VERSION 5.8 ;
BUSBITCHARS "[]" ;
DIVIDERCHAR "/" ;
UNITS
    DATABASE MICRONS 1000 ;
END UNITS

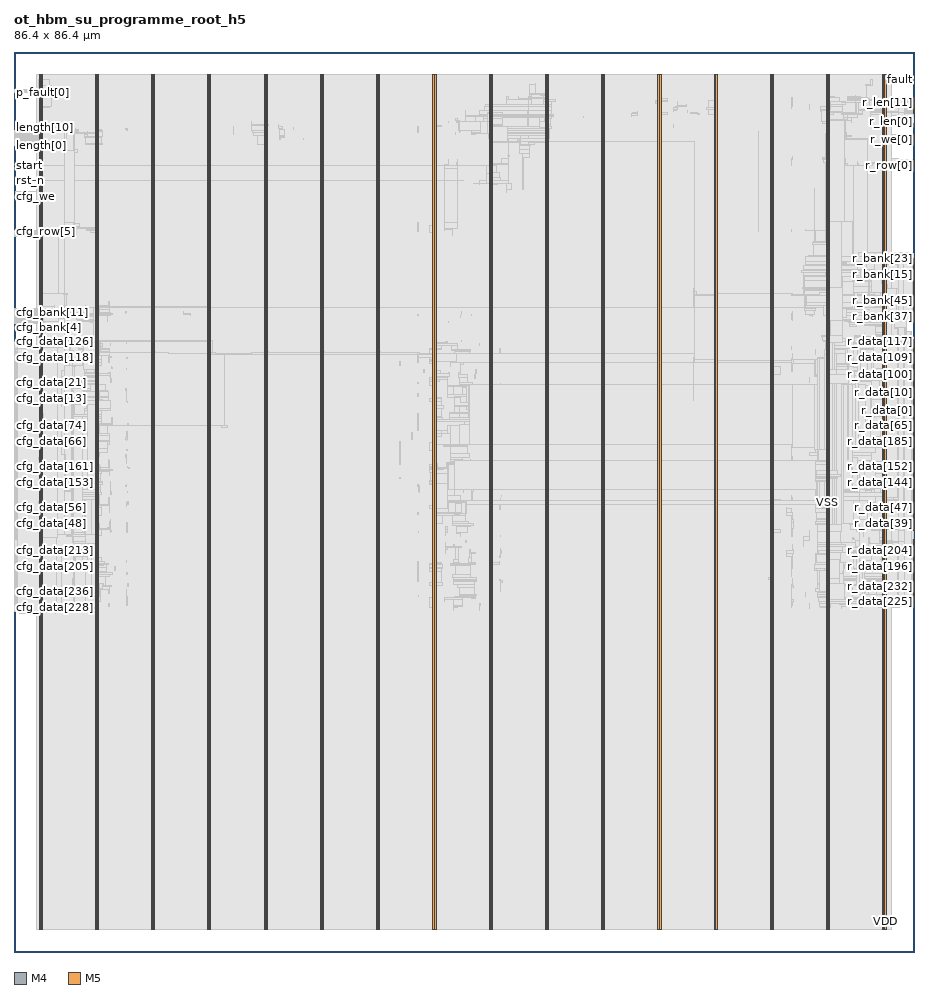
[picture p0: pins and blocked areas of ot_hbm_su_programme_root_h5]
MACRO ot_hbm_su_programme_root_h5
  FOREIGN ot_hbm_su_programme_root_h5 0 0 ;
  CLASS BLOCK ;
  SIZE 86.4 BY 86.4 ;
  PIN cfg_bank[0]
    DIRECTION INPUT ;
    USE SIGNAL ;
    PORT
      LAYER M4 ;
        RECT  0 60.336 0.084 60.36 ;
    END
  END cfg_bank[0]
  PIN cfg_bank[10]
    DIRECTION INPUT ;
    USE SIGNAL ;
    PORT
      LAYER M4 ;
        RECT  0 61.296 0.084 61.32 ;
    END
  END cfg_bank[10]
  PIN cfg_bank[11]
    DIRECTION INPUT ;
    USE SIGNAL ;
    PORT
      LAYER M4 ;
        RECT  0 61.392 0.084 61.416 ;
    END
  END cfg_bank[11]
  PIN cfg_bank[12]
    DIRECTION INPUT ;
    USE SIGNAL ;
    PORT
      LAYER M4 ;
        RECT  0 61.488 0.084 61.512 ;
    END
  END cfg_bank[12]
  PIN cfg_bank[13]
    DIRECTION INPUT ;
    USE SIGNAL ;
    PORT
      LAYER M4 ;
        RECT  0 61.584 0.084 61.608 ;
    END
  END cfg_bank[13]
  PIN cfg_bank[14]
    DIRECTION INPUT ;
    USE SIGNAL ;
    PORT
      LAYER M4 ;
        RECT  0 61.68 0.084 61.704 ;
    END
  END cfg_bank[14]
  PIN cfg_bank[15]
    DIRECTION INPUT ;
    USE SIGNAL ;
    PORT
      LAYER M4 ;
        RECT  0 61.776 0.084 61.8 ;
    END
  END cfg_bank[15]
  PIN cfg_bank[1]
    DIRECTION INPUT ;
    USE SIGNAL ;
    PORT
      LAYER M4 ;
        RECT  0 60.432 0.084 60.456 ;
    END
  END cfg_bank[1]
  PIN cfg_bank[2]
    DIRECTION INPUT ;
    USE SIGNAL ;
    PORT
      LAYER M4 ;
        RECT  0 60.528 0.084 60.552 ;
    END
  END cfg_bank[2]
  PIN cfg_bank[3]
    DIRECTION INPUT ;
    USE SIGNAL ;
    PORT
      LAYER M4 ;
        RECT  0 60.624 0.084 60.648 ;
    END
  END cfg_bank[3]
  PIN cfg_bank[4]
    DIRECTION INPUT ;
    USE SIGNAL ;
    PORT
      LAYER M4 ;
        RECT  0 60.72 0.084 60.744 ;
    END
  END cfg_bank[4]
  PIN cfg_bank[5]
    DIRECTION INPUT ;
    USE SIGNAL ;
    PORT
      LAYER M4 ;
        RECT  0 60.816 0.084 60.84 ;
    END
  END cfg_bank[5]
  PIN cfg_bank[6]
    DIRECTION INPUT ;
    USE SIGNAL ;
    PORT
      LAYER M4 ;
        RECT  0 60.912 0.084 60.936 ;
    END
  END cfg_bank[6]
  PIN cfg_bank[7]
    DIRECTION INPUT ;
    USE SIGNAL ;
    PORT
      LAYER M4 ;
        RECT  0 61.008 0.084 61.032 ;
    END
  END cfg_bank[7]
  PIN cfg_bank[8]
    DIRECTION INPUT ;
    USE SIGNAL ;
    PORT
      LAYER M4 ;
        RECT  0 61.104 0.084 61.128 ;
    END
  END cfg_bank[8]
  PIN cfg_bank[9]
    DIRECTION INPUT ;
    USE SIGNAL ;
    PORT
      LAYER M4 ;
        RECT  0 61.2 0.084 61.224 ;
    END
  END cfg_bank[9]
  PIN cfg_data[0]
    DIRECTION INPUT ;
    USE SIGNAL ;
    PORT
      LAYER M4 ;
        RECT  0 51.888 0.084 51.912 ;
    END
  END cfg_data[0]
  PIN cfg_data[100]
    DIRECTION INPUT ;
    USE SIGNAL ;
    PORT
      LAYER M4 ;
        RECT  0 55.344 0.084 55.368 ;
    END
  END cfg_data[100]
  PIN cfg_data[101]
    DIRECTION INPUT ;
    USE SIGNAL ;
    PORT
      LAYER M4 ;
        RECT  0 55.44 0.084 55.464 ;
    END
  END cfg_data[101]
  PIN cfg_data[102]
    DIRECTION INPUT ;
    USE SIGNAL ;
    PORT
      LAYER M4 ;
        RECT  0 55.536 0.084 55.56 ;
    END
  END cfg_data[102]
  PIN cfg_data[103]
    DIRECTION INPUT ;
    USE SIGNAL ;
    PORT
      LAYER M4 ;
        RECT  0 55.632 0.084 55.656 ;
    END
  END cfg_data[103]
  PIN cfg_data[104]
    DIRECTION INPUT ;
    USE SIGNAL ;
    PORT
      LAYER M4 ;
        RECT  0 55.728 0.084 55.752 ;
    END
  END cfg_data[104]
  PIN cfg_data[105]
    DIRECTION INPUT ;
    USE SIGNAL ;
    PORT
      LAYER M4 ;
        RECT  0 55.824 0.084 55.848 ;
    END
  END cfg_data[105]
  PIN cfg_data[106]
    DIRECTION INPUT ;
    USE SIGNAL ;
    PORT
      LAYER M4 ;
        RECT  0 55.92 0.084 55.944 ;
    END
  END cfg_data[106]
  PIN cfg_data[107]
    DIRECTION INPUT ;
    USE SIGNAL ;
    PORT
      LAYER M4 ;
        RECT  0 56.016 0.084 56.04 ;
    END
  END cfg_data[107]
  PIN cfg_data[108]
    DIRECTION INPUT ;
    USE SIGNAL ;
    PORT
      LAYER M4 ;
        RECT  0 56.112 0.084 56.136 ;
    END
  END cfg_data[108]
  PIN cfg_data[109]
    DIRECTION INPUT ;
    USE SIGNAL ;
    PORT
      LAYER M4 ;
        RECT  0 56.208 0.084 56.232 ;
    END
  END cfg_data[109]
  PIN cfg_data[10]
    DIRECTION INPUT ;
    USE SIGNAL ;
    PORT
      LAYER M4 ;
        RECT  0 52.848 0.084 52.872 ;
    END
  END cfg_data[10]
  PIN cfg_data[110]
    DIRECTION INPUT ;
    USE SIGNAL ;
    PORT
      LAYER M4 ;
        RECT  0 56.304 0.084 56.328 ;
    END
  END cfg_data[110]
  PIN cfg_data[111]
    DIRECTION INPUT ;
    USE SIGNAL ;
    PORT
      LAYER M4 ;
        RECT  0 56.4 0.084 56.424 ;
    END
  END cfg_data[111]
  PIN cfg_data[112]
    DIRECTION INPUT ;
    USE SIGNAL ;
    PORT
      LAYER M4 ;
        RECT  0 56.496 0.084 56.52 ;
    END
  END cfg_data[112]
  PIN cfg_data[113]
    DIRECTION INPUT ;
    USE SIGNAL ;
    PORT
      LAYER M4 ;
        RECT  0 56.592 0.084 56.616 ;
    END
  END cfg_data[113]
  PIN cfg_data[114]
    DIRECTION INPUT ;
    USE SIGNAL ;
    PORT
      LAYER M4 ;
        RECT  0 56.688 0.084 56.712 ;
    END
  END cfg_data[114]
  PIN cfg_data[115]
    DIRECTION INPUT ;
    USE SIGNAL ;
    PORT
      LAYER M4 ;
        RECT  0 56.784 0.084 56.808 ;
    END
  END cfg_data[115]
  PIN cfg_data[116]
    DIRECTION INPUT ;
    USE SIGNAL ;
    PORT
      LAYER M4 ;
        RECT  0 56.88 0.084 56.904 ;
    END
  END cfg_data[116]
  PIN cfg_data[117]
    DIRECTION INPUT ;
    USE SIGNAL ;
    PORT
      LAYER M4 ;
        RECT  0 56.976 0.084 57 ;
    END
  END cfg_data[117]
  PIN cfg_data[118]
    DIRECTION INPUT ;
    USE SIGNAL ;
    PORT
      LAYER M4 ;
        RECT  0 57.072 0.084 57.096 ;
    END
  END cfg_data[118]
  PIN cfg_data[119]
    DIRECTION INPUT ;
    USE SIGNAL ;
    PORT
      LAYER M4 ;
        RECT  0 57.168 0.084 57.192 ;
    END
  END cfg_data[119]
  PIN cfg_data[11]
    DIRECTION INPUT ;
    USE SIGNAL ;
    PORT
      LAYER M4 ;
        RECT  0 52.944 0.084 52.968 ;
    END
  END cfg_data[11]
  PIN cfg_data[120]
    DIRECTION INPUT ;
    USE SIGNAL ;
    PORT
      LAYER M4 ;
        RECT  0 57.264 0.084 57.288 ;
    END
  END cfg_data[120]
  PIN cfg_data[121]
    DIRECTION INPUT ;
    USE SIGNAL ;
    PORT
      LAYER M4 ;
        RECT  0 57.36 0.084 57.384 ;
    END
  END cfg_data[121]
  PIN cfg_data[122]
    DIRECTION INPUT ;
    USE SIGNAL ;
    PORT
      LAYER M4 ;
        RECT  0 57.456 0.084 57.48 ;
    END
  END cfg_data[122]
  PIN cfg_data[123]
    DIRECTION INPUT ;
    USE SIGNAL ;
    PORT
      LAYER M4 ;
        RECT  0 57.552 0.084 57.576 ;
    END
  END cfg_data[123]
  PIN cfg_data[124]
    DIRECTION INPUT ;
    USE SIGNAL ;
    PORT
      LAYER M4 ;
        RECT  0 57.648 0.084 57.672 ;
    END
  END cfg_data[124]
  PIN cfg_data[125]
    DIRECTION INPUT ;
    USE SIGNAL ;
    PORT
      LAYER M4 ;
        RECT  0 57.744 0.084 57.768 ;
    END
  END cfg_data[125]
  PIN cfg_data[126]
    DIRECTION INPUT ;
    USE SIGNAL ;
    PORT
      LAYER M4 ;
        RECT  0 57.84 0.084 57.864 ;
    END
  END cfg_data[126]
  PIN cfg_data[127]
    DIRECTION INPUT ;
    USE SIGNAL ;
    PORT
      LAYER M4 ;
        RECT  0 57.936 0.084 57.96 ;
    END
  END cfg_data[127]
  PIN cfg_data[128]
    DIRECTION INPUT ;
    USE SIGNAL ;
    PORT
      LAYER M4 ;
        RECT  0 42.672 0.084 42.696 ;
    END
  END cfg_data[128]
  PIN cfg_data[129]
    DIRECTION INPUT ;
    USE SIGNAL ;
    PORT
      LAYER M4 ;
        RECT  0 42.768 0.084 42.792 ;
    END
  END cfg_data[129]
  PIN cfg_data[12]
    DIRECTION INPUT ;
    USE SIGNAL ;
    PORT
      LAYER M4 ;
        RECT  0 53.04 0.084 53.064 ;
    END
  END cfg_data[12]
  PIN cfg_data[130]
    DIRECTION INPUT ;
    USE SIGNAL ;
    PORT
      LAYER M4 ;
        RECT  0 42.864 0.084 42.888 ;
    END
  END cfg_data[130]
  PIN cfg_data[131]
    DIRECTION INPUT ;
    USE SIGNAL ;
    PORT
      LAYER M4 ;
        RECT  0 42.96 0.084 42.984 ;
    END
  END cfg_data[131]
  PIN cfg_data[132]
    DIRECTION INPUT ;
    USE SIGNAL ;
    PORT
      LAYER M4 ;
        RECT  0 43.056 0.084 43.08 ;
    END
  END cfg_data[132]
  PIN cfg_data[133]
    DIRECTION INPUT ;
    USE SIGNAL ;
    PORT
      LAYER M4 ;
        RECT  0 43.152 0.084 43.176 ;
    END
  END cfg_data[133]
  PIN cfg_data[134]
    DIRECTION INPUT ;
    USE SIGNAL ;
    PORT
      LAYER M4 ;
        RECT  0 43.248 0.084 43.272 ;
    END
  END cfg_data[134]
  PIN cfg_data[135]
    DIRECTION INPUT ;
    USE SIGNAL ;
    PORT
      LAYER M4 ;
        RECT  0 43.344 0.084 43.368 ;
    END
  END cfg_data[135]
  PIN cfg_data[136]
    DIRECTION INPUT ;
    USE SIGNAL ;
    PORT
      LAYER M4 ;
        RECT  0 43.44 0.084 43.464 ;
    END
  END cfg_data[136]
  PIN cfg_data[137]
    DIRECTION INPUT ;
    USE SIGNAL ;
    PORT
      LAYER M4 ;
        RECT  0 43.536 0.084 43.56 ;
    END
  END cfg_data[137]
  PIN cfg_data[138]
    DIRECTION INPUT ;
    USE SIGNAL ;
    PORT
      LAYER M4 ;
        RECT  0 43.632 0.084 43.656 ;
    END
  END cfg_data[138]
  PIN cfg_data[139]
    DIRECTION INPUT ;
    USE SIGNAL ;
    PORT
      LAYER M4 ;
        RECT  0 43.728 0.084 43.752 ;
    END
  END cfg_data[139]
  PIN cfg_data[13]
    DIRECTION INPUT ;
    USE SIGNAL ;
    PORT
      LAYER M4 ;
        RECT  0 53.136 0.084 53.16 ;
    END
  END cfg_data[13]
  PIN cfg_data[140]
    DIRECTION INPUT ;
    USE SIGNAL ;
    PORT
      LAYER M4 ;
        RECT  0 43.824 0.084 43.848 ;
    END
  END cfg_data[140]
  PIN cfg_data[141]
    DIRECTION INPUT ;
    USE SIGNAL ;
    PORT
      LAYER M4 ;
        RECT  0 43.92 0.084 43.944 ;
    END
  END cfg_data[141]
  PIN cfg_data[142]
    DIRECTION INPUT ;
    USE SIGNAL ;
    PORT
      LAYER M4 ;
        RECT  0 44.016 0.084 44.04 ;
    END
  END cfg_data[142]
  PIN cfg_data[143]
    DIRECTION INPUT ;
    USE SIGNAL ;
    PORT
      LAYER M4 ;
        RECT  0 44.112 0.084 44.136 ;
    END
  END cfg_data[143]
  PIN cfg_data[144]
    DIRECTION INPUT ;
    USE SIGNAL ;
    PORT
      LAYER M4 ;
        RECT  0 44.208 0.084 44.232 ;
    END
  END cfg_data[144]
  PIN cfg_data[145]
    DIRECTION INPUT ;
    USE SIGNAL ;
    PORT
      LAYER M4 ;
        RECT  0 44.304 0.084 44.328 ;
    END
  END cfg_data[145]
  PIN cfg_data[146]
    DIRECTION INPUT ;
    USE SIGNAL ;
    PORT
      LAYER M4 ;
        RECT  0 44.4 0.084 44.424 ;
    END
  END cfg_data[146]
  PIN cfg_data[147]
    DIRECTION INPUT ;
    USE SIGNAL ;
    PORT
      LAYER M4 ;
        RECT  0 44.496 0.084 44.52 ;
    END
  END cfg_data[147]
  PIN cfg_data[148]
    DIRECTION INPUT ;
    USE SIGNAL ;
    PORT
      LAYER M4 ;
        RECT  0 44.592 0.084 44.616 ;
    END
  END cfg_data[148]
  PIN cfg_data[149]
    DIRECTION INPUT ;
    USE SIGNAL ;
    PORT
      LAYER M4 ;
        RECT  0 44.688 0.084 44.712 ;
    END
  END cfg_data[149]
  PIN cfg_data[14]
    DIRECTION INPUT ;
    USE SIGNAL ;
    PORT
      LAYER M4 ;
        RECT  0 53.232 0.084 53.256 ;
    END
  END cfg_data[14]
  PIN cfg_data[150]
    DIRECTION INPUT ;
    USE SIGNAL ;
    PORT
      LAYER M4 ;
        RECT  0 44.784 0.084 44.808 ;
    END
  END cfg_data[150]
  PIN cfg_data[151]
    DIRECTION INPUT ;
    USE SIGNAL ;
    PORT
      LAYER M4 ;
        RECT  0 44.88 0.084 44.904 ;
    END
  END cfg_data[151]
  PIN cfg_data[152]
    DIRECTION INPUT ;
    USE SIGNAL ;
    PORT
      LAYER M4 ;
        RECT  0 44.976 0.084 45 ;
    END
  END cfg_data[152]
  PIN cfg_data[153]
    DIRECTION INPUT ;
    USE SIGNAL ;
    PORT
      LAYER M4 ;
        RECT  0 45.072 0.084 45.096 ;
    END
  END cfg_data[153]
  PIN cfg_data[154]
    DIRECTION INPUT ;
    USE SIGNAL ;
    PORT
      LAYER M4 ;
        RECT  0 45.168 0.084 45.192 ;
    END
  END cfg_data[154]
  PIN cfg_data[155]
    DIRECTION INPUT ;
    USE SIGNAL ;
    PORT
      LAYER M4 ;
        RECT  0 45.264 0.084 45.288 ;
    END
  END cfg_data[155]
  PIN cfg_data[156]
    DIRECTION INPUT ;
    USE SIGNAL ;
    PORT
      LAYER M4 ;
        RECT  0 45.36 0.084 45.384 ;
    END
  END cfg_data[156]
  PIN cfg_data[157]
    DIRECTION INPUT ;
    USE SIGNAL ;
    PORT
      LAYER M4 ;
        RECT  0 45.456 0.084 45.48 ;
    END
  END cfg_data[157]
  PIN cfg_data[158]
    DIRECTION INPUT ;
    USE SIGNAL ;
    PORT
      LAYER M4 ;
        RECT  0 45.552 0.084 45.576 ;
    END
  END cfg_data[158]
  PIN cfg_data[159]
    DIRECTION INPUT ;
    USE SIGNAL ;
    PORT
      LAYER M4 ;
        RECT  0 45.648 0.084 45.672 ;
    END
  END cfg_data[159]
  PIN cfg_data[15]
    DIRECTION INPUT ;
    USE SIGNAL ;
    PORT
      LAYER M4 ;
        RECT  0 53.328 0.084 53.352 ;
    END
  END cfg_data[15]
  PIN cfg_data[160]
    DIRECTION INPUT ;
    USE SIGNAL ;
    PORT
      LAYER M4 ;
        RECT  0 45.744 0.084 45.768 ;
    END
  END cfg_data[160]
  PIN cfg_data[161]
    DIRECTION INPUT ;
    USE SIGNAL ;
    PORT
      LAYER M4 ;
        RECT  0 45.84 0.084 45.864 ;
    END
  END cfg_data[161]
  PIN cfg_data[162]
    DIRECTION INPUT ;
    USE SIGNAL ;
    PORT
      LAYER M4 ;
        RECT  0 45.936 0.084 45.96 ;
    END
  END cfg_data[162]
  PIN cfg_data[163]
    DIRECTION INPUT ;
    USE SIGNAL ;
    PORT
      LAYER M4 ;
        RECT  0 46.032 0.084 46.056 ;
    END
  END cfg_data[163]
  PIN cfg_data[164]
    DIRECTION INPUT ;
    USE SIGNAL ;
    PORT
      LAYER M4 ;
        RECT  0 46.128 0.084 46.152 ;
    END
  END cfg_data[164]
  PIN cfg_data[165]
    DIRECTION INPUT ;
    USE SIGNAL ;
    PORT
      LAYER M4 ;
        RECT  0 46.224 0.084 46.248 ;
    END
  END cfg_data[165]
  PIN cfg_data[166]
    DIRECTION INPUT ;
    USE SIGNAL ;
    PORT
      LAYER M4 ;
        RECT  0 46.32 0.084 46.344 ;
    END
  END cfg_data[166]
  PIN cfg_data[167]
    DIRECTION INPUT ;
    USE SIGNAL ;
    PORT
      LAYER M4 ;
        RECT  0 46.416 0.084 46.44 ;
    END
  END cfg_data[167]
  PIN cfg_data[168]
    DIRECTION INPUT ;
    USE SIGNAL ;
    PORT
      LAYER M4 ;
        RECT  0 46.512 0.084 46.536 ;
    END
  END cfg_data[168]
  PIN cfg_data[169]
    DIRECTION INPUT ;
    USE SIGNAL ;
    PORT
      LAYER M4 ;
        RECT  0 46.608 0.084 46.632 ;
    END
  END cfg_data[169]
  PIN cfg_data[16]
    DIRECTION INPUT ;
    USE SIGNAL ;
    PORT
      LAYER M4 ;
        RECT  0 53.424 0.084 53.448 ;
    END
  END cfg_data[16]
  PIN cfg_data[170]
    DIRECTION INPUT ;
    USE SIGNAL ;
    PORT
      LAYER M4 ;
        RECT  0 46.704 0.084 46.728 ;
    END
  END cfg_data[170]
  PIN cfg_data[171]
    DIRECTION INPUT ;
    USE SIGNAL ;
    PORT
      LAYER M4 ;
        RECT  0 46.8 0.084 46.824 ;
    END
  END cfg_data[171]
  PIN cfg_data[172]
    DIRECTION INPUT ;
    USE SIGNAL ;
    PORT
      LAYER M4 ;
        RECT  0 46.896 0.084 46.92 ;
    END
  END cfg_data[172]
  PIN cfg_data[173]
    DIRECTION INPUT ;
    USE SIGNAL ;
    PORT
      LAYER M4 ;
        RECT  0 46.992 0.084 47.016 ;
    END
  END cfg_data[173]
  PIN cfg_data[174]
    DIRECTION INPUT ;
    USE SIGNAL ;
    PORT
      LAYER M4 ;
        RECT  0 47.088 0.084 47.112 ;
    END
  END cfg_data[174]
  PIN cfg_data[175]
    DIRECTION INPUT ;
    USE SIGNAL ;
    PORT
      LAYER M4 ;
        RECT  0 47.184 0.084 47.208 ;
    END
  END cfg_data[175]
  PIN cfg_data[176]
    DIRECTION INPUT ;
    USE SIGNAL ;
    PORT
      LAYER M4 ;
        RECT  0 47.28 0.084 47.304 ;
    END
  END cfg_data[176]
  PIN cfg_data[177]
    DIRECTION INPUT ;
    USE SIGNAL ;
    PORT
      LAYER M4 ;
        RECT  0 47.376 0.084 47.4 ;
    END
  END cfg_data[177]
  PIN cfg_data[178]
    DIRECTION INPUT ;
    USE SIGNAL ;
    PORT
      LAYER M4 ;
        RECT  0 47.472 0.084 47.496 ;
    END
  END cfg_data[178]
  PIN cfg_data[179]
    DIRECTION INPUT ;
    USE SIGNAL ;
    PORT
      LAYER M4 ;
        RECT  0 47.568 0.084 47.592 ;
    END
  END cfg_data[179]
  PIN cfg_data[17]
    DIRECTION INPUT ;
    USE SIGNAL ;
    PORT
      LAYER M4 ;
        RECT  0 53.52 0.084 53.544 ;
    END
  END cfg_data[17]
  PIN cfg_data[180]
    DIRECTION INPUT ;
    USE SIGNAL ;
    PORT
      LAYER M4 ;
        RECT  0 47.664 0.084 47.688 ;
    END
  END cfg_data[180]
  PIN cfg_data[181]
    DIRECTION INPUT ;
    USE SIGNAL ;
    PORT
      LAYER M4 ;
        RECT  0 47.76 0.084 47.784 ;
    END
  END cfg_data[181]
  PIN cfg_data[182]
    DIRECTION INPUT ;
    USE SIGNAL ;
    PORT
      LAYER M4 ;
        RECT  0 47.856 0.084 47.88 ;
    END
  END cfg_data[182]
  PIN cfg_data[183]
    DIRECTION INPUT ;
    USE SIGNAL ;
    PORT
      LAYER M4 ;
        RECT  0 47.952 0.084 47.976 ;
    END
  END cfg_data[183]
  PIN cfg_data[184]
    DIRECTION INPUT ;
    USE SIGNAL ;
    PORT
      LAYER M4 ;
        RECT  0 48.048 0.084 48.072 ;
    END
  END cfg_data[184]
  PIN cfg_data[185]
    DIRECTION INPUT ;
    USE SIGNAL ;
    PORT
      LAYER M4 ;
        RECT  0 48.144 0.084 48.168 ;
    END
  END cfg_data[185]
  PIN cfg_data[186]
    DIRECTION INPUT ;
    USE SIGNAL ;
    PORT
      LAYER M4 ;
        RECT  0 48.24 0.084 48.264 ;
    END
  END cfg_data[186]
  PIN cfg_data[187]
    DIRECTION INPUT ;
    USE SIGNAL ;
    PORT
      LAYER M4 ;
        RECT  0 48.336 0.084 48.36 ;
    END
  END cfg_data[187]
  PIN cfg_data[188]
    DIRECTION INPUT ;
    USE SIGNAL ;
    PORT
      LAYER M4 ;
        RECT  0 48.432 0.084 48.456 ;
    END
  END cfg_data[188]
  PIN cfg_data[189]
    DIRECTION INPUT ;
    USE SIGNAL ;
    PORT
      LAYER M4 ;
        RECT  0 48.528 0.084 48.552 ;
    END
  END cfg_data[189]
  PIN cfg_data[18]
    DIRECTION INPUT ;
    USE SIGNAL ;
    PORT
      LAYER M4 ;
        RECT  0 53.616 0.084 53.64 ;
    END
  END cfg_data[18]
  PIN cfg_data[190]
    DIRECTION INPUT ;
    USE SIGNAL ;
    PORT
      LAYER M4 ;
        RECT  0 48.624 0.084 48.648 ;
    END
  END cfg_data[190]
  PIN cfg_data[191]
    DIRECTION INPUT ;
    USE SIGNAL ;
    PORT
      LAYER M4 ;
        RECT  0 48.72 0.084 48.744 ;
    END
  END cfg_data[191]
  PIN cfg_data[192]
    DIRECTION INPUT ;
    USE SIGNAL ;
    PORT
      LAYER M4 ;
        RECT  0 35.76 0.084 35.784 ;
    END
  END cfg_data[192]
  PIN cfg_data[193]
    DIRECTION INPUT ;
    USE SIGNAL ;
    PORT
      LAYER M4 ;
        RECT  0 35.856 0.084 35.88 ;
    END
  END cfg_data[193]
  PIN cfg_data[194]
    DIRECTION INPUT ;
    USE SIGNAL ;
    PORT
      LAYER M4 ;
        RECT  0 35.952 0.084 35.976 ;
    END
  END cfg_data[194]
  PIN cfg_data[195]
    DIRECTION INPUT ;
    USE SIGNAL ;
    PORT
      LAYER M4 ;
        RECT  0 36.048 0.084 36.072 ;
    END
  END cfg_data[195]
  PIN cfg_data[196]
    DIRECTION INPUT ;
    USE SIGNAL ;
    PORT
      LAYER M4 ;
        RECT  0 36.144 0.084 36.168 ;
    END
  END cfg_data[196]
  PIN cfg_data[197]
    DIRECTION INPUT ;
    USE SIGNAL ;
    PORT
      LAYER M4 ;
        RECT  0 36.24 0.084 36.264 ;
    END
  END cfg_data[197]
  PIN cfg_data[198]
    DIRECTION INPUT ;
    USE SIGNAL ;
    PORT
      LAYER M4 ;
        RECT  0 36.336 0.084 36.36 ;
    END
  END cfg_data[198]
  PIN cfg_data[199]
    DIRECTION INPUT ;
    USE SIGNAL ;
    PORT
      LAYER M4 ;
        RECT  0 36.432 0.084 36.456 ;
    END
  END cfg_data[199]
  PIN cfg_data[19]
    DIRECTION INPUT ;
    USE SIGNAL ;
    PORT
      LAYER M4 ;
        RECT  0 53.712 0.084 53.736 ;
    END
  END cfg_data[19]
  PIN cfg_data[1]
    DIRECTION INPUT ;
    USE SIGNAL ;
    PORT
      LAYER M4 ;
        RECT  0 51.984 0.084 52.008 ;
    END
  END cfg_data[1]
  PIN cfg_data[200]
    DIRECTION INPUT ;
    USE SIGNAL ;
    PORT
      LAYER M4 ;
        RECT  0 36.528 0.084 36.552 ;
    END
  END cfg_data[200]
  PIN cfg_data[201]
    DIRECTION INPUT ;
    USE SIGNAL ;
    PORT
      LAYER M4 ;
        RECT  0 36.624 0.084 36.648 ;
    END
  END cfg_data[201]
  PIN cfg_data[202]
    DIRECTION INPUT ;
    USE SIGNAL ;
    PORT
      LAYER M4 ;
        RECT  0 36.72 0.084 36.744 ;
    END
  END cfg_data[202]
  PIN cfg_data[203]
    DIRECTION INPUT ;
    USE SIGNAL ;
    PORT
      LAYER M4 ;
        RECT  0 36.816 0.084 36.84 ;
    END
  END cfg_data[203]
  PIN cfg_data[204]
    DIRECTION INPUT ;
    USE SIGNAL ;
    PORT
      LAYER M4 ;
        RECT  0 36.912 0.084 36.936 ;
    END
  END cfg_data[204]
  PIN cfg_data[205]
    DIRECTION INPUT ;
    USE SIGNAL ;
    PORT
      LAYER M4 ;
        RECT  0 37.008 0.084 37.032 ;
    END
  END cfg_data[205]
  PIN cfg_data[206]
    DIRECTION INPUT ;
    USE SIGNAL ;
    PORT
      LAYER M4 ;
        RECT  0 37.104 0.084 37.128 ;
    END
  END cfg_data[206]
  PIN cfg_data[207]
    DIRECTION INPUT ;
    USE SIGNAL ;
    PORT
      LAYER M4 ;
        RECT  0 37.2 0.084 37.224 ;
    END
  END cfg_data[207]
  PIN cfg_data[208]
    DIRECTION INPUT ;
    USE SIGNAL ;
    PORT
      LAYER M4 ;
        RECT  0 37.296 0.084 37.32 ;
    END
  END cfg_data[208]
  PIN cfg_data[209]
    DIRECTION INPUT ;
    USE SIGNAL ;
    PORT
      LAYER M4 ;
        RECT  0 37.392 0.084 37.416 ;
    END
  END cfg_data[209]
  PIN cfg_data[20]
    DIRECTION INPUT ;
    USE SIGNAL ;
    PORT
      LAYER M4 ;
        RECT  0 53.808 0.084 53.832 ;
    END
  END cfg_data[20]
  PIN cfg_data[210]
    DIRECTION INPUT ;
    USE SIGNAL ;
    PORT
      LAYER M4 ;
        RECT  0 37.488 0.084 37.512 ;
    END
  END cfg_data[210]
  PIN cfg_data[211]
    DIRECTION INPUT ;
    USE SIGNAL ;
    PORT
      LAYER M4 ;
        RECT  0 37.584 0.084 37.608 ;
    END
  END cfg_data[211]
  PIN cfg_data[212]
    DIRECTION INPUT ;
    USE SIGNAL ;
    PORT
      LAYER M4 ;
        RECT  0 37.68 0.084 37.704 ;
    END
  END cfg_data[212]
  PIN cfg_data[213]
    DIRECTION INPUT ;
    USE SIGNAL ;
    PORT
      LAYER M4 ;
        RECT  0 37.776 0.084 37.8 ;
    END
  END cfg_data[213]
  PIN cfg_data[214]
    DIRECTION INPUT ;
    USE SIGNAL ;
    PORT
      LAYER M4 ;
        RECT  0 37.872 0.084 37.896 ;
    END
  END cfg_data[214]
  PIN cfg_data[215]
    DIRECTION INPUT ;
    USE SIGNAL ;
    PORT
      LAYER M4 ;
        RECT  0 37.968 0.084 37.992 ;
    END
  END cfg_data[215]
  PIN cfg_data[216]
    DIRECTION INPUT ;
    USE SIGNAL ;
    PORT
      LAYER M4 ;
        RECT  0 38.064 0.084 38.088 ;
    END
  END cfg_data[216]
  PIN cfg_data[217]
    DIRECTION INPUT ;
    USE SIGNAL ;
    PORT
      LAYER M4 ;
        RECT  0 38.16 0.084 38.184 ;
    END
  END cfg_data[217]
  PIN cfg_data[218]
    DIRECTION INPUT ;
    USE SIGNAL ;
    PORT
      LAYER M4 ;
        RECT  0 38.256 0.084 38.28 ;
    END
  END cfg_data[218]
  PIN cfg_data[219]
    DIRECTION INPUT ;
    USE SIGNAL ;
    PORT
      LAYER M4 ;
        RECT  0 38.352 0.084 38.376 ;
    END
  END cfg_data[219]
  PIN cfg_data[21]
    DIRECTION INPUT ;
    USE SIGNAL ;
    PORT
      LAYER M4 ;
        RECT  0 53.904 0.084 53.928 ;
    END
  END cfg_data[21]
  PIN cfg_data[220]
    DIRECTION INPUT ;
    USE SIGNAL ;
    PORT
      LAYER M4 ;
        RECT  0 38.448 0.084 38.472 ;
    END
  END cfg_data[220]
  PIN cfg_data[221]
    DIRECTION INPUT ;
    USE SIGNAL ;
    PORT
      LAYER M4 ;
        RECT  0 38.544 0.084 38.568 ;
    END
  END cfg_data[221]
  PIN cfg_data[222]
    DIRECTION INPUT ;
    USE SIGNAL ;
    PORT
      LAYER M4 ;
        RECT  0 38.64 0.084 38.664 ;
    END
  END cfg_data[222]
  PIN cfg_data[223]
    DIRECTION INPUT ;
    USE SIGNAL ;
    PORT
      LAYER M4 ;
        RECT  0 38.736 0.084 38.76 ;
    END
  END cfg_data[223]
  PIN cfg_data[224]
    DIRECTION INPUT ;
    USE SIGNAL ;
    PORT
      LAYER M4 ;
        RECT  0 32.688 0.084 32.712 ;
    END
  END cfg_data[224]
  PIN cfg_data[225]
    DIRECTION INPUT ;
    USE SIGNAL ;
    PORT
      LAYER M4 ;
        RECT  0 32.784 0.084 32.808 ;
    END
  END cfg_data[225]
  PIN cfg_data[226]
    DIRECTION INPUT ;
    USE SIGNAL ;
    PORT
      LAYER M4 ;
        RECT  0 32.88 0.084 32.904 ;
    END
  END cfg_data[226]
  PIN cfg_data[227]
    DIRECTION INPUT ;
    USE SIGNAL ;
    PORT
      LAYER M4 ;
        RECT  0 32.976 0.084 33 ;
    END
  END cfg_data[227]
  PIN cfg_data[228]
    DIRECTION INPUT ;
    USE SIGNAL ;
    PORT
      LAYER M4 ;
        RECT  0 33.072 0.084 33.096 ;
    END
  END cfg_data[228]
  PIN cfg_data[229]
    DIRECTION INPUT ;
    USE SIGNAL ;
    PORT
      LAYER M4 ;
        RECT  0 33.168 0.084 33.192 ;
    END
  END cfg_data[229]
  PIN cfg_data[22]
    DIRECTION INPUT ;
    USE SIGNAL ;
    PORT
      LAYER M4 ;
        RECT  0 54 0.084 54.024 ;
    END
  END cfg_data[22]
  PIN cfg_data[230]
    DIRECTION INPUT ;
    USE SIGNAL ;
    PORT
      LAYER M4 ;
        RECT  0 33.264 0.084 33.288 ;
    END
  END cfg_data[230]
  PIN cfg_data[231]
    DIRECTION INPUT ;
    USE SIGNAL ;
    PORT
      LAYER M4 ;
        RECT  0 33.36 0.084 33.384 ;
    END
  END cfg_data[231]
  PIN cfg_data[232]
    DIRECTION INPUT ;
    USE SIGNAL ;
    PORT
      LAYER M4 ;
        RECT  0 33.456 0.084 33.48 ;
    END
  END cfg_data[232]
  PIN cfg_data[233]
    DIRECTION INPUT ;
    USE SIGNAL ;
    PORT
      LAYER M4 ;
        RECT  0 33.552 0.084 33.576 ;
    END
  END cfg_data[233]
  PIN cfg_data[234]
    DIRECTION INPUT ;
    USE SIGNAL ;
    PORT
      LAYER M4 ;
        RECT  0 33.648 0.084 33.672 ;
    END
  END cfg_data[234]
  PIN cfg_data[235]
    DIRECTION INPUT ;
    USE SIGNAL ;
    PORT
      LAYER M4 ;
        RECT  0 33.744 0.084 33.768 ;
    END
  END cfg_data[235]
  PIN cfg_data[236]
    DIRECTION INPUT ;
    USE SIGNAL ;
    PORT
      LAYER M4 ;
        RECT  0 33.84 0.084 33.864 ;
    END
  END cfg_data[236]
  PIN cfg_data[237]
    DIRECTION INPUT ;
    USE SIGNAL ;
    PORT
      LAYER M4 ;
        RECT  0 33.936 0.084 33.96 ;
    END
  END cfg_data[237]
  PIN cfg_data[238]
    DIRECTION INPUT ;
    USE SIGNAL ;
    PORT
      LAYER M4 ;
        RECT  0 34.032 0.084 34.056 ;
    END
  END cfg_data[238]
  PIN cfg_data[239]
    DIRECTION INPUT ;
    USE SIGNAL ;
    PORT
      LAYER M4 ;
        RECT  0 34.128 0.084 34.152 ;
    END
  END cfg_data[239]
  PIN cfg_data[23]
    DIRECTION INPUT ;
    USE SIGNAL ;
    PORT
      LAYER M4 ;
        RECT  0 54.096 0.084 54.12 ;
    END
  END cfg_data[23]
  PIN cfg_data[240]
    DIRECTION INPUT ;
    USE SIGNAL ;
    PORT
      LAYER M4 ;
        RECT  0 34.224 0.084 34.248 ;
    END
  END cfg_data[240]
  PIN cfg_data[241]
    DIRECTION INPUT ;
    USE SIGNAL ;
    PORT
      LAYER M4 ;
        RECT  0 34.32 0.084 34.344 ;
    END
  END cfg_data[241]
  PIN cfg_data[242]
    DIRECTION INPUT ;
    USE SIGNAL ;
    PORT
      LAYER M4 ;
        RECT  0 34.416 0.084 34.44 ;
    END
  END cfg_data[242]
  PIN cfg_data[243]
    DIRECTION INPUT ;
    USE SIGNAL ;
    PORT
      LAYER M4 ;
        RECT  0 34.512 0.084 34.536 ;
    END
  END cfg_data[243]
  PIN cfg_data[244]
    DIRECTION INPUT ;
    USE SIGNAL ;
    PORT
      LAYER M4 ;
        RECT  0 34.608 0.084 34.632 ;
    END
  END cfg_data[244]
  PIN cfg_data[245]
    DIRECTION INPUT ;
    USE SIGNAL ;
    PORT
      LAYER M4 ;
        RECT  0 34.704 0.084 34.728 ;
    END
  END cfg_data[245]
  PIN cfg_data[246]
    DIRECTION INPUT ;
    USE SIGNAL ;
    PORT
      LAYER M4 ;
        RECT  0 34.8 0.084 34.824 ;
    END
  END cfg_data[246]
  PIN cfg_data[247]
    DIRECTION INPUT ;
    USE SIGNAL ;
    PORT
      LAYER M4 ;
        RECT  0 34.896 0.084 34.92 ;
    END
  END cfg_data[247]
  PIN cfg_data[248]
    DIRECTION INPUT ;
    USE SIGNAL ;
    PORT
      LAYER M4 ;
        RECT  0 34.992 0.084 35.016 ;
    END
  END cfg_data[248]
  PIN cfg_data[249]
    DIRECTION INPUT ;
    USE SIGNAL ;
    PORT
      LAYER M4 ;
        RECT  0 35.088 0.084 35.112 ;
    END
  END cfg_data[249]
  PIN cfg_data[24]
    DIRECTION INPUT ;
    USE SIGNAL ;
    PORT
      LAYER M4 ;
        RECT  0 54.192 0.084 54.216 ;
    END
  END cfg_data[24]
  PIN cfg_data[250]
    DIRECTION INPUT ;
    USE SIGNAL ;
    PORT
      LAYER M4 ;
        RECT  0 35.184 0.084 35.208 ;
    END
  END cfg_data[250]
  PIN cfg_data[251]
    DIRECTION INPUT ;
    USE SIGNAL ;
    PORT
      LAYER M4 ;
        RECT  0 35.28 0.084 35.304 ;
    END
  END cfg_data[251]
  PIN cfg_data[252]
    DIRECTION INPUT ;
    USE SIGNAL ;
    PORT
      LAYER M4 ;
        RECT  0 35.376 0.084 35.4 ;
    END
  END cfg_data[252]
  PIN cfg_data[253]
    DIRECTION INPUT ;
    USE SIGNAL ;
    PORT
      LAYER M4 ;
        RECT  0 35.472 0.084 35.496 ;
    END
  END cfg_data[253]
  PIN cfg_data[254]
    DIRECTION INPUT ;
    USE SIGNAL ;
    PORT
      LAYER M4 ;
        RECT  0 35.568 0.084 35.592 ;
    END
  END cfg_data[254]
  PIN cfg_data[255]
    DIRECTION INPUT ;
    USE SIGNAL ;
    PORT
      LAYER M4 ;
        RECT  0 35.664 0.084 35.688 ;
    END
  END cfg_data[255]
  PIN cfg_data[25]
    DIRECTION INPUT ;
    USE SIGNAL ;
    PORT
      LAYER M4 ;
        RECT  0 54.288 0.084 54.312 ;
    END
  END cfg_data[25]
  PIN cfg_data[26]
    DIRECTION INPUT ;
    USE SIGNAL ;
    PORT
      LAYER M4 ;
        RECT  0 54.384 0.084 54.408 ;
    END
  END cfg_data[26]
  PIN cfg_data[27]
    DIRECTION INPUT ;
    USE SIGNAL ;
    PORT
      LAYER M4 ;
        RECT  0 54.48 0.084 54.504 ;
    END
  END cfg_data[27]
  PIN cfg_data[28]
    DIRECTION INPUT ;
    USE SIGNAL ;
    PORT
      LAYER M4 ;
        RECT  0 54.576 0.084 54.6 ;
    END
  END cfg_data[28]
  PIN cfg_data[29]
    DIRECTION INPUT ;
    USE SIGNAL ;
    PORT
      LAYER M4 ;
        RECT  0 54.672 0.084 54.696 ;
    END
  END cfg_data[29]
  PIN cfg_data[2]
    DIRECTION INPUT ;
    USE SIGNAL ;
    PORT
      LAYER M4 ;
        RECT  0 52.08 0.084 52.104 ;
    END
  END cfg_data[2]
  PIN cfg_data[30]
    DIRECTION INPUT ;
    USE SIGNAL ;
    PORT
      LAYER M4 ;
        RECT  0 54.768 0.084 54.792 ;
    END
  END cfg_data[30]
  PIN cfg_data[31]
    DIRECTION INPUT ;
    USE SIGNAL ;
    PORT
      LAYER M4 ;
        RECT  0 54.864 0.084 54.888 ;
    END
  END cfg_data[31]
  PIN cfg_data[32]
    DIRECTION INPUT ;
    USE SIGNAL ;
    PORT
      LAYER M4 ;
        RECT  0 39.6 0.084 39.624 ;
    END
  END cfg_data[32]
  PIN cfg_data[33]
    DIRECTION INPUT ;
    USE SIGNAL ;
    PORT
      LAYER M4 ;
        RECT  0 39.696 0.084 39.72 ;
    END
  END cfg_data[33]
  PIN cfg_data[34]
    DIRECTION INPUT ;
    USE SIGNAL ;
    PORT
      LAYER M4 ;
        RECT  0 39.792 0.084 39.816 ;
    END
  END cfg_data[34]
  PIN cfg_data[35]
    DIRECTION INPUT ;
    USE SIGNAL ;
    PORT
      LAYER M4 ;
        RECT  0 39.888 0.084 39.912 ;
    END
  END cfg_data[35]
  PIN cfg_data[36]
    DIRECTION INPUT ;
    USE SIGNAL ;
    PORT
      LAYER M4 ;
        RECT  0 39.984 0.084 40.008 ;
    END
  END cfg_data[36]
  PIN cfg_data[37]
    DIRECTION INPUT ;
    USE SIGNAL ;
    PORT
      LAYER M4 ;
        RECT  0 40.08 0.084 40.104 ;
    END
  END cfg_data[37]
  PIN cfg_data[38]
    DIRECTION INPUT ;
    USE SIGNAL ;
    PORT
      LAYER M4 ;
        RECT  0 40.176 0.084 40.2 ;
    END
  END cfg_data[38]
  PIN cfg_data[39]
    DIRECTION INPUT ;
    USE SIGNAL ;
    PORT
      LAYER M4 ;
        RECT  0 40.272 0.084 40.296 ;
    END
  END cfg_data[39]
  PIN cfg_data[3]
    DIRECTION INPUT ;
    USE SIGNAL ;
    PORT
      LAYER M4 ;
        RECT  0 52.176 0.084 52.2 ;
    END
  END cfg_data[3]
  PIN cfg_data[40]
    DIRECTION INPUT ;
    USE SIGNAL ;
    PORT
      LAYER M4 ;
        RECT  0 40.368 0.084 40.392 ;
    END
  END cfg_data[40]
  PIN cfg_data[41]
    DIRECTION INPUT ;
    USE SIGNAL ;
    PORT
      LAYER M4 ;
        RECT  0 40.464 0.084 40.488 ;
    END
  END cfg_data[41]
  PIN cfg_data[42]
    DIRECTION INPUT ;
    USE SIGNAL ;
    PORT
      LAYER M4 ;
        RECT  0 40.56 0.084 40.584 ;
    END
  END cfg_data[42]
  PIN cfg_data[43]
    DIRECTION INPUT ;
    USE SIGNAL ;
    PORT
      LAYER M4 ;
        RECT  0 40.656 0.084 40.68 ;
    END
  END cfg_data[43]
  PIN cfg_data[44]
    DIRECTION INPUT ;
    USE SIGNAL ;
    PORT
      LAYER M4 ;
        RECT  0 40.752 0.084 40.776 ;
    END
  END cfg_data[44]
  PIN cfg_data[45]
    DIRECTION INPUT ;
    USE SIGNAL ;
    PORT
      LAYER M4 ;
        RECT  0 40.848 0.084 40.872 ;
    END
  END cfg_data[45]
  PIN cfg_data[46]
    DIRECTION INPUT ;
    USE SIGNAL ;
    PORT
      LAYER M4 ;
        RECT  0 40.944 0.084 40.968 ;
    END
  END cfg_data[46]
  PIN cfg_data[47]
    DIRECTION INPUT ;
    USE SIGNAL ;
    PORT
      LAYER M4 ;
        RECT  0 41.04 0.084 41.064 ;
    END
  END cfg_data[47]
  PIN cfg_data[48]
    DIRECTION INPUT ;
    USE SIGNAL ;
    PORT
      LAYER M4 ;
        RECT  0 41.136 0.084 41.16 ;
    END
  END cfg_data[48]
  PIN cfg_data[49]
    DIRECTION INPUT ;
    USE SIGNAL ;
    PORT
      LAYER M4 ;
        RECT  0 41.232 0.084 41.256 ;
    END
  END cfg_data[49]
  PIN cfg_data[4]
    DIRECTION INPUT ;
    USE SIGNAL ;
    PORT
      LAYER M4 ;
        RECT  0 52.272 0.084 52.296 ;
    END
  END cfg_data[4]
  PIN cfg_data[50]
    DIRECTION INPUT ;
    USE SIGNAL ;
    PORT
      LAYER M4 ;
        RECT  0 41.328 0.084 41.352 ;
    END
  END cfg_data[50]
  PIN cfg_data[51]
    DIRECTION INPUT ;
    USE SIGNAL ;
    PORT
      LAYER M4 ;
        RECT  0 41.424 0.084 41.448 ;
    END
  END cfg_data[51]
  PIN cfg_data[52]
    DIRECTION INPUT ;
    USE SIGNAL ;
    PORT
      LAYER M4 ;
        RECT  0 41.52 0.084 41.544 ;
    END
  END cfg_data[52]
  PIN cfg_data[53]
    DIRECTION INPUT ;
    USE SIGNAL ;
    PORT
      LAYER M4 ;
        RECT  0 41.616 0.084 41.64 ;
    END
  END cfg_data[53]
  PIN cfg_data[54]
    DIRECTION INPUT ;
    USE SIGNAL ;
    PORT
      LAYER M4 ;
        RECT  0 41.712 0.084 41.736 ;
    END
  END cfg_data[54]
  PIN cfg_data[55]
    DIRECTION INPUT ;
    USE SIGNAL ;
    PORT
      LAYER M4 ;
        RECT  0 41.808 0.084 41.832 ;
    END
  END cfg_data[55]
  PIN cfg_data[56]
    DIRECTION INPUT ;
    USE SIGNAL ;
    PORT
      LAYER M4 ;
        RECT  0 41.904 0.084 41.928 ;
    END
  END cfg_data[56]
  PIN cfg_data[57]
    DIRECTION INPUT ;
    USE SIGNAL ;
    PORT
      LAYER M4 ;
        RECT  0 42 0.084 42.024 ;
    END
  END cfg_data[57]
  PIN cfg_data[58]
    DIRECTION INPUT ;
    USE SIGNAL ;
    PORT
      LAYER M4 ;
        RECT  0 42.096 0.084 42.12 ;
    END
  END cfg_data[58]
  PIN cfg_data[59]
    DIRECTION INPUT ;
    USE SIGNAL ;
    PORT
      LAYER M4 ;
        RECT  0 42.192 0.084 42.216 ;
    END
  END cfg_data[59]
  PIN cfg_data[5]
    DIRECTION INPUT ;
    USE SIGNAL ;
    PORT
      LAYER M4 ;
        RECT  0 52.368 0.084 52.392 ;
    END
  END cfg_data[5]
  PIN cfg_data[60]
    DIRECTION INPUT ;
    USE SIGNAL ;
    PORT
      LAYER M4 ;
        RECT  0 42.288 0.084 42.312 ;
    END
  END cfg_data[60]
  PIN cfg_data[61]
    DIRECTION INPUT ;
    USE SIGNAL ;
    PORT
      LAYER M4 ;
        RECT  0 42.384 0.084 42.408 ;
    END
  END cfg_data[61]
  PIN cfg_data[62]
    DIRECTION INPUT ;
    USE SIGNAL ;
    PORT
      LAYER M4 ;
        RECT  0 42.48 0.084 42.504 ;
    END
  END cfg_data[62]
  PIN cfg_data[63]
    DIRECTION INPUT ;
    USE SIGNAL ;
    PORT
      LAYER M4 ;
        RECT  0 42.576 0.084 42.6 ;
    END
  END cfg_data[63]
  PIN cfg_data[64]
    DIRECTION INPUT ;
    USE SIGNAL ;
    PORT
      LAYER M4 ;
        RECT  0 48.816 0.084 48.84 ;
    END
  END cfg_data[64]
  PIN cfg_data[65]
    DIRECTION INPUT ;
    USE SIGNAL ;
    PORT
      LAYER M4 ;
        RECT  0 48.912 0.084 48.936 ;
    END
  END cfg_data[65]
  PIN cfg_data[66]
    DIRECTION INPUT ;
    USE SIGNAL ;
    PORT
      LAYER M4 ;
        RECT  0 49.008 0.084 49.032 ;
    END
  END cfg_data[66]
  PIN cfg_data[67]
    DIRECTION INPUT ;
    USE SIGNAL ;
    PORT
      LAYER M4 ;
        RECT  0 49.104 0.084 49.128 ;
    END
  END cfg_data[67]
  PIN cfg_data[68]
    DIRECTION INPUT ;
    USE SIGNAL ;
    PORT
      LAYER M4 ;
        RECT  0 49.2 0.084 49.224 ;
    END
  END cfg_data[68]
  PIN cfg_data[69]
    DIRECTION INPUT ;
    USE SIGNAL ;
    PORT
      LAYER M4 ;
        RECT  0 49.296 0.084 49.32 ;
    END
  END cfg_data[69]
  PIN cfg_data[6]
    DIRECTION INPUT ;
    USE SIGNAL ;
    PORT
      LAYER M4 ;
        RECT  0 52.464 0.084 52.488 ;
    END
  END cfg_data[6]
  PIN cfg_data[70]
    DIRECTION INPUT ;
    USE SIGNAL ;
    PORT
      LAYER M4 ;
        RECT  0 49.392 0.084 49.416 ;
    END
  END cfg_data[70]
  PIN cfg_data[71]
    DIRECTION INPUT ;
    USE SIGNAL ;
    PORT
      LAYER M4 ;
        RECT  0 49.488 0.084 49.512 ;
    END
  END cfg_data[71]
  PIN cfg_data[72]
    DIRECTION INPUT ;
    USE SIGNAL ;
    PORT
      LAYER M4 ;
        RECT  0 49.584 0.084 49.608 ;
    END
  END cfg_data[72]
  PIN cfg_data[73]
    DIRECTION INPUT ;
    USE SIGNAL ;
    PORT
      LAYER M4 ;
        RECT  0 49.68 0.084 49.704 ;
    END
  END cfg_data[73]
  PIN cfg_data[74]
    DIRECTION INPUT ;
    USE SIGNAL ;
    PORT
      LAYER M4 ;
        RECT  0 49.776 0.084 49.8 ;
    END
  END cfg_data[74]
  PIN cfg_data[75]
    DIRECTION INPUT ;
    USE SIGNAL ;
    PORT
      LAYER M4 ;
        RECT  0 49.872 0.084 49.896 ;
    END
  END cfg_data[75]
  PIN cfg_data[76]
    DIRECTION INPUT ;
    USE SIGNAL ;
    PORT
      LAYER M4 ;
        RECT  0 49.968 0.084 49.992 ;
    END
  END cfg_data[76]
  PIN cfg_data[77]
    DIRECTION INPUT ;
    USE SIGNAL ;
    PORT
      LAYER M4 ;
        RECT  0 50.064 0.084 50.088 ;
    END
  END cfg_data[77]
  PIN cfg_data[78]
    DIRECTION INPUT ;
    USE SIGNAL ;
    PORT
      LAYER M4 ;
        RECT  0 50.16 0.084 50.184 ;
    END
  END cfg_data[78]
  PIN cfg_data[79]
    DIRECTION INPUT ;
    USE SIGNAL ;
    PORT
      LAYER M4 ;
        RECT  0 50.256 0.084 50.28 ;
    END
  END cfg_data[79]
  PIN cfg_data[7]
    DIRECTION INPUT ;
    USE SIGNAL ;
    PORT
      LAYER M4 ;
        RECT  0 52.56 0.084 52.584 ;
    END
  END cfg_data[7]
  PIN cfg_data[80]
    DIRECTION INPUT ;
    USE SIGNAL ;
    PORT
      LAYER M4 ;
        RECT  0 50.352 0.084 50.376 ;
    END
  END cfg_data[80]
  PIN cfg_data[81]
    DIRECTION INPUT ;
    USE SIGNAL ;
    PORT
      LAYER M4 ;
        RECT  0 50.448 0.084 50.472 ;
    END
  END cfg_data[81]
  PIN cfg_data[82]
    DIRECTION INPUT ;
    USE SIGNAL ;
    PORT
      LAYER M4 ;
        RECT  0 50.544 0.084 50.568 ;
    END
  END cfg_data[82]
  PIN cfg_data[83]
    DIRECTION INPUT ;
    USE SIGNAL ;
    PORT
      LAYER M4 ;
        RECT  0 50.64 0.084 50.664 ;
    END
  END cfg_data[83]
  PIN cfg_data[84]
    DIRECTION INPUT ;
    USE SIGNAL ;
    PORT
      LAYER M4 ;
        RECT  0 50.736 0.084 50.76 ;
    END
  END cfg_data[84]
  PIN cfg_data[85]
    DIRECTION INPUT ;
    USE SIGNAL ;
    PORT
      LAYER M4 ;
        RECT  0 50.832 0.084 50.856 ;
    END
  END cfg_data[85]
  PIN cfg_data[86]
    DIRECTION INPUT ;
    USE SIGNAL ;
    PORT
      LAYER M4 ;
        RECT  0 50.928 0.084 50.952 ;
    END
  END cfg_data[86]
  PIN cfg_data[87]
    DIRECTION INPUT ;
    USE SIGNAL ;
    PORT
      LAYER M4 ;
        RECT  0 51.024 0.084 51.048 ;
    END
  END cfg_data[87]
  PIN cfg_data[88]
    DIRECTION INPUT ;
    USE SIGNAL ;
    PORT
      LAYER M4 ;
        RECT  0 51.12 0.084 51.144 ;
    END
  END cfg_data[88]
  PIN cfg_data[89]
    DIRECTION INPUT ;
    USE SIGNAL ;
    PORT
      LAYER M4 ;
        RECT  0 51.216 0.084 51.24 ;
    END
  END cfg_data[89]
  PIN cfg_data[8]
    DIRECTION INPUT ;
    USE SIGNAL ;
    PORT
      LAYER M4 ;
        RECT  0 52.656 0.084 52.68 ;
    END
  END cfg_data[8]
  PIN cfg_data[90]
    DIRECTION INPUT ;
    USE SIGNAL ;
    PORT
      LAYER M4 ;
        RECT  0 51.312 0.084 51.336 ;
    END
  END cfg_data[90]
  PIN cfg_data[91]
    DIRECTION INPUT ;
    USE SIGNAL ;
    PORT
      LAYER M4 ;
        RECT  0 51.408 0.084 51.432 ;
    END
  END cfg_data[91]
  PIN cfg_data[92]
    DIRECTION INPUT ;
    USE SIGNAL ;
    PORT
      LAYER M4 ;
        RECT  0 51.504 0.084 51.528 ;
    END
  END cfg_data[92]
  PIN cfg_data[93]
    DIRECTION INPUT ;
    USE SIGNAL ;
    PORT
      LAYER M4 ;
        RECT  0 51.6 0.084 51.624 ;
    END
  END cfg_data[93]
  PIN cfg_data[94]
    DIRECTION INPUT ;
    USE SIGNAL ;
    PORT
      LAYER M4 ;
        RECT  0 51.696 0.084 51.72 ;
    END
  END cfg_data[94]
  PIN cfg_data[95]
    DIRECTION INPUT ;
    USE SIGNAL ;
    PORT
      LAYER M4 ;
        RECT  0 51.792 0.084 51.816 ;
    END
  END cfg_data[95]
  PIN cfg_data[96]
    DIRECTION INPUT ;
    USE SIGNAL ;
    PORT
      LAYER M4 ;
        RECT  0 54.96 0.084 54.984 ;
    END
  END cfg_data[96]
  PIN cfg_data[97]
    DIRECTION INPUT ;
    USE SIGNAL ;
    PORT
      LAYER M4 ;
        RECT  0 55.056 0.084 55.08 ;
    END
  END cfg_data[97]
  PIN cfg_data[98]
    DIRECTION INPUT ;
    USE SIGNAL ;
    PORT
      LAYER M4 ;
        RECT  0 55.152 0.084 55.176 ;
    END
  END cfg_data[98]
  PIN cfg_data[99]
    DIRECTION INPUT ;
    USE SIGNAL ;
    PORT
      LAYER M4 ;
        RECT  0 55.248 0.084 55.272 ;
    END
  END cfg_data[99]
  PIN cfg_data[9]
    DIRECTION INPUT ;
    USE SIGNAL ;
    PORT
      LAYER M4 ;
        RECT  0 52.752 0.084 52.776 ;
    END
  END cfg_data[9]
  PIN cfg_row[0]
    DIRECTION INPUT ;
    USE SIGNAL ;
    PORT
      LAYER M4 ;
        RECT  0 68.688 0.084 68.712 ;
    END
  END cfg_row[0]
  PIN cfg_row[1]
    DIRECTION INPUT ;
    USE SIGNAL ;
    PORT
      LAYER M4 ;
        RECT  0 68.784 0.084 68.808 ;
    END
  END cfg_row[1]
  PIN cfg_row[2]
    DIRECTION INPUT ;
    USE SIGNAL ;
    PORT
      LAYER M4 ;
        RECT  0 68.88 0.084 68.904 ;
    END
  END cfg_row[2]
  PIN cfg_row[3]
    DIRECTION INPUT ;
    USE SIGNAL ;
    PORT
      LAYER M4 ;
        RECT  0 68.976 0.084 69 ;
    END
  END cfg_row[3]
  PIN cfg_row[4]
    DIRECTION INPUT ;
    USE SIGNAL ;
    PORT
      LAYER M4 ;
        RECT  0 69.072 0.084 69.096 ;
    END
  END cfg_row[4]
  PIN cfg_row[5]
    DIRECTION INPUT ;
    USE SIGNAL ;
    PORT
      LAYER M4 ;
        RECT  0 69.168 0.084 69.192 ;
    END
  END cfg_row[5]
  PIN cfg_row[6]
    DIRECTION INPUT ;
    USE SIGNAL ;
    PORT
      LAYER M4 ;
        RECT  0 69.264 0.084 69.288 ;
    END
  END cfg_row[6]
  PIN cfg_we
    DIRECTION INPUT ;
    USE SIGNAL ;
    PORT
      LAYER M4 ;
        RECT  0 72.528 0.084 72.552 ;
    END
    PORT
      LAYER M4 ;
        RECT  0.06 72.528 0.137 72.552 ;
    END
  END cfg_we
  PIN clk
    DIRECTION INPUT ;
    USE SIGNAL ;
    PORT
      LAYER M4 ;
        RECT  0 58.512 0.084 58.536 ;
    END
  END clk
  PIN fault
    DIRECTION OUTPUT ;
    USE SIGNAL ;
    PORT
      LAYER M4 ;
        RECT  86.316 83.76 86.4 83.784 ;
    END
    PORT
      LAYER M4 ;
        RECT  84.877 83.76 86.364 83.784 ;
    END
  END fault
  PIN length[0]
    DIRECTION INPUT ;
    USE SIGNAL ;
    PORT
      LAYER M4 ;
        RECT  0 77.424 0.084 77.448 ;
    END
  END length[0]
  PIN length[10]
    DIRECTION INPUT ;
    USE SIGNAL ;
    PORT
      LAYER M4 ;
        RECT  0 78.384 0.084 78.408 ;
    END
  END length[10]
  PIN length[11]
    DIRECTION INPUT ;
    USE SIGNAL ;
    PORT
      LAYER M4 ;
        RECT  0 78.48 0.084 78.504 ;
    END
  END length[11]
  PIN length[12]
    DIRECTION INPUT ;
    USE SIGNAL ;
    PORT
      LAYER M4 ;
        RECT  0 78.576 0.084 78.6 ;
    END
  END length[12]
  PIN length[13]
    DIRECTION INPUT ;
    USE SIGNAL ;
    PORT
      LAYER M4 ;
        RECT  0 78.672 0.084 78.696 ;
    END
  END length[13]
  PIN length[14]
    DIRECTION INPUT ;
    USE SIGNAL ;
    PORT
      LAYER M4 ;
        RECT  0 78.768 0.084 78.792 ;
    END
  END length[14]
  PIN length[15]
    DIRECTION INPUT ;
    USE SIGNAL ;
    PORT
      LAYER M4 ;
        RECT  0 78.864 0.084 78.888 ;
    END
  END length[15]
  PIN length[1]
    DIRECTION INPUT ;
    USE SIGNAL ;
    PORT
      LAYER M4 ;
        RECT  0 77.52 0.084 77.544 ;
    END
  END length[1]
  PIN length[2]
    DIRECTION INPUT ;
    USE SIGNAL ;
    PORT
      LAYER M4 ;
        RECT  0 77.616 0.084 77.64 ;
    END
  END length[2]
  PIN length[3]
    DIRECTION INPUT ;
    USE SIGNAL ;
    PORT
      LAYER M4 ;
        RECT  0 77.712 0.084 77.736 ;
    END
  END length[3]
  PIN length[4]
    DIRECTION INPUT ;
    USE SIGNAL ;
    PORT
      LAYER M4 ;
        RECT  0 77.808 0.084 77.832 ;
    END
  END length[4]
  PIN length[5]
    DIRECTION INPUT ;
    USE SIGNAL ;
    PORT
      LAYER M4 ;
        RECT  0 77.904 0.084 77.928 ;
    END
  END length[5]
  PIN length[6]
    DIRECTION INPUT ;
    USE SIGNAL ;
    PORT
      LAYER M4 ;
        RECT  0 78 0.084 78.024 ;
    END
  END length[6]
  PIN length[7]
    DIRECTION INPUT ;
    USE SIGNAL ;
    PORT
      LAYER M4 ;
        RECT  0 78.096 0.084 78.12 ;
    END
  END length[7]
  PIN length[8]
    DIRECTION INPUT ;
    USE SIGNAL ;
    PORT
      LAYER M4 ;
        RECT  0 78.192 0.084 78.216 ;
    END
  END length[8]
  PIN length[9]
    DIRECTION INPUT ;
    USE SIGNAL ;
    PORT
      LAYER M4 ;
        RECT  0 78.288 0.084 78.312 ;
    END
  END length[9]
  PIN p_fault[0]
    DIRECTION INPUT ;
    USE SIGNAL ;
    PORT
      LAYER M4 ;
        RECT  0 82.512 0.084 82.536 ;
    END
  END p_fault[0]
  PIN p_fault[1]
    DIRECTION INPUT ;
    USE SIGNAL ;
    PORT
      LAYER M4 ;
        RECT  0 82.608 0.084 82.632 ;
    END
  END p_fault[1]
  PIN p_fault[2]
    DIRECTION INPUT ;
    USE SIGNAL ;
    PORT
      LAYER M4 ;
        RECT  0 82.704 0.084 82.728 ;
    END
  END p_fault[2]
  PIN p_fault[3]
    DIRECTION INPUT ;
    USE SIGNAL ;
    PORT
      LAYER M4 ;
        RECT  0 82.8 0.084 82.824 ;
    END
  END p_fault[3]
  PIN r_bank[0]
    DIRECTION OUTPUT ;
    USE SIGNAL ;
    PORT
      LAYER M4 ;
        RECT  86.316 63.6 86.4 63.624 ;
    END
  END r_bank[0]
  PIN r_bank[10]
    DIRECTION OUTPUT ;
    USE SIGNAL ;
    PORT
      LAYER M4 ;
        RECT  86.316 64.56 86.4 64.584 ;
    END
  END r_bank[10]
  PIN r_bank[11]
    DIRECTION OUTPUT ;
    USE SIGNAL ;
    PORT
      LAYER M4 ;
        RECT  86.316 64.656 86.4 64.68 ;
    END
  END r_bank[11]
  PIN r_bank[12]
    DIRECTION OUTPUT ;
    USE SIGNAL ;
    PORT
      LAYER M4 ;
        RECT  86.316 64.752 86.4 64.776 ;
    END
  END r_bank[12]
  PIN r_bank[13]
    DIRECTION OUTPUT ;
    USE SIGNAL ;
    PORT
      LAYER M4 ;
        RECT  86.316 64.848 86.4 64.872 ;
    END
  END r_bank[13]
  PIN r_bank[14]
    DIRECTION OUTPUT ;
    USE SIGNAL ;
    PORT
      LAYER M4 ;
        RECT  86.316 64.944 86.4 64.968 ;
    END
  END r_bank[14]
  PIN r_bank[15]
    DIRECTION OUTPUT ;
    USE SIGNAL ;
    PORT
      LAYER M4 ;
        RECT  86.316 65.04 86.4 65.064 ;
    END
  END r_bank[15]
  PIN r_bank[16]
    DIRECTION OUTPUT ;
    USE SIGNAL ;
    PORT
      LAYER M4 ;
        RECT  86.316 65.136 86.4 65.16 ;
    END
  END r_bank[16]
  PIN r_bank[17]
    DIRECTION OUTPUT ;
    USE SIGNAL ;
    PORT
      LAYER M4 ;
        RECT  86.316 65.232 86.4 65.256 ;
    END
  END r_bank[17]
  PIN r_bank[18]
    DIRECTION OUTPUT ;
    USE SIGNAL ;
    PORT
      LAYER M4 ;
        RECT  86.316 65.328 86.4 65.352 ;
    END
  END r_bank[18]
  PIN r_bank[19]
    DIRECTION OUTPUT ;
    USE SIGNAL ;
    PORT
      LAYER M4 ;
        RECT  86.316 65.424 86.4 65.448 ;
    END
  END r_bank[19]
  PIN r_bank[1]
    DIRECTION OUTPUT ;
    USE SIGNAL ;
    PORT
      LAYER M4 ;
        RECT  86.316 63.696 86.4 63.72 ;
    END
  END r_bank[1]
  PIN r_bank[20]
    DIRECTION OUTPUT ;
    USE SIGNAL ;
    PORT
      LAYER M4 ;
        RECT  86.316 65.52 86.4 65.544 ;
    END
  END r_bank[20]
  PIN r_bank[21]
    DIRECTION OUTPUT ;
    USE SIGNAL ;
    PORT
      LAYER M4 ;
        RECT  86.316 65.616 86.4 65.64 ;
    END
  END r_bank[21]
  PIN r_bank[22]
    DIRECTION OUTPUT ;
    USE SIGNAL ;
    PORT
      LAYER M4 ;
        RECT  86.316 65.712 86.4 65.736 ;
    END
  END r_bank[22]
  PIN r_bank[23]
    DIRECTION OUTPUT ;
    USE SIGNAL ;
    PORT
      LAYER M4 ;
        RECT  86.316 65.808 86.4 65.832 ;
    END
  END r_bank[23]
  PIN r_bank[24]
    DIRECTION OUTPUT ;
    USE SIGNAL ;
    PORT
      LAYER M4 ;
        RECT  86.316 65.904 86.4 65.928 ;
    END
  END r_bank[24]
  PIN r_bank[25]
    DIRECTION OUTPUT ;
    USE SIGNAL ;
    PORT
      LAYER M4 ;
        RECT  86.316 66 86.4 66.024 ;
    END
  END r_bank[25]
  PIN r_bank[26]
    DIRECTION OUTPUT ;
    USE SIGNAL ;
    PORT
      LAYER M4 ;
        RECT  86.316 66.096 86.4 66.12 ;
    END
  END r_bank[26]
  PIN r_bank[27]
    DIRECTION OUTPUT ;
    USE SIGNAL ;
    PORT
      LAYER M4 ;
        RECT  86.316 66.192 86.4 66.216 ;
    END
  END r_bank[27]
  PIN r_bank[28]
    DIRECTION OUTPUT ;
    USE SIGNAL ;
    PORT
      LAYER M4 ;
        RECT  86.316 66.288 86.4 66.312 ;
    END
  END r_bank[28]
  PIN r_bank[29]
    DIRECTION OUTPUT ;
    USE SIGNAL ;
    PORT
      LAYER M4 ;
        RECT  86.316 66.384 86.4 66.408 ;
    END
  END r_bank[29]
  PIN r_bank[2]
    DIRECTION OUTPUT ;
    USE SIGNAL ;
    PORT
      LAYER M4 ;
        RECT  86.316 63.792 86.4 63.816 ;
    END
  END r_bank[2]
  PIN r_bank[30]
    DIRECTION OUTPUT ;
    USE SIGNAL ;
    PORT
      LAYER M4 ;
        RECT  86.316 66.48 86.4 66.504 ;
    END
  END r_bank[30]
  PIN r_bank[31]
    DIRECTION OUTPUT ;
    USE SIGNAL ;
    PORT
      LAYER M4 ;
        RECT  86.316 66.576 86.4 66.6 ;
    END
  END r_bank[31]
  PIN r_bank[32]
    DIRECTION OUTPUT ;
    USE SIGNAL ;
    PORT
      LAYER M4 ;
        RECT  86.316 60.528 86.4 60.552 ;
    END
  END r_bank[32]
  PIN r_bank[33]
    DIRECTION OUTPUT ;
    USE SIGNAL ;
    PORT
      LAYER M4 ;
        RECT  86.316 60.624 86.4 60.648 ;
    END
  END r_bank[33]
  PIN r_bank[34]
    DIRECTION OUTPUT ;
    USE SIGNAL ;
    PORT
      LAYER M4 ;
        RECT  86.316 60.72 86.4 60.744 ;
    END
  END r_bank[34]
  PIN r_bank[35]
    DIRECTION OUTPUT ;
    USE SIGNAL ;
    PORT
      LAYER M4 ;
        RECT  86.316 60.816 86.4 60.84 ;
    END
  END r_bank[35]
  PIN r_bank[36]
    DIRECTION OUTPUT ;
    USE SIGNAL ;
    PORT
      LAYER M4 ;
        RECT  86.316 60.912 86.4 60.936 ;
    END
  END r_bank[36]
  PIN r_bank[37]
    DIRECTION OUTPUT ;
    USE SIGNAL ;
    PORT
      LAYER M4 ;
        RECT  86.316 61.008 86.4 61.032 ;
    END
  END r_bank[37]
  PIN r_bank[38]
    DIRECTION OUTPUT ;
    USE SIGNAL ;
    PORT
      LAYER M4 ;
        RECT  86.316 61.104 86.4 61.128 ;
    END
  END r_bank[38]
  PIN r_bank[39]
    DIRECTION OUTPUT ;
    USE SIGNAL ;
    PORT
      LAYER M4 ;
        RECT  86.316 61.2 86.4 61.224 ;
    END
  END r_bank[39]
  PIN r_bank[3]
    DIRECTION OUTPUT ;
    USE SIGNAL ;
    PORT
      LAYER M4 ;
        RECT  86.316 63.888 86.4 63.912 ;
    END
  END r_bank[3]
  PIN r_bank[40]
    DIRECTION OUTPUT ;
    USE SIGNAL ;
    PORT
      LAYER M4 ;
        RECT  86.316 61.296 86.4 61.32 ;
    END
  END r_bank[40]
  PIN r_bank[41]
    DIRECTION OUTPUT ;
    USE SIGNAL ;
    PORT
      LAYER M4 ;
        RECT  86.316 61.392 86.4 61.416 ;
    END
  END r_bank[41]
  PIN r_bank[42]
    DIRECTION OUTPUT ;
    USE SIGNAL ;
    PORT
      LAYER M4 ;
        RECT  86.316 61.488 86.4 61.512 ;
    END
  END r_bank[42]
  PIN r_bank[43]
    DIRECTION OUTPUT ;
    USE SIGNAL ;
    PORT
      LAYER M4 ;
        RECT  86.316 61.584 86.4 61.608 ;
    END
  END r_bank[43]
  PIN r_bank[44]
    DIRECTION OUTPUT ;
    USE SIGNAL ;
    PORT
      LAYER M4 ;
        RECT  86.316 61.68 86.4 61.704 ;
    END
  END r_bank[44]
  PIN r_bank[45]
    DIRECTION OUTPUT ;
    USE SIGNAL ;
    PORT
      LAYER M4 ;
        RECT  86.316 61.776 86.4 61.8 ;
    END
  END r_bank[45]
  PIN r_bank[46]
    DIRECTION OUTPUT ;
    USE SIGNAL ;
    PORT
      LAYER M4 ;
        RECT  86.316 61.872 86.4 61.896 ;
    END
  END r_bank[46]
  PIN r_bank[47]
    DIRECTION OUTPUT ;
    USE SIGNAL ;
    PORT
      LAYER M4 ;
        RECT  86.316 61.968 86.4 61.992 ;
    END
  END r_bank[47]
  PIN r_bank[48]
    DIRECTION OUTPUT ;
    USE SIGNAL ;
    PORT
      LAYER M4 ;
        RECT  86.316 62.064 86.4 62.088 ;
    END
  END r_bank[48]
  PIN r_bank[49]
    DIRECTION OUTPUT ;
    USE SIGNAL ;
    PORT
      LAYER M4 ;
        RECT  86.316 62.16 86.4 62.184 ;
    END
  END r_bank[49]
  PIN r_bank[4]
    DIRECTION OUTPUT ;
    USE SIGNAL ;
    PORT
      LAYER M4 ;
        RECT  86.316 63.984 86.4 64.008 ;
    END
  END r_bank[4]
  PIN r_bank[50]
    DIRECTION OUTPUT ;
    USE SIGNAL ;
    PORT
      LAYER M4 ;
        RECT  86.316 62.256 86.4 62.28 ;
    END
  END r_bank[50]
  PIN r_bank[51]
    DIRECTION OUTPUT ;
    USE SIGNAL ;
    PORT
      LAYER M4 ;
        RECT  86.316 62.352 86.4 62.376 ;
    END
  END r_bank[51]
  PIN r_bank[52]
    DIRECTION OUTPUT ;
    USE SIGNAL ;
    PORT
      LAYER M4 ;
        RECT  86.316 62.448 86.4 62.472 ;
    END
  END r_bank[52]
  PIN r_bank[53]
    DIRECTION OUTPUT ;
    USE SIGNAL ;
    PORT
      LAYER M4 ;
        RECT  86.316 62.544 86.4 62.568 ;
    END
  END r_bank[53]
  PIN r_bank[54]
    DIRECTION OUTPUT ;
    USE SIGNAL ;
    PORT
      LAYER M4 ;
        RECT  86.316 62.64 86.4 62.664 ;
    END
  END r_bank[54]
  PIN r_bank[55]
    DIRECTION OUTPUT ;
    USE SIGNAL ;
    PORT
      LAYER M4 ;
        RECT  86.316 62.736 86.4 62.76 ;
    END
  END r_bank[55]
  PIN r_bank[56]
    DIRECTION OUTPUT ;
    USE SIGNAL ;
    PORT
      LAYER M4 ;
        RECT  86.316 62.832 86.4 62.856 ;
    END
  END r_bank[56]
  PIN r_bank[57]
    DIRECTION OUTPUT ;
    USE SIGNAL ;
    PORT
      LAYER M4 ;
        RECT  86.316 62.928 86.4 62.952 ;
    END
  END r_bank[57]
  PIN r_bank[58]
    DIRECTION OUTPUT ;
    USE SIGNAL ;
    PORT
      LAYER M4 ;
        RECT  86.316 63.024 86.4 63.048 ;
    END
  END r_bank[58]
  PIN r_bank[59]
    DIRECTION OUTPUT ;
    USE SIGNAL ;
    PORT
      LAYER M4 ;
        RECT  86.316 63.12 86.4 63.144 ;
    END
  END r_bank[59]
  PIN r_bank[5]
    DIRECTION OUTPUT ;
    USE SIGNAL ;
    PORT
      LAYER M4 ;
        RECT  86.316 64.08 86.4 64.104 ;
    END
  END r_bank[5]
  PIN r_bank[60]
    DIRECTION OUTPUT ;
    USE SIGNAL ;
    PORT
      LAYER M4 ;
        RECT  86.316 63.216 86.4 63.24 ;
    END
  END r_bank[60]
  PIN r_bank[61]
    DIRECTION OUTPUT ;
    USE SIGNAL ;
    PORT
      LAYER M4 ;
        RECT  86.316 63.312 86.4 63.336 ;
    END
  END r_bank[61]
  PIN r_bank[62]
    DIRECTION OUTPUT ;
    USE SIGNAL ;
    PORT
      LAYER M4 ;
        RECT  86.316 63.408 86.4 63.432 ;
    END
  END r_bank[62]
  PIN r_bank[63]
    DIRECTION OUTPUT ;
    USE SIGNAL ;
    PORT
      LAYER M4 ;
        RECT  86.316 63.504 86.4 63.528 ;
    END
  END r_bank[63]
  PIN r_bank[6]
    DIRECTION OUTPUT ;
    USE SIGNAL ;
    PORT
      LAYER M4 ;
        RECT  86.316 64.176 86.4 64.2 ;
    END
  END r_bank[6]
  PIN r_bank[7]
    DIRECTION OUTPUT ;
    USE SIGNAL ;
    PORT
      LAYER M4 ;
        RECT  86.316 64.272 86.4 64.296 ;
    END
  END r_bank[7]
  PIN r_bank[8]
    DIRECTION OUTPUT ;
    USE SIGNAL ;
    PORT
      LAYER M4 ;
        RECT  86.316 64.368 86.4 64.392 ;
    END
  END r_bank[8]
  PIN r_bank[9]
    DIRECTION OUTPUT ;
    USE SIGNAL ;
    PORT
      LAYER M4 ;
        RECT  86.316 64.464 86.4 64.488 ;
    END
  END r_bank[9]
  PIN r_data[0]
    DIRECTION OUTPUT ;
    USE SIGNAL ;
    PORT
      LAYER M4 ;
        RECT  86.316 52.752 86.4 52.776 ;
    END
  END r_data[0]
  PIN r_data[100]
    DIRECTION OUTPUT ;
    USE SIGNAL ;
    PORT
      LAYER M4 ;
        RECT  86.316 56.208 86.4 56.232 ;
    END
  END r_data[100]
  PIN r_data[101]
    DIRECTION OUTPUT ;
    USE SIGNAL ;
    PORT
      LAYER M4 ;
        RECT  86.316 56.304 86.4 56.328 ;
    END
  END r_data[101]
  PIN r_data[102]
    DIRECTION OUTPUT ;
    USE SIGNAL ;
    PORT
      LAYER M4 ;
        RECT  86.316 56.4 86.4 56.424 ;
    END
  END r_data[102]
  PIN r_data[103]
    DIRECTION OUTPUT ;
    USE SIGNAL ;
    PORT
      LAYER M4 ;
        RECT  86.316 56.496 86.4 56.52 ;
    END
  END r_data[103]
  PIN r_data[104]
    DIRECTION OUTPUT ;
    USE SIGNAL ;
    PORT
      LAYER M4 ;
        RECT  86.316 56.592 86.4 56.616 ;
    END
  END r_data[104]
  PIN r_data[105]
    DIRECTION OUTPUT ;
    USE SIGNAL ;
    PORT
      LAYER M4 ;
        RECT  86.316 56.688 86.4 56.712 ;
    END
  END r_data[105]
  PIN r_data[106]
    DIRECTION OUTPUT ;
    USE SIGNAL ;
    PORT
      LAYER M4 ;
        RECT  86.316 56.784 86.4 56.808 ;
    END
  END r_data[106]
  PIN r_data[107]
    DIRECTION OUTPUT ;
    USE SIGNAL ;
    PORT
      LAYER M4 ;
        RECT  86.316 56.88 86.4 56.904 ;
    END
  END r_data[107]
  PIN r_data[108]
    DIRECTION OUTPUT ;
    USE SIGNAL ;
    PORT
      LAYER M4 ;
        RECT  86.316 56.976 86.4 57 ;
    END
  END r_data[108]
  PIN r_data[109]
    DIRECTION OUTPUT ;
    USE SIGNAL ;
    PORT
      LAYER M4 ;
        RECT  86.316 57.072 86.4 57.096 ;
    END
  END r_data[109]
  PIN r_data[10]
    DIRECTION OUTPUT ;
    USE SIGNAL ;
    PORT
      LAYER M4 ;
        RECT  86.316 53.712 86.4 53.736 ;
    END
  END r_data[10]
  PIN r_data[110]
    DIRECTION OUTPUT ;
    USE SIGNAL ;
    PORT
      LAYER M4 ;
        RECT  86.316 57.168 86.4 57.192 ;
    END
  END r_data[110]
  PIN r_data[111]
    DIRECTION OUTPUT ;
    USE SIGNAL ;
    PORT
      LAYER M4 ;
        RECT  86.316 57.264 86.4 57.288 ;
    END
  END r_data[111]
  PIN r_data[112]
    DIRECTION OUTPUT ;
    USE SIGNAL ;
    PORT
      LAYER M4 ;
        RECT  86.316 57.36 86.4 57.384 ;
    END
  END r_data[112]
  PIN r_data[113]
    DIRECTION OUTPUT ;
    USE SIGNAL ;
    PORT
      LAYER M4 ;
        RECT  86.316 57.456 86.4 57.48 ;
    END
  END r_data[113]
  PIN r_data[114]
    DIRECTION OUTPUT ;
    USE SIGNAL ;
    PORT
      LAYER M4 ;
        RECT  86.316 57.552 86.4 57.576 ;
    END
  END r_data[114]
  PIN r_data[115]
    DIRECTION OUTPUT ;
    USE SIGNAL ;
    PORT
      LAYER M4 ;
        RECT  86.316 57.648 86.4 57.672 ;
    END
  END r_data[115]
  PIN r_data[116]
    DIRECTION OUTPUT ;
    USE SIGNAL ;
    PORT
      LAYER M4 ;
        RECT  86.316 57.744 86.4 57.768 ;
    END
  END r_data[116]
  PIN r_data[117]
    DIRECTION OUTPUT ;
    USE SIGNAL ;
    PORT
      LAYER M4 ;
        RECT  86.316 57.84 86.4 57.864 ;
    END
  END r_data[117]
  PIN r_data[118]
    DIRECTION OUTPUT ;
    USE SIGNAL ;
    PORT
      LAYER M4 ;
        RECT  86.316 57.936 86.4 57.96 ;
    END
  END r_data[118]
  PIN r_data[119]
    DIRECTION OUTPUT ;
    USE SIGNAL ;
    PORT
      LAYER M4 ;
        RECT  86.316 58.032 86.4 58.056 ;
    END
  END r_data[119]
  PIN r_data[11]
    DIRECTION OUTPUT ;
    USE SIGNAL ;
    PORT
      LAYER M4 ;
        RECT  86.316 53.808 86.4 53.832 ;
    END
  END r_data[11]
  PIN r_data[120]
    DIRECTION OUTPUT ;
    USE SIGNAL ;
    PORT
      LAYER M4 ;
        RECT  86.316 58.128 86.4 58.152 ;
    END
  END r_data[120]
  PIN r_data[121]
    DIRECTION OUTPUT ;
    USE SIGNAL ;
    PORT
      LAYER M4 ;
        RECT  86.316 58.224 86.4 58.248 ;
    END
  END r_data[121]
  PIN r_data[122]
    DIRECTION OUTPUT ;
    USE SIGNAL ;
    PORT
      LAYER M4 ;
        RECT  86.316 58.32 86.4 58.344 ;
    END
  END r_data[122]
  PIN r_data[123]
    DIRECTION OUTPUT ;
    USE SIGNAL ;
    PORT
      LAYER M4 ;
        RECT  86.316 58.416 86.4 58.44 ;
    END
  END r_data[123]
  PIN r_data[124]
    DIRECTION OUTPUT ;
    USE SIGNAL ;
    PORT
      LAYER M4 ;
        RECT  86.316 58.512 86.4 58.536 ;
    END
  END r_data[124]
  PIN r_data[125]
    DIRECTION OUTPUT ;
    USE SIGNAL ;
    PORT
      LAYER M4 ;
        RECT  86.316 58.608 86.4 58.632 ;
    END
  END r_data[125]
  PIN r_data[126]
    DIRECTION OUTPUT ;
    USE SIGNAL ;
    PORT
      LAYER M4 ;
        RECT  86.316 58.704 86.4 58.728 ;
    END
  END r_data[126]
  PIN r_data[127]
    DIRECTION OUTPUT ;
    USE SIGNAL ;
    PORT
      LAYER M4 ;
        RECT  86.316 58.8 86.4 58.824 ;
    END
  END r_data[127]
  PIN r_data[128]
    DIRECTION OUTPUT ;
    USE SIGNAL ;
    PORT
      LAYER M4 ;
        RECT  86.316 43.536 86.4 43.56 ;
    END
  END r_data[128]
  PIN r_data[129]
    DIRECTION OUTPUT ;
    USE SIGNAL ;
    PORT
      LAYER M4 ;
        RECT  86.316 43.632 86.4 43.656 ;
    END
  END r_data[129]
  PIN r_data[12]
    DIRECTION OUTPUT ;
    USE SIGNAL ;
    PORT
      LAYER M4 ;
        RECT  86.316 53.904 86.4 53.928 ;
    END
  END r_data[12]
  PIN r_data[130]
    DIRECTION OUTPUT ;
    USE SIGNAL ;
    PORT
      LAYER M4 ;
        RECT  86.316 43.728 86.4 43.752 ;
    END
  END r_data[130]
  PIN r_data[131]
    DIRECTION OUTPUT ;
    USE SIGNAL ;
    PORT
      LAYER M4 ;
        RECT  86.316 43.824 86.4 43.848 ;
    END
  END r_data[131]
  PIN r_data[132]
    DIRECTION OUTPUT ;
    USE SIGNAL ;
    PORT
      LAYER M4 ;
        RECT  86.316 43.92 86.4 43.944 ;
    END
  END r_data[132]
  PIN r_data[133]
    DIRECTION OUTPUT ;
    USE SIGNAL ;
    PORT
      LAYER M4 ;
        RECT  86.316 44.016 86.4 44.04 ;
    END
  END r_data[133]
  PIN r_data[134]
    DIRECTION OUTPUT ;
    USE SIGNAL ;
    PORT
      LAYER M4 ;
        RECT  86.316 44.112 86.4 44.136 ;
    END
  END r_data[134]
  PIN r_data[135]
    DIRECTION OUTPUT ;
    USE SIGNAL ;
    PORT
      LAYER M4 ;
        RECT  86.316 44.208 86.4 44.232 ;
    END
  END r_data[135]
  PIN r_data[136]
    DIRECTION OUTPUT ;
    USE SIGNAL ;
    PORT
      LAYER M4 ;
        RECT  86.316 44.304 86.4 44.328 ;
    END
  END r_data[136]
  PIN r_data[137]
    DIRECTION OUTPUT ;
    USE SIGNAL ;
    PORT
      LAYER M4 ;
        RECT  86.316 44.4 86.4 44.424 ;
    END
  END r_data[137]
  PIN r_data[138]
    DIRECTION OUTPUT ;
    USE SIGNAL ;
    PORT
      LAYER M4 ;
        RECT  86.316 44.496 86.4 44.52 ;
    END
  END r_data[138]
  PIN r_data[139]
    DIRECTION OUTPUT ;
    USE SIGNAL ;
    PORT
      LAYER M4 ;
        RECT  86.316 44.592 86.4 44.616 ;
    END
  END r_data[139]
  PIN r_data[13]
    DIRECTION OUTPUT ;
    USE SIGNAL ;
    PORT
      LAYER M4 ;
        RECT  86.316 54 86.4 54.024 ;
    END
  END r_data[13]
  PIN r_data[140]
    DIRECTION OUTPUT ;
    USE SIGNAL ;
    PORT
      LAYER M4 ;
        RECT  86.316 44.688 86.4 44.712 ;
    END
  END r_data[140]
  PIN r_data[141]
    DIRECTION OUTPUT ;
    USE SIGNAL ;
    PORT
      LAYER M4 ;
        RECT  86.316 44.784 86.4 44.808 ;
    END
  END r_data[141]
  PIN r_data[142]
    DIRECTION OUTPUT ;
    USE SIGNAL ;
    PORT
      LAYER M4 ;
        RECT  86.316 44.88 86.4 44.904 ;
    END
  END r_data[142]
  PIN r_data[143]
    DIRECTION OUTPUT ;
    USE SIGNAL ;
    PORT
      LAYER M4 ;
        RECT  86.316 44.976 86.4 45 ;
    END
  END r_data[143]
  PIN r_data[144]
    DIRECTION OUTPUT ;
    USE SIGNAL ;
    PORT
      LAYER M4 ;
        RECT  86.316 45.072 86.4 45.096 ;
    END
  END r_data[144]
  PIN r_data[145]
    DIRECTION OUTPUT ;
    USE SIGNAL ;
    PORT
      LAYER M4 ;
        RECT  86.316 45.168 86.4 45.192 ;
    END
  END r_data[145]
  PIN r_data[146]
    DIRECTION OUTPUT ;
    USE SIGNAL ;
    PORT
      LAYER M4 ;
        RECT  86.316 45.264 86.4 45.288 ;
    END
  END r_data[146]
  PIN r_data[147]
    DIRECTION OUTPUT ;
    USE SIGNAL ;
    PORT
      LAYER M4 ;
        RECT  86.316 45.36 86.4 45.384 ;
    END
  END r_data[147]
  PIN r_data[148]
    DIRECTION OUTPUT ;
    USE SIGNAL ;
    PORT
      LAYER M4 ;
        RECT  86.316 45.456 86.4 45.48 ;
    END
  END r_data[148]
  PIN r_data[149]
    DIRECTION OUTPUT ;
    USE SIGNAL ;
    PORT
      LAYER M4 ;
        RECT  86.316 45.552 86.4 45.576 ;
    END
  END r_data[149]
  PIN r_data[14]
    DIRECTION OUTPUT ;
    USE SIGNAL ;
    PORT
      LAYER M4 ;
        RECT  86.316 54.096 86.4 54.12 ;
    END
  END r_data[14]
  PIN r_data[150]
    DIRECTION OUTPUT ;
    USE SIGNAL ;
    PORT
      LAYER M4 ;
        RECT  86.316 45.648 86.4 45.672 ;
    END
  END r_data[150]
  PIN r_data[151]
    DIRECTION OUTPUT ;
    USE SIGNAL ;
    PORT
      LAYER M4 ;
        RECT  86.316 45.744 86.4 45.768 ;
    END
  END r_data[151]
  PIN r_data[152]
    DIRECTION OUTPUT ;
    USE SIGNAL ;
    PORT
      LAYER M4 ;
        RECT  86.316 45.84 86.4 45.864 ;
    END
  END r_data[152]
  PIN r_data[153]
    DIRECTION OUTPUT ;
    USE SIGNAL ;
    PORT
      LAYER M4 ;
        RECT  86.316 45.936 86.4 45.96 ;
    END
  END r_data[153]
  PIN r_data[154]
    DIRECTION OUTPUT ;
    USE SIGNAL ;
    PORT
      LAYER M4 ;
        RECT  86.316 46.032 86.4 46.056 ;
    END
  END r_data[154]
  PIN r_data[155]
    DIRECTION OUTPUT ;
    USE SIGNAL ;
    PORT
      LAYER M4 ;
        RECT  86.316 46.128 86.4 46.152 ;
    END
  END r_data[155]
  PIN r_data[156]
    DIRECTION OUTPUT ;
    USE SIGNAL ;
    PORT
      LAYER M4 ;
        RECT  86.316 46.224 86.4 46.248 ;
    END
  END r_data[156]
  PIN r_data[157]
    DIRECTION OUTPUT ;
    USE SIGNAL ;
    PORT
      LAYER M4 ;
        RECT  86.316 46.32 86.4 46.344 ;
    END
  END r_data[157]
  PIN r_data[158]
    DIRECTION OUTPUT ;
    USE SIGNAL ;
    PORT
      LAYER M4 ;
        RECT  86.316 46.416 86.4 46.44 ;
    END
  END r_data[158]
  PIN r_data[159]
    DIRECTION OUTPUT ;
    USE SIGNAL ;
    PORT
      LAYER M4 ;
        RECT  86.316 46.512 86.4 46.536 ;
    END
  END r_data[159]
  PIN r_data[15]
    DIRECTION OUTPUT ;
    USE SIGNAL ;
    PORT
      LAYER M4 ;
        RECT  86.316 54.192 86.4 54.216 ;
    END
  END r_data[15]
  PIN r_data[160]
    DIRECTION OUTPUT ;
    USE SIGNAL ;
    PORT
      LAYER M4 ;
        RECT  86.316 46.608 86.4 46.632 ;
    END
  END r_data[160]
  PIN r_data[161]
    DIRECTION OUTPUT ;
    USE SIGNAL ;
    PORT
      LAYER M4 ;
        RECT  86.316 46.704 86.4 46.728 ;
    END
  END r_data[161]
  PIN r_data[162]
    DIRECTION OUTPUT ;
    USE SIGNAL ;
    PORT
      LAYER M4 ;
        RECT  86.316 46.8 86.4 46.824 ;
    END
  END r_data[162]
  PIN r_data[163]
    DIRECTION OUTPUT ;
    USE SIGNAL ;
    PORT
      LAYER M4 ;
        RECT  86.316 46.896 86.4 46.92 ;
    END
  END r_data[163]
  PIN r_data[164]
    DIRECTION OUTPUT ;
    USE SIGNAL ;
    PORT
      LAYER M4 ;
        RECT  86.316 46.992 86.4 47.016 ;
    END
  END r_data[164]
  PIN r_data[165]
    DIRECTION OUTPUT ;
    USE SIGNAL ;
    PORT
      LAYER M4 ;
        RECT  86.316 47.088 86.4 47.112 ;
    END
  END r_data[165]
  PIN r_data[166]
    DIRECTION OUTPUT ;
    USE SIGNAL ;
    PORT
      LAYER M4 ;
        RECT  86.316 47.184 86.4 47.208 ;
    END
  END r_data[166]
  PIN r_data[167]
    DIRECTION OUTPUT ;
    USE SIGNAL ;
    PORT
      LAYER M4 ;
        RECT  86.316 47.28 86.4 47.304 ;
    END
  END r_data[167]
  PIN r_data[168]
    DIRECTION OUTPUT ;
    USE SIGNAL ;
    PORT
      LAYER M4 ;
        RECT  86.316 47.376 86.4 47.4 ;
    END
  END r_data[168]
  PIN r_data[169]
    DIRECTION OUTPUT ;
    USE SIGNAL ;
    PORT
      LAYER M4 ;
        RECT  86.316 47.472 86.4 47.496 ;
    END
  END r_data[169]
  PIN r_data[16]
    DIRECTION OUTPUT ;
    USE SIGNAL ;
    PORT
      LAYER M4 ;
        RECT  86.316 54.288 86.4 54.312 ;
    END
  END r_data[16]
  PIN r_data[170]
    DIRECTION OUTPUT ;
    USE SIGNAL ;
    PORT
      LAYER M4 ;
        RECT  86.316 47.568 86.4 47.592 ;
    END
  END r_data[170]
  PIN r_data[171]
    DIRECTION OUTPUT ;
    USE SIGNAL ;
    PORT
      LAYER M4 ;
        RECT  86.316 47.664 86.4 47.688 ;
    END
  END r_data[171]
  PIN r_data[172]
    DIRECTION OUTPUT ;
    USE SIGNAL ;
    PORT
      LAYER M4 ;
        RECT  86.316 47.76 86.4 47.784 ;
    END
  END r_data[172]
  PIN r_data[173]
    DIRECTION OUTPUT ;
    USE SIGNAL ;
    PORT
      LAYER M4 ;
        RECT  86.316 47.856 86.4 47.88 ;
    END
  END r_data[173]
  PIN r_data[174]
    DIRECTION OUTPUT ;
    USE SIGNAL ;
    PORT
      LAYER M4 ;
        RECT  86.316 47.952 86.4 47.976 ;
    END
  END r_data[174]
  PIN r_data[175]
    DIRECTION OUTPUT ;
    USE SIGNAL ;
    PORT
      LAYER M4 ;
        RECT  86.316 48.048 86.4 48.072 ;
    END
  END r_data[175]
  PIN r_data[176]
    DIRECTION OUTPUT ;
    USE SIGNAL ;
    PORT
      LAYER M4 ;
        RECT  86.316 48.144 86.4 48.168 ;
    END
  END r_data[176]
  PIN r_data[177]
    DIRECTION OUTPUT ;
    USE SIGNAL ;
    PORT
      LAYER M4 ;
        RECT  86.316 48.24 86.4 48.264 ;
    END
  END r_data[177]
  PIN r_data[178]
    DIRECTION OUTPUT ;
    USE SIGNAL ;
    PORT
      LAYER M4 ;
        RECT  86.316 48.336 86.4 48.36 ;
    END
  END r_data[178]
  PIN r_data[179]
    DIRECTION OUTPUT ;
    USE SIGNAL ;
    PORT
      LAYER M4 ;
        RECT  86.316 48.432 86.4 48.456 ;
    END
  END r_data[179]
  PIN r_data[17]
    DIRECTION OUTPUT ;
    USE SIGNAL ;
    PORT
      LAYER M4 ;
        RECT  86.316 54.384 86.4 54.408 ;
    END
  END r_data[17]
  PIN r_data[180]
    DIRECTION OUTPUT ;
    USE SIGNAL ;
    PORT
      LAYER M4 ;
        RECT  86.316 48.528 86.4 48.552 ;
    END
  END r_data[180]
  PIN r_data[181]
    DIRECTION OUTPUT ;
    USE SIGNAL ;
    PORT
      LAYER M4 ;
        RECT  86.316 48.624 86.4 48.648 ;
    END
  END r_data[181]
  PIN r_data[182]
    DIRECTION OUTPUT ;
    USE SIGNAL ;
    PORT
      LAYER M4 ;
        RECT  86.316 48.72 86.4 48.744 ;
    END
  END r_data[182]
  PIN r_data[183]
    DIRECTION OUTPUT ;
    USE SIGNAL ;
    PORT
      LAYER M4 ;
        RECT  86.316 48.816 86.4 48.84 ;
    END
  END r_data[183]
  PIN r_data[184]
    DIRECTION OUTPUT ;
    USE SIGNAL ;
    PORT
      LAYER M4 ;
        RECT  86.316 48.912 86.4 48.936 ;
    END
  END r_data[184]
  PIN r_data[185]
    DIRECTION OUTPUT ;
    USE SIGNAL ;
    PORT
      LAYER M4 ;
        RECT  86.316 49.008 86.4 49.032 ;
    END
  END r_data[185]
  PIN r_data[186]
    DIRECTION OUTPUT ;
    USE SIGNAL ;
    PORT
      LAYER M4 ;
        RECT  86.316 49.104 86.4 49.128 ;
    END
  END r_data[186]
  PIN r_data[187]
    DIRECTION OUTPUT ;
    USE SIGNAL ;
    PORT
      LAYER M4 ;
        RECT  86.316 49.2 86.4 49.224 ;
    END
  END r_data[187]
  PIN r_data[188]
    DIRECTION OUTPUT ;
    USE SIGNAL ;
    PORT
      LAYER M4 ;
        RECT  86.316 49.296 86.4 49.32 ;
    END
  END r_data[188]
  PIN r_data[189]
    DIRECTION OUTPUT ;
    USE SIGNAL ;
    PORT
      LAYER M4 ;
        RECT  86.316 49.392 86.4 49.416 ;
    END
  END r_data[189]
  PIN r_data[18]
    DIRECTION OUTPUT ;
    USE SIGNAL ;
    PORT
      LAYER M4 ;
        RECT  86.316 54.48 86.4 54.504 ;
    END
  END r_data[18]
  PIN r_data[190]
    DIRECTION OUTPUT ;
    USE SIGNAL ;
    PORT
      LAYER M4 ;
        RECT  86.316 49.488 86.4 49.512 ;
    END
  END r_data[190]
  PIN r_data[191]
    DIRECTION OUTPUT ;
    USE SIGNAL ;
    PORT
      LAYER M4 ;
        RECT  86.316 49.584 86.4 49.608 ;
    END
  END r_data[191]
  PIN r_data[192]
    DIRECTION OUTPUT ;
    USE SIGNAL ;
    PORT
      LAYER M4 ;
        RECT  86.316 36.624 86.4 36.648 ;
    END
  END r_data[192]
  PIN r_data[193]
    DIRECTION OUTPUT ;
    USE SIGNAL ;
    PORT
      LAYER M4 ;
        RECT  86.316 36.72 86.4 36.744 ;
    END
  END r_data[193]
  PIN r_data[194]
    DIRECTION OUTPUT ;
    USE SIGNAL ;
    PORT
      LAYER M4 ;
        RECT  86.316 36.816 86.4 36.84 ;
    END
  END r_data[194]
  PIN r_data[195]
    DIRECTION OUTPUT ;
    USE SIGNAL ;
    PORT
      LAYER M4 ;
        RECT  86.316 36.912 86.4 36.936 ;
    END
  END r_data[195]
  PIN r_data[196]
    DIRECTION OUTPUT ;
    USE SIGNAL ;
    PORT
      LAYER M4 ;
        RECT  86.316 37.008 86.4 37.032 ;
    END
  END r_data[196]
  PIN r_data[197]
    DIRECTION OUTPUT ;
    USE SIGNAL ;
    PORT
      LAYER M4 ;
        RECT  86.316 37.104 86.4 37.128 ;
    END
  END r_data[197]
  PIN r_data[198]
    DIRECTION OUTPUT ;
    USE SIGNAL ;
    PORT
      LAYER M4 ;
        RECT  86.316 37.2 86.4 37.224 ;
    END
  END r_data[198]
  PIN r_data[199]
    DIRECTION OUTPUT ;
    USE SIGNAL ;
    PORT
      LAYER M4 ;
        RECT  86.316 37.296 86.4 37.32 ;
    END
  END r_data[199]
  PIN r_data[19]
    DIRECTION OUTPUT ;
    USE SIGNAL ;
    PORT
      LAYER M4 ;
        RECT  86.316 54.576 86.4 54.6 ;
    END
  END r_data[19]
  PIN r_data[1]
    DIRECTION OUTPUT ;
    USE SIGNAL ;
    PORT
      LAYER M4 ;
        RECT  86.316 52.848 86.4 52.872 ;
    END
  END r_data[1]
  PIN r_data[200]
    DIRECTION OUTPUT ;
    USE SIGNAL ;
    PORT
      LAYER M4 ;
        RECT  86.316 37.392 86.4 37.416 ;
    END
  END r_data[200]
  PIN r_data[201]
    DIRECTION OUTPUT ;
    USE SIGNAL ;
    PORT
      LAYER M4 ;
        RECT  86.316 37.488 86.4 37.512 ;
    END
  END r_data[201]
  PIN r_data[202]
    DIRECTION OUTPUT ;
    USE SIGNAL ;
    PORT
      LAYER M4 ;
        RECT  86.316 37.584 86.4 37.608 ;
    END
  END r_data[202]
  PIN r_data[203]
    DIRECTION OUTPUT ;
    USE SIGNAL ;
    PORT
      LAYER M4 ;
        RECT  86.316 37.68 86.4 37.704 ;
    END
  END r_data[203]
  PIN r_data[204]
    DIRECTION OUTPUT ;
    USE SIGNAL ;
    PORT
      LAYER M4 ;
        RECT  86.316 37.776 86.4 37.8 ;
    END
  END r_data[204]
  PIN r_data[205]
    DIRECTION OUTPUT ;
    USE SIGNAL ;
    PORT
      LAYER M4 ;
        RECT  86.316 37.872 86.4 37.896 ;
    END
  END r_data[205]
  PIN r_data[206]
    DIRECTION OUTPUT ;
    USE SIGNAL ;
    PORT
      LAYER M4 ;
        RECT  86.316 37.968 86.4 37.992 ;
    END
  END r_data[206]
  PIN r_data[207]
    DIRECTION OUTPUT ;
    USE SIGNAL ;
    PORT
      LAYER M4 ;
        RECT  86.316 38.064 86.4 38.088 ;
    END
  END r_data[207]
  PIN r_data[208]
    DIRECTION OUTPUT ;
    USE SIGNAL ;
    PORT
      LAYER M4 ;
        RECT  86.316 38.16 86.4 38.184 ;
    END
  END r_data[208]
  PIN r_data[209]
    DIRECTION OUTPUT ;
    USE SIGNAL ;
    PORT
      LAYER M4 ;
        RECT  86.316 38.256 86.4 38.28 ;
    END
  END r_data[209]
  PIN r_data[20]
    DIRECTION OUTPUT ;
    USE SIGNAL ;
    PORT
      LAYER M4 ;
        RECT  86.316 54.672 86.4 54.696 ;
    END
  END r_data[20]
  PIN r_data[210]
    DIRECTION OUTPUT ;
    USE SIGNAL ;
    PORT
      LAYER M4 ;
        RECT  86.316 38.352 86.4 38.376 ;
    END
  END r_data[210]
  PIN r_data[211]
    DIRECTION OUTPUT ;
    USE SIGNAL ;
    PORT
      LAYER M4 ;
        RECT  86.316 38.448 86.4 38.472 ;
    END
  END r_data[211]
  PIN r_data[212]
    DIRECTION OUTPUT ;
    USE SIGNAL ;
    PORT
      LAYER M4 ;
        RECT  86.316 38.544 86.4 38.568 ;
    END
  END r_data[212]
  PIN r_data[213]
    DIRECTION OUTPUT ;
    USE SIGNAL ;
    PORT
      LAYER M4 ;
        RECT  86.316 38.64 86.4 38.664 ;
    END
  END r_data[213]
  PIN r_data[214]
    DIRECTION OUTPUT ;
    USE SIGNAL ;
    PORT
      LAYER M4 ;
        RECT  86.316 38.736 86.4 38.76 ;
    END
  END r_data[214]
  PIN r_data[215]
    DIRECTION OUTPUT ;
    USE SIGNAL ;
    PORT
      LAYER M4 ;
        RECT  86.316 38.832 86.4 38.856 ;
    END
  END r_data[215]
  PIN r_data[216]
    DIRECTION OUTPUT ;
    USE SIGNAL ;
    PORT
      LAYER M4 ;
        RECT  86.316 38.928 86.4 38.952 ;
    END
  END r_data[216]
  PIN r_data[217]
    DIRECTION OUTPUT ;
    USE SIGNAL ;
    PORT
      LAYER M4 ;
        RECT  86.316 39.024 86.4 39.048 ;
    END
  END r_data[217]
  PIN r_data[218]
    DIRECTION OUTPUT ;
    USE SIGNAL ;
    PORT
      LAYER M4 ;
        RECT  86.316 39.12 86.4 39.144 ;
    END
  END r_data[218]
  PIN r_data[219]
    DIRECTION OUTPUT ;
    USE SIGNAL ;
    PORT
      LAYER M4 ;
        RECT  86.316 39.216 86.4 39.24 ;
    END
  END r_data[219]
  PIN r_data[21]
    DIRECTION OUTPUT ;
    USE SIGNAL ;
    PORT
      LAYER M4 ;
        RECT  86.316 54.768 86.4 54.792 ;
    END
  END r_data[21]
  PIN r_data[220]
    DIRECTION OUTPUT ;
    USE SIGNAL ;
    PORT
      LAYER M4 ;
        RECT  86.316 39.312 86.4 39.336 ;
    END
  END r_data[220]
  PIN r_data[221]
    DIRECTION OUTPUT ;
    USE SIGNAL ;
    PORT
      LAYER M4 ;
        RECT  86.316 39.408 86.4 39.432 ;
    END
  END r_data[221]
  PIN r_data[222]
    DIRECTION OUTPUT ;
    USE SIGNAL ;
    PORT
      LAYER M4 ;
        RECT  86.316 39.504 86.4 39.528 ;
    END
  END r_data[222]
  PIN r_data[223]
    DIRECTION OUTPUT ;
    USE SIGNAL ;
    PORT
      LAYER M4 ;
        RECT  86.316 39.6 86.4 39.624 ;
    END
  END r_data[223]
  PIN r_data[224]
    DIRECTION OUTPUT ;
    USE SIGNAL ;
    PORT
      LAYER M4 ;
        RECT  86.316 33.552 86.4 33.576 ;
    END
  END r_data[224]
  PIN r_data[225]
    DIRECTION OUTPUT ;
    USE SIGNAL ;
    PORT
      LAYER M4 ;
        RECT  86.316 33.648 86.4 33.672 ;
    END
  END r_data[225]
  PIN r_data[226]
    DIRECTION OUTPUT ;
    USE SIGNAL ;
    PORT
      LAYER M4 ;
        RECT  86.316 33.744 86.4 33.768 ;
    END
  END r_data[226]
  PIN r_data[227]
    DIRECTION OUTPUT ;
    USE SIGNAL ;
    PORT
      LAYER M4 ;
        RECT  86.316 33.84 86.4 33.864 ;
    END
  END r_data[227]
  PIN r_data[228]
    DIRECTION OUTPUT ;
    USE SIGNAL ;
    PORT
      LAYER M4 ;
        RECT  86.316 33.936 86.4 33.96 ;
    END
  END r_data[228]
  PIN r_data[229]
    DIRECTION OUTPUT ;
    USE SIGNAL ;
    PORT
      LAYER M4 ;
        RECT  86.316 34.032 86.4 34.056 ;
    END
  END r_data[229]
  PIN r_data[22]
    DIRECTION OUTPUT ;
    USE SIGNAL ;
    PORT
      LAYER M4 ;
        RECT  86.316 54.864 86.4 54.888 ;
    END
  END r_data[22]
  PIN r_data[230]
    DIRECTION OUTPUT ;
    USE SIGNAL ;
    PORT
      LAYER M4 ;
        RECT  86.316 34.128 86.4 34.152 ;
    END
  END r_data[230]
  PIN r_data[231]
    DIRECTION OUTPUT ;
    USE SIGNAL ;
    PORT
      LAYER M4 ;
        RECT  86.316 34.224 86.4 34.248 ;
    END
  END r_data[231]
  PIN r_data[232]
    DIRECTION OUTPUT ;
    USE SIGNAL ;
    PORT
      LAYER M4 ;
        RECT  86.316 34.32 86.4 34.344 ;
    END
  END r_data[232]
  PIN r_data[233]
    DIRECTION OUTPUT ;
    USE SIGNAL ;
    PORT
      LAYER M4 ;
        RECT  86.316 34.416 86.4 34.44 ;
    END
  END r_data[233]
  PIN r_data[234]
    DIRECTION OUTPUT ;
    USE SIGNAL ;
    PORT
      LAYER M4 ;
        RECT  86.316 34.512 86.4 34.536 ;
    END
  END r_data[234]
  PIN r_data[235]
    DIRECTION OUTPUT ;
    USE SIGNAL ;
    PORT
      LAYER M4 ;
        RECT  86.316 34.608 86.4 34.632 ;
    END
  END r_data[235]
  PIN r_data[236]
    DIRECTION OUTPUT ;
    USE SIGNAL ;
    PORT
      LAYER M4 ;
        RECT  86.316 34.704 86.4 34.728 ;
    END
  END r_data[236]
  PIN r_data[237]
    DIRECTION OUTPUT ;
    USE SIGNAL ;
    PORT
      LAYER M4 ;
        RECT  86.316 34.8 86.4 34.824 ;
    END
  END r_data[237]
  PIN r_data[238]
    DIRECTION OUTPUT ;
    USE SIGNAL ;
    PORT
      LAYER M4 ;
        RECT  86.316 34.896 86.4 34.92 ;
    END
  END r_data[238]
  PIN r_data[239]
    DIRECTION OUTPUT ;
    USE SIGNAL ;
    PORT
      LAYER M4 ;
        RECT  86.316 34.992 86.4 35.016 ;
    END
  END r_data[239]
  PIN r_data[23]
    DIRECTION OUTPUT ;
    USE SIGNAL ;
    PORT
      LAYER M4 ;
        RECT  86.316 54.96 86.4 54.984 ;
    END
  END r_data[23]
  PIN r_data[240]
    DIRECTION OUTPUT ;
    USE SIGNAL ;
    PORT
      LAYER M4 ;
        RECT  86.316 35.088 86.4 35.112 ;
    END
  END r_data[240]
  PIN r_data[241]
    DIRECTION OUTPUT ;
    USE SIGNAL ;
    PORT
      LAYER M4 ;
        RECT  86.316 35.184 86.4 35.208 ;
    END
  END r_data[241]
  PIN r_data[242]
    DIRECTION OUTPUT ;
    USE SIGNAL ;
    PORT
      LAYER M4 ;
        RECT  86.316 35.28 86.4 35.304 ;
    END
  END r_data[242]
  PIN r_data[243]
    DIRECTION OUTPUT ;
    USE SIGNAL ;
    PORT
      LAYER M4 ;
        RECT  86.316 35.376 86.4 35.4 ;
    END
  END r_data[243]
  PIN r_data[244]
    DIRECTION OUTPUT ;
    USE SIGNAL ;
    PORT
      LAYER M4 ;
        RECT  86.316 35.472 86.4 35.496 ;
    END
  END r_data[244]
  PIN r_data[245]
    DIRECTION OUTPUT ;
    USE SIGNAL ;
    PORT
      LAYER M4 ;
        RECT  86.316 35.568 86.4 35.592 ;
    END
  END r_data[245]
  PIN r_data[246]
    DIRECTION OUTPUT ;
    USE SIGNAL ;
    PORT
      LAYER M4 ;
        RECT  86.316 35.664 86.4 35.688 ;
    END
  END r_data[246]
  PIN r_data[247]
    DIRECTION OUTPUT ;
    USE SIGNAL ;
    PORT
      LAYER M4 ;
        RECT  86.316 35.76 86.4 35.784 ;
    END
  END r_data[247]
  PIN r_data[248]
    DIRECTION OUTPUT ;
    USE SIGNAL ;
    PORT
      LAYER M4 ;
        RECT  86.316 35.856 86.4 35.88 ;
    END
  END r_data[248]
  PIN r_data[249]
    DIRECTION OUTPUT ;
    USE SIGNAL ;
    PORT
      LAYER M4 ;
        RECT  86.316 35.952 86.4 35.976 ;
    END
  END r_data[249]
  PIN r_data[24]
    DIRECTION OUTPUT ;
    USE SIGNAL ;
    PORT
      LAYER M4 ;
        RECT  86.316 55.056 86.4 55.08 ;
    END
  END r_data[24]
  PIN r_data[250]
    DIRECTION OUTPUT ;
    USE SIGNAL ;
    PORT
      LAYER M4 ;
        RECT  86.316 36.048 86.4 36.072 ;
    END
  END r_data[250]
  PIN r_data[251]
    DIRECTION OUTPUT ;
    USE SIGNAL ;
    PORT
      LAYER M4 ;
        RECT  86.316 36.144 86.4 36.168 ;
    END
  END r_data[251]
  PIN r_data[252]
    DIRECTION OUTPUT ;
    USE SIGNAL ;
    PORT
      LAYER M4 ;
        RECT  86.316 36.24 86.4 36.264 ;
    END
  END r_data[252]
  PIN r_data[253]
    DIRECTION OUTPUT ;
    USE SIGNAL ;
    PORT
      LAYER M4 ;
        RECT  86.316 36.336 86.4 36.36 ;
    END
  END r_data[253]
  PIN r_data[254]
    DIRECTION OUTPUT ;
    USE SIGNAL ;
    PORT
      LAYER M4 ;
        RECT  86.316 36.432 86.4 36.456 ;
    END
  END r_data[254]
  PIN r_data[255]
    DIRECTION OUTPUT ;
    USE SIGNAL ;
    PORT
      LAYER M4 ;
        RECT  86.316 36.528 86.4 36.552 ;
    END
  END r_data[255]
  PIN r_data[25]
    DIRECTION OUTPUT ;
    USE SIGNAL ;
    PORT
      LAYER M4 ;
        RECT  86.316 55.152 86.4 55.176 ;
    END
  END r_data[25]
  PIN r_data[26]
    DIRECTION OUTPUT ;
    USE SIGNAL ;
    PORT
      LAYER M4 ;
        RECT  86.316 55.248 86.4 55.272 ;
    END
  END r_data[26]
  PIN r_data[27]
    DIRECTION OUTPUT ;
    USE SIGNAL ;
    PORT
      LAYER M4 ;
        RECT  86.316 55.344 86.4 55.368 ;
    END
  END r_data[27]
  PIN r_data[28]
    DIRECTION OUTPUT ;
    USE SIGNAL ;
    PORT
      LAYER M4 ;
        RECT  86.316 55.44 86.4 55.464 ;
    END
  END r_data[28]
  PIN r_data[29]
    DIRECTION OUTPUT ;
    USE SIGNAL ;
    PORT
      LAYER M4 ;
        RECT  86.316 55.536 86.4 55.56 ;
    END
  END r_data[29]
  PIN r_data[2]
    DIRECTION OUTPUT ;
    USE SIGNAL ;
    PORT
      LAYER M4 ;
        RECT  86.316 52.944 86.4 52.968 ;
    END
  END r_data[2]
  PIN r_data[30]
    DIRECTION OUTPUT ;
    USE SIGNAL ;
    PORT
      LAYER M4 ;
        RECT  86.316 55.632 86.4 55.656 ;
    END
  END r_data[30]
  PIN r_data[31]
    DIRECTION OUTPUT ;
    USE SIGNAL ;
    PORT
      LAYER M4 ;
        RECT  86.316 55.728 86.4 55.752 ;
    END
  END r_data[31]
  PIN r_data[32]
    DIRECTION OUTPUT ;
    USE SIGNAL ;
    PORT
      LAYER M4 ;
        RECT  86.316 40.464 86.4 40.488 ;
    END
  END r_data[32]
  PIN r_data[33]
    DIRECTION OUTPUT ;
    USE SIGNAL ;
    PORT
      LAYER M4 ;
        RECT  86.316 40.56 86.4 40.584 ;
    END
  END r_data[33]
  PIN r_data[34]
    DIRECTION OUTPUT ;
    USE SIGNAL ;
    PORT
      LAYER M4 ;
        RECT  86.316 40.656 86.4 40.68 ;
    END
  END r_data[34]
  PIN r_data[35]
    DIRECTION OUTPUT ;
    USE SIGNAL ;
    PORT
      LAYER M4 ;
        RECT  86.316 40.752 86.4 40.776 ;
    END
  END r_data[35]
  PIN r_data[36]
    DIRECTION OUTPUT ;
    USE SIGNAL ;
    PORT
      LAYER M4 ;
        RECT  86.316 40.848 86.4 40.872 ;
    END
  END r_data[36]
  PIN r_data[37]
    DIRECTION OUTPUT ;
    USE SIGNAL ;
    PORT
      LAYER M4 ;
        RECT  86.316 40.944 86.4 40.968 ;
    END
  END r_data[37]
  PIN r_data[38]
    DIRECTION OUTPUT ;
    USE SIGNAL ;
    PORT
      LAYER M4 ;
        RECT  86.316 41.04 86.4 41.064 ;
    END
  END r_data[38]
  PIN r_data[39]
    DIRECTION OUTPUT ;
    USE SIGNAL ;
    PORT
      LAYER M4 ;
        RECT  86.316 41.136 86.4 41.16 ;
    END
  END r_data[39]
  PIN r_data[3]
    DIRECTION OUTPUT ;
    USE SIGNAL ;
    PORT
      LAYER M4 ;
        RECT  86.316 53.04 86.4 53.064 ;
    END
  END r_data[3]
  PIN r_data[40]
    DIRECTION OUTPUT ;
    USE SIGNAL ;
    PORT
      LAYER M4 ;
        RECT  86.316 41.232 86.4 41.256 ;
    END
  END r_data[40]
  PIN r_data[41]
    DIRECTION OUTPUT ;
    USE SIGNAL ;
    PORT
      LAYER M4 ;
        RECT  86.316 41.328 86.4 41.352 ;
    END
  END r_data[41]
  PIN r_data[42]
    DIRECTION OUTPUT ;
    USE SIGNAL ;
    PORT
      LAYER M4 ;
        RECT  86.316 41.424 86.4 41.448 ;
    END
  END r_data[42]
  PIN r_data[43]
    DIRECTION OUTPUT ;
    USE SIGNAL ;
    PORT
      LAYER M4 ;
        RECT  86.316 41.52 86.4 41.544 ;
    END
  END r_data[43]
  PIN r_data[44]
    DIRECTION OUTPUT ;
    USE SIGNAL ;
    PORT
      LAYER M4 ;
        RECT  86.316 41.616 86.4 41.64 ;
    END
  END r_data[44]
  PIN r_data[45]
    DIRECTION OUTPUT ;
    USE SIGNAL ;
    PORT
      LAYER M4 ;
        RECT  86.316 41.712 86.4 41.736 ;
    END
  END r_data[45]
  PIN r_data[46]
    DIRECTION OUTPUT ;
    USE SIGNAL ;
    PORT
      LAYER M4 ;
        RECT  86.316 41.808 86.4 41.832 ;
    END
  END r_data[46]
  PIN r_data[47]
    DIRECTION OUTPUT ;
    USE SIGNAL ;
    PORT
      LAYER M4 ;
        RECT  86.316 41.904 86.4 41.928 ;
    END
  END r_data[47]
  PIN r_data[48]
    DIRECTION OUTPUT ;
    USE SIGNAL ;
    PORT
      LAYER M4 ;
        RECT  86.316 42 86.4 42.024 ;
    END
  END r_data[48]
  PIN r_data[49]
    DIRECTION OUTPUT ;
    USE SIGNAL ;
    PORT
      LAYER M4 ;
        RECT  86.316 42.096 86.4 42.12 ;
    END
  END r_data[49]
  PIN r_data[4]
    DIRECTION OUTPUT ;
    USE SIGNAL ;
    PORT
      LAYER M4 ;
        RECT  86.316 53.136 86.4 53.16 ;
    END
  END r_data[4]
  PIN r_data[50]
    DIRECTION OUTPUT ;
    USE SIGNAL ;
    PORT
      LAYER M4 ;
        RECT  86.316 42.192 86.4 42.216 ;
    END
  END r_data[50]
  PIN r_data[51]
    DIRECTION OUTPUT ;
    USE SIGNAL ;
    PORT
      LAYER M4 ;
        RECT  86.316 42.288 86.4 42.312 ;
    END
  END r_data[51]
  PIN r_data[52]
    DIRECTION OUTPUT ;
    USE SIGNAL ;
    PORT
      LAYER M4 ;
        RECT  86.316 42.384 86.4 42.408 ;
    END
  END r_data[52]
  PIN r_data[53]
    DIRECTION OUTPUT ;
    USE SIGNAL ;
    PORT
      LAYER M4 ;
        RECT  86.316 42.48 86.4 42.504 ;
    END
  END r_data[53]
  PIN r_data[54]
    DIRECTION OUTPUT ;
    USE SIGNAL ;
    PORT
      LAYER M4 ;
        RECT  86.316 42.576 86.4 42.6 ;
    END
  END r_data[54]
  PIN r_data[55]
    DIRECTION OUTPUT ;
    USE SIGNAL ;
    PORT
      LAYER M4 ;
        RECT  86.316 42.672 86.4 42.696 ;
    END
  END r_data[55]
  PIN r_data[56]
    DIRECTION OUTPUT ;
    USE SIGNAL ;
    PORT
      LAYER M4 ;
        RECT  86.316 42.768 86.4 42.792 ;
    END
  END r_data[56]
  PIN r_data[57]
    DIRECTION OUTPUT ;
    USE SIGNAL ;
    PORT
      LAYER M4 ;
        RECT  86.316 42.864 86.4 42.888 ;
    END
  END r_data[57]
  PIN r_data[58]
    DIRECTION OUTPUT ;
    USE SIGNAL ;
    PORT
      LAYER M4 ;
        RECT  86.316 42.96 86.4 42.984 ;
    END
  END r_data[58]
  PIN r_data[59]
    DIRECTION OUTPUT ;
    USE SIGNAL ;
    PORT
      LAYER M4 ;
        RECT  86.316 43.056 86.4 43.08 ;
    END
  END r_data[59]
  PIN r_data[5]
    DIRECTION OUTPUT ;
    USE SIGNAL ;
    PORT
      LAYER M4 ;
        RECT  86.316 53.232 86.4 53.256 ;
    END
  END r_data[5]
  PIN r_data[60]
    DIRECTION OUTPUT ;
    USE SIGNAL ;
    PORT
      LAYER M4 ;
        RECT  86.316 43.152 86.4 43.176 ;
    END
  END r_data[60]
  PIN r_data[61]
    DIRECTION OUTPUT ;
    USE SIGNAL ;
    PORT
      LAYER M4 ;
        RECT  86.316 43.248 86.4 43.272 ;
    END
  END r_data[61]
  PIN r_data[62]
    DIRECTION OUTPUT ;
    USE SIGNAL ;
    PORT
      LAYER M4 ;
        RECT  86.316 43.344 86.4 43.368 ;
    END
  END r_data[62]
  PIN r_data[63]
    DIRECTION OUTPUT ;
    USE SIGNAL ;
    PORT
      LAYER M4 ;
        RECT  86.316 43.44 86.4 43.464 ;
    END
  END r_data[63]
  PIN r_data[64]
    DIRECTION OUTPUT ;
    USE SIGNAL ;
    PORT
      LAYER M4 ;
        RECT  86.316 49.68 86.4 49.704 ;
    END
  END r_data[64]
  PIN r_data[65]
    DIRECTION OUTPUT ;
    USE SIGNAL ;
    PORT
      LAYER M4 ;
        RECT  86.316 49.776 86.4 49.8 ;
    END
  END r_data[65]
  PIN r_data[66]
    DIRECTION OUTPUT ;
    USE SIGNAL ;
    PORT
      LAYER M4 ;
        RECT  86.316 49.872 86.4 49.896 ;
    END
  END r_data[66]
  PIN r_data[67]
    DIRECTION OUTPUT ;
    USE SIGNAL ;
    PORT
      LAYER M4 ;
        RECT  86.316 49.968 86.4 49.992 ;
    END
  END r_data[67]
  PIN r_data[68]
    DIRECTION OUTPUT ;
    USE SIGNAL ;
    PORT
      LAYER M4 ;
        RECT  86.316 50.064 86.4 50.088 ;
    END
  END r_data[68]
  PIN r_data[69]
    DIRECTION OUTPUT ;
    USE SIGNAL ;
    PORT
      LAYER M4 ;
        RECT  86.316 50.16 86.4 50.184 ;
    END
  END r_data[69]
  PIN r_data[6]
    DIRECTION OUTPUT ;
    USE SIGNAL ;
    PORT
      LAYER M4 ;
        RECT  86.316 53.328 86.4 53.352 ;
    END
  END r_data[6]
  PIN r_data[70]
    DIRECTION OUTPUT ;
    USE SIGNAL ;
    PORT
      LAYER M4 ;
        RECT  86.316 50.256 86.4 50.28 ;
    END
  END r_data[70]
  PIN r_data[71]
    DIRECTION OUTPUT ;
    USE SIGNAL ;
    PORT
      LAYER M4 ;
        RECT  86.316 50.352 86.4 50.376 ;
    END
  END r_data[71]
  PIN r_data[72]
    DIRECTION OUTPUT ;
    USE SIGNAL ;
    PORT
      LAYER M4 ;
        RECT  86.316 50.448 86.4 50.472 ;
    END
  END r_data[72]
  PIN r_data[73]
    DIRECTION OUTPUT ;
    USE SIGNAL ;
    PORT
      LAYER M4 ;
        RECT  86.316 50.544 86.4 50.568 ;
    END
  END r_data[73]
  PIN r_data[74]
    DIRECTION OUTPUT ;
    USE SIGNAL ;
    PORT
      LAYER M4 ;
        RECT  86.316 50.64 86.4 50.664 ;
    END
  END r_data[74]
  PIN r_data[75]
    DIRECTION OUTPUT ;
    USE SIGNAL ;
    PORT
      LAYER M4 ;
        RECT  86.316 50.736 86.4 50.76 ;
    END
  END r_data[75]
  PIN r_data[76]
    DIRECTION OUTPUT ;
    USE SIGNAL ;
    PORT
      LAYER M4 ;
        RECT  86.316 50.832 86.4 50.856 ;
    END
  END r_data[76]
  PIN r_data[77]
    DIRECTION OUTPUT ;
    USE SIGNAL ;
    PORT
      LAYER M4 ;
        RECT  86.316 50.928 86.4 50.952 ;
    END
  END r_data[77]
  PIN r_data[78]
    DIRECTION OUTPUT ;
    USE SIGNAL ;
    PORT
      LAYER M4 ;
        RECT  86.316 51.024 86.4 51.048 ;
    END
  END r_data[78]
  PIN r_data[79]
    DIRECTION OUTPUT ;
    USE SIGNAL ;
    PORT
      LAYER M4 ;
        RECT  86.316 51.12 86.4 51.144 ;
    END
  END r_data[79]
  PIN r_data[7]
    DIRECTION OUTPUT ;
    USE SIGNAL ;
    PORT
      LAYER M4 ;
        RECT  86.316 53.424 86.4 53.448 ;
    END
  END r_data[7]
  PIN r_data[80]
    DIRECTION OUTPUT ;
    USE SIGNAL ;
    PORT
      LAYER M4 ;
        RECT  86.316 51.216 86.4 51.24 ;
    END
  END r_data[80]
  PIN r_data[81]
    DIRECTION OUTPUT ;
    USE SIGNAL ;
    PORT
      LAYER M4 ;
        RECT  86.316 51.312 86.4 51.336 ;
    END
  END r_data[81]
  PIN r_data[82]
    DIRECTION OUTPUT ;
    USE SIGNAL ;
    PORT
      LAYER M4 ;
        RECT  86.316 51.408 86.4 51.432 ;
    END
  END r_data[82]
  PIN r_data[83]
    DIRECTION OUTPUT ;
    USE SIGNAL ;
    PORT
      LAYER M4 ;
        RECT  86.316 51.504 86.4 51.528 ;
    END
  END r_data[83]
  PIN r_data[84]
    DIRECTION OUTPUT ;
    USE SIGNAL ;
    PORT
      LAYER M4 ;
        RECT  86.316 51.6 86.4 51.624 ;
    END
  END r_data[84]
  PIN r_data[85]
    DIRECTION OUTPUT ;
    USE SIGNAL ;
    PORT
      LAYER M4 ;
        RECT  86.316 51.696 86.4 51.72 ;
    END
  END r_data[85]
  PIN r_data[86]
    DIRECTION OUTPUT ;
    USE SIGNAL ;
    PORT
      LAYER M4 ;
        RECT  86.316 51.792 86.4 51.816 ;
    END
  END r_data[86]
  PIN r_data[87]
    DIRECTION OUTPUT ;
    USE SIGNAL ;
    PORT
      LAYER M4 ;
        RECT  86.316 51.888 86.4 51.912 ;
    END
  END r_data[87]
  PIN r_data[88]
    DIRECTION OUTPUT ;
    USE SIGNAL ;
    PORT
      LAYER M4 ;
        RECT  86.316 51.984 86.4 52.008 ;
    END
  END r_data[88]
  PIN r_data[89]
    DIRECTION OUTPUT ;
    USE SIGNAL ;
    PORT
      LAYER M4 ;
        RECT  86.316 52.08 86.4 52.104 ;
    END
  END r_data[89]
  PIN r_data[8]
    DIRECTION OUTPUT ;
    USE SIGNAL ;
    PORT
      LAYER M4 ;
        RECT  86.316 53.52 86.4 53.544 ;
    END
  END r_data[8]
  PIN r_data[90]
    DIRECTION OUTPUT ;
    USE SIGNAL ;
    PORT
      LAYER M4 ;
        RECT  86.316 52.176 86.4 52.2 ;
    END
  END r_data[90]
  PIN r_data[91]
    DIRECTION OUTPUT ;
    USE SIGNAL ;
    PORT
      LAYER M4 ;
        RECT  86.316 52.272 86.4 52.296 ;
    END
  END r_data[91]
  PIN r_data[92]
    DIRECTION OUTPUT ;
    USE SIGNAL ;
    PORT
      LAYER M4 ;
        RECT  86.316 52.368 86.4 52.392 ;
    END
  END r_data[92]
  PIN r_data[93]
    DIRECTION OUTPUT ;
    USE SIGNAL ;
    PORT
      LAYER M4 ;
        RECT  86.316 52.464 86.4 52.488 ;
    END
  END r_data[93]
  PIN r_data[94]
    DIRECTION OUTPUT ;
    USE SIGNAL ;
    PORT
      LAYER M4 ;
        RECT  86.316 52.56 86.4 52.584 ;
    END
  END r_data[94]
  PIN r_data[95]
    DIRECTION OUTPUT ;
    USE SIGNAL ;
    PORT
      LAYER M4 ;
        RECT  86.316 52.656 86.4 52.68 ;
    END
  END r_data[95]
  PIN r_data[96]
    DIRECTION OUTPUT ;
    USE SIGNAL ;
    PORT
      LAYER M4 ;
        RECT  86.316 55.824 86.4 55.848 ;
    END
  END r_data[96]
  PIN r_data[97]
    DIRECTION OUTPUT ;
    USE SIGNAL ;
    PORT
      LAYER M4 ;
        RECT  86.316 55.92 86.4 55.944 ;
    END
  END r_data[97]
  PIN r_data[98]
    DIRECTION OUTPUT ;
    USE SIGNAL ;
    PORT
      LAYER M4 ;
        RECT  86.316 56.016 86.4 56.04 ;
    END
  END r_data[98]
  PIN r_data[99]
    DIRECTION OUTPUT ;
    USE SIGNAL ;
    PORT
      LAYER M4 ;
        RECT  86.316 56.112 86.4 56.136 ;
    END
  END r_data[99]
  PIN r_data[9]
    DIRECTION OUTPUT ;
    USE SIGNAL ;
    PORT
      LAYER M4 ;
        RECT  86.316 53.616 86.4 53.64 ;
    END
  END r_data[9]
  PIN r_len[0]
    DIRECTION OUTPUT ;
    USE SIGNAL ;
    PORT
      LAYER M4 ;
        RECT  86.316 80.496 86.4 80.52 ;
    END
  END r_len[0]
  PIN r_len[10]
    DIRECTION OUTPUT ;
    USE SIGNAL ;
    PORT
      LAYER M4 ;
        RECT  86.316 81.456 86.4 81.48 ;
    END
  END r_len[10]
  PIN r_len[11]
    DIRECTION OUTPUT ;
    USE SIGNAL ;
    PORT
      LAYER M4 ;
        RECT  86.316 81.552 86.4 81.576 ;
    END
  END r_len[11]
  PIN r_len[12]
    DIRECTION OUTPUT ;
    USE SIGNAL ;
    PORT
      LAYER M4 ;
        RECT  86.316 81.648 86.4 81.672 ;
    END
  END r_len[12]
  PIN r_len[13]
    DIRECTION OUTPUT ;
    USE SIGNAL ;
    PORT
      LAYER M4 ;
        RECT  86.316 81.744 86.4 81.768 ;
    END
  END r_len[13]
  PIN r_len[14]
    DIRECTION OUTPUT ;
    USE SIGNAL ;
    PORT
      LAYER M4 ;
        RECT  86.316 81.84 86.4 81.864 ;
    END
  END r_len[14]
  PIN r_len[15]
    DIRECTION OUTPUT ;
    USE SIGNAL ;
    PORT
      LAYER M4 ;
        RECT  86.316 81.936 86.4 81.96 ;
    END
  END r_len[15]
  PIN r_len[1]
    DIRECTION OUTPUT ;
    USE SIGNAL ;
    PORT
      LAYER M4 ;
        RECT  86.316 80.592 86.4 80.616 ;
    END
  END r_len[1]
  PIN r_len[2]
    DIRECTION OUTPUT ;
    USE SIGNAL ;
    PORT
      LAYER M4 ;
        RECT  86.316 80.688 86.4 80.712 ;
    END
  END r_len[2]
  PIN r_len[3]
    DIRECTION OUTPUT ;
    USE SIGNAL ;
    PORT
      LAYER M4 ;
        RECT  86.316 80.784 86.4 80.808 ;
    END
  END r_len[3]
  PIN r_len[4]
    DIRECTION OUTPUT ;
    USE SIGNAL ;
    PORT
      LAYER M4 ;
        RECT  86.316 80.88 86.4 80.904 ;
    END
  END r_len[4]
  PIN r_len[5]
    DIRECTION OUTPUT ;
    USE SIGNAL ;
    PORT
      LAYER M4 ;
        RECT  86.316 80.976 86.4 81 ;
    END
  END r_len[5]
  PIN r_len[6]
    DIRECTION OUTPUT ;
    USE SIGNAL ;
    PORT
      LAYER M4 ;
        RECT  86.316 81.072 86.4 81.096 ;
    END
  END r_len[6]
  PIN r_len[7]
    DIRECTION OUTPUT ;
    USE SIGNAL ;
    PORT
      LAYER M4 ;
        RECT  86.316 81.168 86.4 81.192 ;
    END
  END r_len[7]
  PIN r_len[8]
    DIRECTION OUTPUT ;
    USE SIGNAL ;
    PORT
      LAYER M4 ;
        RECT  86.316 81.264 86.4 81.288 ;
    END
  END r_len[8]
  PIN r_len[9]
    DIRECTION OUTPUT ;
    USE SIGNAL ;
    PORT
      LAYER M4 ;
        RECT  86.316 81.36 86.4 81.384 ;
    END
  END r_len[9]
  PIN r_row[0]
    DIRECTION OUTPUT ;
    USE SIGNAL ;
    PORT
      LAYER M4 ;
        RECT  86.316 75.504 86.4 75.528 ;
    END
  END r_row[0]
  PIN r_row[1]
    DIRECTION OUTPUT ;
    USE SIGNAL ;
    PORT
      LAYER M4 ;
        RECT  86.316 75.6 86.4 75.624 ;
    END
  END r_row[1]
  PIN r_row[2]
    DIRECTION OUTPUT ;
    USE SIGNAL ;
    PORT
      LAYER M4 ;
        RECT  86.316 75.696 86.4 75.72 ;
    END
  END r_row[2]
  PIN r_row[3]
    DIRECTION OUTPUT ;
    USE SIGNAL ;
    PORT
      LAYER M4 ;
        RECT  86.316 75.792 86.4 75.816 ;
    END
  END r_row[3]
  PIN r_row[4]
    DIRECTION OUTPUT ;
    USE SIGNAL ;
    PORT
      LAYER M4 ;
        RECT  86.316 75.888 86.4 75.912 ;
    END
  END r_row[4]
  PIN r_row[5]
    DIRECTION OUTPUT ;
    USE SIGNAL ;
    PORT
      LAYER M4 ;
        RECT  86.316 75.984 86.4 76.008 ;
    END
  END r_row[5]
  PIN r_row[6]
    DIRECTION OUTPUT ;
    USE SIGNAL ;
    PORT
      LAYER M4 ;
        RECT  86.316 76.08 86.4 76.104 ;
    END
  END r_row[6]
  PIN r_start
    DIRECTION OUTPUT ;
    USE SIGNAL ;
    PORT
      LAYER M4 ;
        RECT  86.316 79.536 86.4 79.56 ;
    END
  END r_start
  PIN r_we[0]
    DIRECTION OUTPUT ;
    USE SIGNAL ;
    PORT
      LAYER M4 ;
        RECT  86.316 78 86.4 78.024 ;
    END
  END r_we[0]
  PIN r_we[1]
    DIRECTION OUTPUT ;
    USE SIGNAL ;
    PORT
      LAYER M4 ;
        RECT  86.316 78.096 86.4 78.12 ;
    END
  END r_we[1]
  PIN r_we[2]
    DIRECTION OUTPUT ;
    USE SIGNAL ;
    PORT
      LAYER M4 ;
        RECT  86.316 78.192 86.4 78.216 ;
    END
  END r_we[2]
  PIN r_we[3]
    DIRECTION OUTPUT ;
    USE SIGNAL ;
    PORT
      LAYER M4 ;
        RECT  86.316 78.288 86.4 78.312 ;
    END
  END r_we[3]
  PIN rst_n
    DIRECTION INPUT ;
    USE SIGNAL ;
    PORT
      LAYER M4 ;
        RECT  0 74.064 0.084 74.088 ;
    END
    PORT
      LAYER M4 ;
        RECT  0.06 74.064 2.408 74.088 ;
    END
  END rst_n
  PIN start
    DIRECTION INPUT ;
    USE SIGNAL ;
    PORT
      LAYER M4 ;
        RECT  0 75.504 0.084 75.528 ;
    END
    PORT
      LAYER M4 ;
        RECT  0.06 75.504 2.408 75.528 ;
    END
  END start
  PIN VDD
    DIRECTION INOUT ;
    USE POWER ;
    PORT
      LAYER M5 ;
        RECT  83.592 2.151 83.712 84.249 ;
        RECT  78.192 2.151 78.312 84.249 ;
        RECT  72.792 2.151 72.912 84.249 ;
        RECT  67.392 2.151 67.512 84.249 ;
        RECT  61.992 2.151 62.112 84.249 ;
        RECT  56.592 2.151 56.712 84.249 ;
        RECT  51.192 2.151 51.312 84.249 ;
        RECT  45.792 2.151 45.912 84.249 ;
        RECT  40.392 2.151 40.512 84.249 ;
        RECT  34.992 2.151 35.112 84.249 ;
        RECT  29.592 2.151 29.712 84.249 ;
        RECT  24.192 2.151 24.312 84.249 ;
        RECT  18.792 2.151 18.912 84.249 ;
        RECT  13.392 2.151 13.512 84.249 ;
        RECT  7.992 2.151 8.112 84.249 ;
        RECT  2.592 2.151 2.712 84.249 ;
    END
  END VDD
  PIN VSS
    DIRECTION INOUT ;
    USE GROUND ;
    PORT
      LAYER M5 ;
        RECT  83.4 2.137 83.52 84.263 ;
        RECT  78 2.137 78.12 84.263 ;
        RECT  72.6 2.137 72.72 84.263 ;
        RECT  67.2 2.137 67.32 84.263 ;
        RECT  61.8 2.137 61.92 84.263 ;
        RECT  56.4 2.137 56.52 84.263 ;
        RECT  51 2.137 51.12 84.263 ;
        RECT  45.6 2.137 45.72 84.263 ;
        RECT  40.2 2.137 40.32 84.263 ;
        RECT  34.8 2.137 34.92 84.263 ;
        RECT  29.4 2.137 29.52 84.263 ;
        RECT  24 2.137 24.12 84.263 ;
        RECT  18.6 2.137 18.72 84.263 ;
        RECT  13.2 2.137 13.32 84.263 ;
        RECT  7.8 2.137 7.92 84.263 ;
        RECT  2.4 2.137 2.52 84.263 ;
    END
  END VSS
  # OT_OBS_CLOSED layer=M5 d_um=1.536 added=26
  OBS
    LAYER RVTN ;
     RECT  2.16 2.16 84.24 2.295 ;
     RECT  2.16 2.565 84.24 2.835 ;
     RECT  2.16 3.105 84.24 3.375 ;
     RECT  2.16 3.645 84.24 3.915 ;
     RECT  2.16 4.185 84.24 4.455 ;
     RECT  2.16 4.725 84.24 4.995 ;
     RECT  2.16 5.265 84.24 5.535 ;
     RECT  2.16 5.805 84.24 6.075 ;
     RECT  2.16 6.345 84.24 6.615 ;
     RECT  2.16 6.885 84.24 7.155 ;
     RECT  2.16 7.425 84.24 7.695 ;
     RECT  2.16 7.965 84.24 8.235 ;
     RECT  2.16 8.505 84.24 8.775 ;
     RECT  2.16 9.045 84.24 9.315 ;
     RECT  2.16 9.585 84.24 9.855 ;
     RECT  2.16 10.125 84.24 10.395 ;
     RECT  2.16 10.665 84.24 10.935 ;
     RECT  2.16 11.205 84.24 11.475 ;
     RECT  2.16 11.745 84.24 12.015 ;
     RECT  2.16 12.285 84.24 12.555 ;
     RECT  2.16 12.825 84.24 13.095 ;
     RECT  2.16 13.365 84.24 13.635 ;
     RECT  2.16 13.905 84.24 14.175 ;
     RECT  2.16 14.445 84.24 14.715 ;
     RECT  2.16 14.985 84.24 15.255 ;
     RECT  2.16 15.525 84.24 15.795 ;
     RECT  2.16 16.065 84.24 16.335 ;
     RECT  2.16 16.605 84.24 16.875 ;
     RECT  2.16 17.145 84.24 17.415 ;
     RECT  2.16 17.685 84.24 17.955 ;
     RECT  2.16 18.225 84.24 18.495 ;
     RECT  2.16 18.765 84.24 19.035 ;
     RECT  2.16 19.305 84.24 19.575 ;
     RECT  2.16 19.845 84.24 20.115 ;
     RECT  2.16 20.385 84.24 20.655 ;
     RECT  2.16 20.925 84.24 21.195 ;
     RECT  2.16 21.465 84.24 21.735 ;
     RECT  2.16 22.005 84.24 22.275 ;
     RECT  2.16 22.545 84.24 22.815 ;
     RECT  2.16 23.085 84.24 23.355 ;
     RECT  2.16 23.625 84.24 23.895 ;
     RECT  2.16 24.165 84.24 24.435 ;
     RECT  2.16 24.705 84.24 24.975 ;
     RECT  2.16 25.245 84.24 25.515 ;
     RECT  2.16 25.785 84.24 26.055 ;
     RECT  2.16 26.325 84.24 26.595 ;
     RECT  2.16 26.865 84.24 27.135 ;
     RECT  2.16 27.405 84.24 27.675 ;
     RECT  2.16 27.945 84.24 28.215 ;
     RECT  2.16 28.485 84.24 28.755 ;
     RECT  2.16 29.025 84.24 29.295 ;
     RECT  2.16 29.565 84.24 29.835 ;
     RECT  2.16 30.105 84.24 30.375 ;
     RECT  2.16 30.645 84.24 30.915 ;
     RECT  2.16 31.185 84.24 31.455 ;
     RECT  2.16 31.725 84.24 31.995 ;
     RECT  2.16 32.265 84.24 32.535 ;
     RECT  2.16 32.805 84.24 33.075 ;
     RECT  2.16 33.345 84.24 33.615 ;
     RECT  2.16 33.885 84.24 34.155 ;
     RECT  2.16 34.425 84.24 34.695 ;
     RECT  2.16 34.965 84.24 35.235 ;
     RECT  2.16 35.505 84.24 35.775 ;
     RECT  2.16 36.045 84.24 36.315 ;
     RECT  2.16 36.585 84.24 36.855 ;
     RECT  2.16 37.125 84.24 37.395 ;
     RECT  2.16 37.665 84.24 37.935 ;
     RECT  2.16 38.205 84.24 38.475 ;
     RECT  2.16 38.745 84.24 39.015 ;
     RECT  2.16 39.285 84.24 39.555 ;
     RECT  2.16 39.825 84.24 40.095 ;
     RECT  2.16 40.365 84.24 40.635 ;
     RECT  2.16 40.905 84.24 41.175 ;
     RECT  2.16 41.445 84.24 41.715 ;
     RECT  2.16 41.985 84.24 42.255 ;
     RECT  2.16 42.525 84.24 42.795 ;
     RECT  2.16 43.065 84.24 43.335 ;
     RECT  2.16 43.605 84.24 43.875 ;
     RECT  2.16 44.145 84.24 44.415 ;
     RECT  2.16 44.685 84.24 44.955 ;
     RECT  2.16 45.225 84.24 45.495 ;
     RECT  2.16 45.765 84.24 46.035 ;
     RECT  2.16 46.305 84.24 46.575 ;
     RECT  2.16 46.845 84.24 47.115 ;
     RECT  2.16 47.385 84.24 47.655 ;
     RECT  2.16 47.925 84.24 48.195 ;
     RECT  2.16 48.465 84.24 48.735 ;
     RECT  2.16 49.005 84.24 49.275 ;
     RECT  2.16 49.545 84.24 49.815 ;
     RECT  2.16 50.085 84.24 50.355 ;
     RECT  2.16 50.625 84.24 50.895 ;
     RECT  2.16 51.165 84.24 51.435 ;
     RECT  2.16 51.705 84.24 51.975 ;
     RECT  2.16 52.245 84.24 52.515 ;
     RECT  2.16 52.785 84.24 53.055 ;
     RECT  2.16 53.325 84.24 53.595 ;
     RECT  2.16 53.865 84.24 54.135 ;
     RECT  2.16 54.405 84.24 54.675 ;
     RECT  2.16 54.945 84.24 55.215 ;
     RECT  2.16 55.485 84.24 55.755 ;
     RECT  2.16 56.025 84.24 56.295 ;
     RECT  2.16 56.565 84.24 56.835 ;
     RECT  2.16 57.105 84.24 57.375 ;
     RECT  2.16 57.645 84.24 57.915 ;
     RECT  2.16 58.185 84.24 58.455 ;
     RECT  2.16 58.725 84.24 58.995 ;
     RECT  2.16 59.265 84.24 59.535 ;
     RECT  2.16 59.805 84.24 60.075 ;
     RECT  2.16 60.345 84.24 60.615 ;
     RECT  2.16 60.885 84.24 61.155 ;
     RECT  2.16 61.425 84.24 61.695 ;
     RECT  2.16 61.965 84.24 62.235 ;
     RECT  2.16 62.505 84.24 62.775 ;
     RECT  2.16 63.045 84.24 63.315 ;
     RECT  2.16 63.585 84.24 63.855 ;
     RECT  2.16 64.125 84.24 64.395 ;
     RECT  2.16 64.665 84.24 64.935 ;
     RECT  2.16 65.205 84.24 65.475 ;
     RECT  2.16 65.745 84.24 66.015 ;
     RECT  2.16 66.285 84.24 66.555 ;
     RECT  2.16 66.825 84.24 67.095 ;
     RECT  2.16 67.365 84.24 67.635 ;
     RECT  2.16 67.905 84.24 68.175 ;
     RECT  2.16 68.445 84.24 68.715 ;
     RECT  2.16 68.985 84.24 69.255 ;
     RECT  2.16 69.525 84.24 69.795 ;
     RECT  2.16 70.065 84.24 70.335 ;
     RECT  2.16 70.605 84.24 70.875 ;
     RECT  2.16 71.145 84.24 71.415 ;
     RECT  2.16 71.685 84.24 71.955 ;
     RECT  2.16 72.225 84.24 72.495 ;
     RECT  2.16 72.765 84.24 73.035 ;
     RECT  2.16 73.305 84.24 73.575 ;
     RECT  2.16 73.845 84.24 74.115 ;
     RECT  2.16 74.385 84.24 74.655 ;
     RECT  2.16 74.925 84.24 75.195 ;
     RECT  2.16 75.465 84.24 75.735 ;
     RECT  2.16 76.005 84.24 76.275 ;
     RECT  2.16 76.545 84.24 76.815 ;
     RECT  2.16 77.085 84.24 77.355 ;
     RECT  2.16 77.625 84.24 77.895 ;
     RECT  2.16 78.165 84.24 78.435 ;
     RECT  2.16 78.705 84.24 78.975 ;
     RECT  2.16 79.245 84.24 79.515 ;
     RECT  2.16 79.785 84.24 80.055 ;
     RECT  2.16 80.325 84.24 80.595 ;
     RECT  2.16 80.865 84.24 81.135 ;
     RECT  2.16 81.405 84.24 81.675 ;
     RECT  2.16 81.945 84.24 82.215 ;
     RECT  2.16 82.485 84.24 82.755 ;
     RECT  2.16 83.025 84.24 83.295 ;
     RECT  2.16 83.565 84.24 83.835 ;
     RECT  2.16 84.105 84.24 84.24 ;
    LAYER RVTP ;
     RECT  2.16 2.295 84.24 2.565 ;
     RECT  2.16 2.835 84.24 3.105 ;
     RECT  2.16 3.375 84.24 3.645 ;
     RECT  2.16 3.915 84.24 4.185 ;
     RECT  2.16 4.455 84.24 4.725 ;
     RECT  2.16 4.995 84.24 5.265 ;
     RECT  2.16 5.535 84.24 5.805 ;
     RECT  2.16 6.075 84.24 6.345 ;
     RECT  2.16 6.615 84.24 6.885 ;
     RECT  2.16 7.155 84.24 7.425 ;
     RECT  2.16 7.695 84.24 7.965 ;
     RECT  2.16 8.235 84.24 8.505 ;
     RECT  2.16 8.775 84.24 9.045 ;
     RECT  2.16 9.315 84.24 9.585 ;
     RECT  2.16 9.855 84.24 10.125 ;
     RECT  2.16 10.395 84.24 10.665 ;
     RECT  2.16 10.935 84.24 11.205 ;
     RECT  2.16 11.475 84.24 11.745 ;
     RECT  2.16 12.015 84.24 12.285 ;
     RECT  2.16 12.555 84.24 12.825 ;
     RECT  2.16 13.095 84.24 13.365 ;
     RECT  2.16 13.635 84.24 13.905 ;
     RECT  2.16 14.175 84.24 14.445 ;
     RECT  2.16 14.715 84.24 14.985 ;
     RECT  2.16 15.255 84.24 15.525 ;
     RECT  2.16 15.795 84.24 16.065 ;
     RECT  2.16 16.335 84.24 16.605 ;
     RECT  2.16 16.875 84.24 17.145 ;
     RECT  2.16 17.415 84.24 17.685 ;
     RECT  2.16 17.955 84.24 18.225 ;
     RECT  2.16 18.495 84.24 18.765 ;
     RECT  2.16 19.035 84.24 19.305 ;
     RECT  2.16 19.575 84.24 19.845 ;
     RECT  2.16 20.115 84.24 20.385 ;
     RECT  2.16 20.655 84.24 20.925 ;
     RECT  2.16 21.195 84.24 21.465 ;
     RECT  2.16 21.735 84.24 22.005 ;
     RECT  2.16 22.275 84.24 22.545 ;
     RECT  2.16 22.815 84.24 23.085 ;
     RECT  2.16 23.355 84.24 23.625 ;
     RECT  2.16 23.895 84.24 24.165 ;
     RECT  2.16 24.435 84.24 24.705 ;
     RECT  2.16 24.975 84.24 25.245 ;
     RECT  2.16 25.515 84.24 25.785 ;
     RECT  2.16 26.055 84.24 26.325 ;
     RECT  2.16 26.595 84.24 26.865 ;
     RECT  2.16 27.135 84.24 27.405 ;
     RECT  2.16 27.675 84.24 27.945 ;
     RECT  2.16 28.215 84.24 28.485 ;
     RECT  2.16 28.755 84.24 29.025 ;
     RECT  2.16 29.295 84.24 29.565 ;
     RECT  2.16 29.835 84.24 30.105 ;
     RECT  2.16 30.375 84.24 30.645 ;
     RECT  2.16 30.915 84.24 31.185 ;
     RECT  2.16 31.455 84.24 31.725 ;
     RECT  2.16 31.995 84.24 32.265 ;
     RECT  2.16 32.535 84.24 32.805 ;
     RECT  2.16 33.075 84.24 33.345 ;
     RECT  2.16 33.615 84.24 33.885 ;
     RECT  2.16 34.155 84.24 34.425 ;
     RECT  2.16 34.695 84.24 34.965 ;
     RECT  2.16 35.235 84.24 35.505 ;
     RECT  2.16 35.775 84.24 36.045 ;
     RECT  2.16 36.315 84.24 36.585 ;
     RECT  2.16 36.855 84.24 37.125 ;
     RECT  2.16 37.395 84.24 37.665 ;
     RECT  2.16 37.935 84.24 38.205 ;
     RECT  2.16 38.475 84.24 38.745 ;
     RECT  2.16 39.015 84.24 39.285 ;
     RECT  2.16 39.555 84.24 39.825 ;
     RECT  2.16 40.095 84.24 40.365 ;
     RECT  2.16 40.635 84.24 40.905 ;
     RECT  2.16 41.175 84.24 41.445 ;
     RECT  2.16 41.715 84.24 41.985 ;
     RECT  2.16 42.255 84.24 42.525 ;
     RECT  2.16 42.795 84.24 43.065 ;
     RECT  2.16 43.335 84.24 43.605 ;
     RECT  2.16 43.875 84.24 44.145 ;
     RECT  2.16 44.415 84.24 44.685 ;
     RECT  2.16 44.955 84.24 45.225 ;
     RECT  2.16 45.495 84.24 45.765 ;
     RECT  2.16 46.035 84.24 46.305 ;
     RECT  2.16 46.575 84.24 46.845 ;
     RECT  2.16 47.115 84.24 47.385 ;
     RECT  2.16 47.655 84.24 47.925 ;
     RECT  2.16 48.195 84.24 48.465 ;
     RECT  2.16 48.735 84.24 49.005 ;
     RECT  2.16 49.275 84.24 49.545 ;
     RECT  2.16 49.815 84.24 50.085 ;
     RECT  2.16 50.355 84.24 50.625 ;
     RECT  2.16 50.895 84.24 51.165 ;
     RECT  2.16 51.435 84.24 51.705 ;
     RECT  2.16 51.975 84.24 52.245 ;
     RECT  2.16 52.515 84.24 52.785 ;
     RECT  2.16 53.055 84.24 53.325 ;
     RECT  2.16 53.595 84.24 53.865 ;
     RECT  2.16 54.135 84.24 54.405 ;
     RECT  2.16 54.675 84.24 54.945 ;
     RECT  2.16 55.215 84.24 55.485 ;
     RECT  2.16 55.755 84.24 56.025 ;
     RECT  2.16 56.295 84.24 56.565 ;
     RECT  2.16 56.835 84.24 57.105 ;
     RECT  2.16 57.375 84.24 57.645 ;
     RECT  2.16 57.915 84.24 58.185 ;
     RECT  2.16 58.455 84.24 58.725 ;
     RECT  2.16 58.995 84.24 59.265 ;
     RECT  2.16 59.535 84.24 59.805 ;
     RECT  2.16 60.075 84.24 60.345 ;
     RECT  2.16 60.615 84.24 60.885 ;
     RECT  2.16 61.155 84.24 61.425 ;
     RECT  2.16 61.695 84.24 61.965 ;
     RECT  2.16 62.235 84.24 62.505 ;
     RECT  2.16 62.775 84.24 63.045 ;
     RECT  2.16 63.315 84.24 63.585 ;
     RECT  2.16 63.855 84.24 64.125 ;
     RECT  2.16 64.395 84.24 64.665 ;
     RECT  2.16 64.935 84.24 65.205 ;
     RECT  2.16 65.475 84.24 65.745 ;
     RECT  2.16 66.015 84.24 66.285 ;
     RECT  2.16 66.555 84.24 66.825 ;
     RECT  2.16 67.095 84.24 67.365 ;
     RECT  2.16 67.635 84.24 67.905 ;
     RECT  2.16 68.175 84.24 68.445 ;
     RECT  2.16 68.715 84.24 68.985 ;
     RECT  2.16 69.255 84.24 69.525 ;
     RECT  2.16 69.795 84.24 70.065 ;
     RECT  2.16 70.335 84.24 70.605 ;
     RECT  2.16 70.875 84.24 71.145 ;
     RECT  2.16 71.415 84.24 71.685 ;
     RECT  2.16 71.955 84.24 72.225 ;
     RECT  2.16 72.495 84.24 72.765 ;
     RECT  2.16 73.035 84.24 73.305 ;
     RECT  2.16 73.575 84.24 73.845 ;
     RECT  2.16 74.115 84.24 74.385 ;
     RECT  2.16 74.655 84.24 74.925 ;
     RECT  2.16 75.195 84.24 75.465 ;
     RECT  2.16 75.735 84.24 76.005 ;
     RECT  2.16 76.275 84.24 76.545 ;
     RECT  2.16 76.815 84.24 77.085 ;
     RECT  2.16 77.355 84.24 77.625 ;
     RECT  2.16 77.895 84.24 78.165 ;
     RECT  2.16 78.435 84.24 78.705 ;
     RECT  2.16 78.975 84.24 79.245 ;
     RECT  2.16 79.515 84.24 79.785 ;
     RECT  2.16 80.055 84.24 80.325 ;
     RECT  2.16 80.595 84.24 80.865 ;
     RECT  2.16 81.135 84.24 81.405 ;
     RECT  2.16 81.675 84.24 81.945 ;
     RECT  2.16 82.215 84.24 82.485 ;
     RECT  2.16 82.755 84.24 83.025 ;
     RECT  2.16 83.295 84.24 83.565 ;
     RECT  2.16 83.835 84.24 84.105 ;
    LAYER M1 ;
     RECT  2.16 2.151 84.24 84.249 ;
    LAYER M2 ;
     RECT  0.103 44.118 0.139 44.559 ;
     RECT  0.103 48.438 0.175 48.456 ;
     RECT  0.103 49.59 0.175 49.608 ;
     RECT  0.139 44.046 0.203 44.559 ;
     RECT  0.103 45.891 0.203 45.909 ;
     RECT  0.175 48.438 0.203 49.608 ;
     RECT  0.103 51.984 0.203 52.002 ;
     RECT  0.103 55.881 0.203 55.899 ;
     RECT  0.103 77.4 0.203 77.724 ;
     RECT  0.203 44.046 0.239 44.514 ;
     RECT  0.203 49.086 0.275 49.104 ;
     RECT  0.239 44.388 0.347 44.406 ;
     RECT  0.103 39.6 0.499 39.618 ;
     RECT  0.103 33.048 0.535 33.57 ;
     RECT  0.499 39.528 0.535 39.618 ;
     RECT  0.103 40.878 0.535 40.896 ;
     RECT  0.499 60.318 0.535 60.336 ;
     RECT  0.535 52.992 0.571 53.01 ;
     RECT  0.571 52.956 0.671 53.01 ;
     RECT  0.535 32.472 2.16 33.57 ;
     RECT  2.155 34.632 2.16 34.65 ;
     RECT  0.535 39.528 2.16 40.896 ;
     RECT  0.535 42.732 2.16 42.75 ;
     RECT  0.671 52.992 2.16 53.01 ;
     RECT  2.155 56.502 2.16 56.52 ;
     RECT  0.535 60.318 2.16 60.408 ;
     RECT  0.103 72.972 2.16 72.99 ;
     RECT  0.203 77.4 2.16 77.418 ;
     RECT  0.103 78.642 2.16 78.66 ;
     RECT  2.16 2.151 84.24 84.249 ;
     RECT  84.24 33.12 84.875 67.194 ;
     RECT  84.875 33.12 84.911 57.834 ;
     RECT  84.24 75.546 84.911 76.194 ;
     RECT  84.24 79.524 84.911 79.542 ;
     RECT  84.24 80.334 84.911 82.044 ;
     RECT  84.24 83.736 84.911 83.754 ;
     RECT  84.911 44.694 84.947 55.854 ;
     RECT  84.911 33.12 84.983 37.584 ;
     RECT  84.947 44.694 85.451 53.244 ;
     RECT  84.947 54.036 85.451 55.854 ;
     RECT  84.983 33.156 85.487 37.584 ;
     RECT  84.911 38.376 85.487 43.866 ;
     RECT  85.451 45 85.487 48.654 ;
     RECT  85.451 49.446 85.487 53.244 ;
     RECT  85.451 54.036 85.487 54.054 ;
     RECT  84.911 56.736 85.487 57.744 ;
     RECT  84.875 58.698 85.487 67.194 ;
     RECT  84.24 77.976 85.487 78.462 ;
     RECT  84.911 80.334 85.487 81.864 ;
     RECT  85.487 33.156 85.523 33.174 ;
     RECT  85.487 34.164 85.523 35.568 ;
     RECT  85.487 36.486 85.523 36.612 ;
     RECT  85.487 38.484 85.523 40.392 ;
     RECT  85.487 41.184 85.523 41.544 ;
     RECT  85.487 49.716 85.523 51.93 ;
     RECT  85.487 52.866 85.523 52.884 ;
     RECT  85.487 56.844 85.523 57.402 ;
     RECT  85.487 62.406 85.523 65.538 ;
     RECT  85.487 77.976 85.523 78.084 ;
     RECT  85.487 80.496 85.523 81.234 ;
     RECT  85.487 45.036 85.559 45.054 ;
     RECT  85.487 46.386 85.595 47.529 ;
     RECT  85.487 58.698 85.631 61.524 ;
     RECT  85.631 58.698 85.667 60.03 ;
     RECT  85.667 58.698 86.035 59.562 ;
     RECT  85.523 39.024 86.171 39.312 ;
     RECT  86.035 58.158 86.207 59.562 ;
     RECT  86.207 58.158 86.243 59.022 ;
     RECT  85.523 63.09 86.243 65.538 ;
     RECT  85.487 66.366 86.243 67.194 ;
     RECT  85.523 34.164 86.279 34.758 ;
     RECT  85.523 51.066 86.279 51.93 ;
     RECT  86.243 58.626 86.279 59.022 ;
     RECT  86.243 66.366 86.279 67.086 ;
     RECT  86.279 34.164 86.315 34.182 ;
     RECT  85.523 36.594 86.315 36.612 ;
     RECT  86.171 39.294 86.315 39.312 ;
     RECT  85.523 40.374 86.315 40.392 ;
     RECT  85.523 41.526 86.315 41.544 ;
     RECT  85.487 42.696 86.315 43.866 ;
     RECT  85.595 46.386 86.315 47.034 ;
     RECT  86.279 51.066 86.315 51.084 ;
     RECT  86.279 51.912 86.315 51.93 ;
     RECT  85.451 54.99 86.315 55.854 ;
     RECT  85.523 57.384 86.315 57.402 ;
     RECT  86.279 59.004 86.315 59.022 ;
     RECT  85.631 60.966 86.315 61.524 ;
     RECT  86.243 63.252 86.315 65.538 ;
     RECT  86.279 66.366 86.315 67.014 ;
     RECT  84.911 75.672 86.315 76.104 ;
     RECT  85.523 78.066 86.315 78.084 ;
     RECT  85.523 81.216 86.315 81.234 ;
    LAYER M3 ;
     RECT  2.415 2.143 2.505 2.413 ;
     RECT  7.815 2.143 7.905 2.413 ;
     RECT  13.215 2.143 13.305 2.413 ;
     RECT  18.615 2.143 18.705 2.413 ;
     RECT  24.015 2.143 24.105 2.413 ;
     RECT  29.415 2.143 29.505 2.413 ;
     RECT  34.815 2.143 34.905 2.413 ;
     RECT  40.215 2.143 40.305 2.413 ;
     RECT  45.615 2.143 45.705 2.413 ;
     RECT  51.015 2.143 51.105 2.413 ;
     RECT  56.415 2.143 56.505 2.413 ;
     RECT  61.815 2.143 61.905 2.413 ;
     RECT  67.215 2.143 67.305 2.413 ;
     RECT  72.615 2.143 72.705 2.413 ;
     RECT  78.015 2.143 78.105 2.413 ;
     RECT  83.415 2.143 83.505 2.413 ;
     RECT  2.415 2.413 2.697 32.611 ;
     RECT  7.815 2.413 8.097 32.611 ;
     RECT  2.415 32.611 3.222 32.683 ;
     RECT  5.94 32.701 5.958 32.809 ;
     RECT  0.54 32.467 0.558 32.813 ;
     RECT  3.996 32.467 4.014 32.845 ;
     RECT  2.304 32.683 3.222 32.875 ;
     RECT  7.092 32.611 8.097 33.007 ;
     RECT  2.304 32.875 3.258 33.043 ;
     RECT  3.996 32.845 4.518 33.043 ;
     RECT  40.215 2.413 40.497 33.043 ;
     RECT  78.015 2.413 78.297 33.079 ;
     RECT  83.415 2.413 83.697 33.079 ;
     RECT  42.192 32.809 42.21 33.115 ;
     RECT  80.964 33.079 81.198 33.115 ;
     RECT  2.304 33.043 4.518 33.151 ;
     RECT  5.508 32.809 5.958 33.151 ;
     RECT  42.192 33.115 42.57 33.151 ;
     RECT  77.436 33.079 78.39 33.151 ;
     RECT  79.416 32.971 79.434 33.151 ;
     RECT  82.98 33.079 83.697 33.151 ;
     RECT  84.96 33.115 84.978 33.151 ;
     RECT  2.304 33.151 6.138 33.179 ;
     RECT  6.876 33.007 8.097 33.241 ;
     RECT  84.96 33.151 85.518 33.241 ;
     RECT  42.192 33.151 43.074 33.269 ;
     RECT  44.64 32.773 44.658 33.277 ;
     RECT  74.664 33.079 74.682 33.277 ;
     RECT  79.416 33.151 79.938 33.313 ;
     RECT  10.836 33.241 10.854 33.349 ;
     RECT  80.964 33.115 81.45 33.385 ;
     RECT  82.584 33.151 83.697 33.385 ;
     RECT  6.876 33.241 8.154 33.389 ;
     RECT  9.108 33.151 9.126 33.413 ;
     RECT  77.364 33.151 78.39 33.421 ;
     RECT  79.236 33.313 79.938 33.421 ;
     RECT  80.964 33.385 83.697 33.421 ;
     RECT  44.64 33.277 44.766 33.449 ;
     RECT  76.392 32.971 76.41 33.449 ;
     RECT  4.392 33.179 6.138 33.547 ;
     RECT  77.364 33.421 83.898 33.619 ;
     RECT  84.852 33.241 85.518 33.619 ;
     RECT  0.108 33.043 0.198 33.643 ;
     RECT  7.704 33.389 8.154 33.655 ;
     RECT  74.664 33.277 74.754 33.655 ;
     RECT  0.108 33.643 0.342 33.677 ;
     RECT  77.364 33.619 85.518 33.691 ;
     RECT  0.324 33.677 0.342 33.773 ;
     RECT  41.328 33.655 41.346 33.853 ;
     RECT  42.192 33.269 43.038 33.853 ;
     RECT  74.664 33.655 74.826 33.881 ;
     RECT  44.316 33.889 44.334 33.925 ;
     RECT  10.8 33.349 10.854 33.961 ;
     RECT  2.304 33.179 3.258 34.027 ;
     RECT  41.328 33.853 43.038 34.051 ;
     RECT  43.884 33.925 44.334 34.051 ;
     RECT  77.22 33.691 85.518 34.051 ;
     RECT  39.924 33.043 40.497 34.079 ;
     RECT  41.328 34.051 44.334 34.079 ;
     RECT  77.112 34.051 85.518 34.079 ;
     RECT  4.392 33.547 6.678 34.087 ;
     RECT  10.764 33.961 10.854 34.115 ;
     RECT  3.996 34.087 6.678 34.123 ;
     RECT  7.704 33.655 8.298 34.123 ;
     RECT  10.8 34.115 10.854 34.151 ;
     RECT  42.336 34.079 44.334 34.151 ;
     RECT  77.112 34.079 79.542 34.157 ;
     RECT  38.808 34.087 38.826 34.187 ;
     RECT  42.804 34.151 44.334 34.231 ;
     RECT  3.996 34.123 8.298 34.259 ;
     RECT  2.268 34.027 3.258 34.349 ;
     RECT  42.804 34.231 44.406 34.349 ;
     RECT  77.112 34.157 78.714 34.349 ;
     RECT  80.46 34.079 85.518 34.349 ;
     RECT  77.112 34.349 78.462 34.493 ;
     RECT  75.96 34.159 75.978 34.529 ;
     RECT  77.112 34.493 78.297 34.591 ;
     RECT  2.268 34.349 3.186 34.603 ;
     RECT  4.068 34.259 8.298 34.619 ;
     RECT  82.764 34.349 85.518 34.619 ;
     RECT  2.16 34.603 3.186 34.655 ;
     RECT  7.128 34.619 8.298 34.691 ;
     RECT  86.292 34.159 86.31 34.732 ;
     RECT  86.256 34.732 86.31 34.733 ;
     RECT  10.8 34.151 10.818 34.763 ;
     RECT  7.2 34.691 8.298 34.771 ;
     RECT  9.108 34.429 9.126 34.771 ;
     RECT  76.968 34.591 78.297 34.889 ;
     RECT  42.804 34.349 44.226 34.969 ;
     RECT  74.664 33.881 74.682 34.969 ;
     RECT  42.768 34.969 44.226 35.005 ;
     RECT  7.2 34.771 9.126 35.041 ;
     RECT  2.268 34.655 3.186 35.117 ;
     RECT  86.256 34.733 86.274 35.117 ;
     RECT  2.304 35.117 3.186 35.131 ;
     RECT  4.068 34.619 6.03 35.131 ;
     RECT  40.215 34.079 40.497 35.167 ;
     RECT  79.524 34.157 79.542 35.167 ;
     RECT  80.46 34.349 82.026 35.167 ;
     RECT  74.664 34.969 74.826 35.195 ;
     RECT  40.215 35.167 41.13 35.203 ;
     RECT  7.2 35.041 9.342 35.231 ;
     RECT  74.664 35.195 74.754 35.267 ;
     RECT  42.588 35.005 44.226 35.311 ;
     RECT  77.112 34.889 78.297 35.311 ;
     RECT  79.524 35.167 82.026 35.311 ;
     RECT  10.908 35.131 10.998 35.339 ;
     RECT  2.304 35.131 6.03 35.357 ;
     RECT  39.924 35.203 41.13 35.429 ;
     RECT  46.728 34.627 46.746 35.437 ;
     RECT  40.215 35.429 41.13 35.501 ;
     RECT  46.728 35.437 46.818 35.509 ;
     RECT  77.112 35.311 82.026 35.537 ;
     RECT  42.192 35.311 44.226 35.581 ;
     RECT  77.148 35.537 82.026 35.581 ;
     RECT  82.8 34.619 85.518 35.581 ;
     RECT  0.144 35.515 0.162 35.693 ;
     RECT  77.148 35.581 85.518 35.693 ;
     RECT  46.728 35.509 46.89 35.699 ;
     RECT  42.192 35.581 44.37 35.707 ;
     RECT  77.148 35.693 85.482 35.741 ;
     RECT  72.615 2.413 72.897 35.743 ;
     RECT  42.192 35.707 44.406 35.771 ;
     RECT  46.656 35.707 46.674 35.807 ;
     RECT  74.736 35.267 74.754 35.843 ;
     RECT  4.14 35.357 6.03 35.851 ;
     RECT  77.22 35.741 85.482 35.879 ;
     RECT  38.772 35.545 38.79 35.941 ;
     RECT  42.192 35.771 44.37 35.969 ;
     RECT  72.396 35.743 72.897 35.969 ;
     RECT  42.192 35.969 43.866 35.977 ;
     RECT  7.815 35.231 8.766 36.013 ;
     RECT  77.796 35.879 85.482 36.077 ;
     RECT  7.815 36.013 9.126 36.211 ;
     RECT  42.048 35.977 43.866 36.239 ;
     RECT  2.304 35.357 3.078 36.331 ;
     RECT  77.796 36.077 79.65 36.347 ;
     RECT  80.388 36.077 85.482 36.383 ;
     RECT  4.14 35.851 7.074 36.391 ;
     RECT  7.815 36.211 9.414 36.419 ;
     RECT  10.836 36.247 10.854 36.419 ;
     RECT  80.64 36.383 85.482 36.481 ;
     RECT  79.488 36.347 79.65 36.509 ;
     RECT  3.996 36.391 7.074 36.517 ;
     RECT  7.815 36.419 8.91 36.517 ;
     RECT  40.215 35.501 41.058 36.553 ;
     RECT  80.64 36.481 85.518 36.581 ;
     RECT  38.772 35.941 38.826 36.589 ;
     RECT  86.292 36.523 86.31 36.617 ;
     RECT  76.824 36.616 76.842 36.625 ;
     RECT  76.824 36.625 77.058 36.662 ;
     RECT  83.124 36.581 85.518 36.689 ;
     RECT  2.304 36.331 3.222 36.715 ;
     RECT  39.924 36.553 41.058 36.787 ;
     RECT  74.664 36.049 74.682 36.787 ;
     RECT  76.86 36.662 77.058 36.823 ;
     RECT  77.796 36.347 78.75 36.823 ;
     RECT  79.632 36.509 79.65 36.823 ;
     RECT  9.684 36.661 9.738 36.86 ;
     RECT  2.268 36.715 3.222 36.887 ;
     RECT  39.924 36.787 41.166 36.887 ;
     RECT  2.304 36.887 3.222 36.895 ;
     RECT  3.996 36.517 8.91 36.895 ;
     RECT  2.304 36.895 8.91 36.923 ;
     RECT  83.232 36.689 85.518 36.941 ;
     RECT  9.684 36.86 9.702 37.049 ;
     RECT  42.372 36.239 43.866 37.093 ;
     RECT  41.976 37.093 43.866 37.129 ;
     RECT  76.86 36.823 78.75 37.165 ;
     RECT  79.632 36.823 79.722 37.165 ;
     RECT  80.64 36.581 82.314 37.165 ;
     RECT  3.672 36.923 8.91 37.181 ;
     RECT  7.815 37.181 8.91 37.201 ;
     RECT  41.904 37.129 43.866 37.201 ;
     RECT  45.615 2.413 45.897 37.201 ;
     RECT  39.924 36.887 41.094 37.229 ;
     RECT  76.86 37.165 78.822 37.229 ;
     RECT  3.672 37.181 7.074 37.319 ;
     RECT  7.815 37.201 9.09 37.319 ;
     RECT  39.924 37.229 41.058 37.319 ;
     RECT  41.904 37.201 44.334 37.319 ;
     RECT  42.192 37.319 42.786 37.355 ;
     RECT  43.596 37.319 44.334 37.355 ;
     RECT  76.932 37.229 78.822 37.355 ;
     RECT  38.772 36.589 38.862 37.391 ;
     RECT  45.615 37.201 46.566 37.399 ;
     RECT  78.015 37.355 78.822 37.399 ;
     RECT  5.328 37.319 7.074 37.427 ;
     RECT  40.215 37.319 41.058 37.427 ;
     RECT  45.615 37.399 46.638 37.427 ;
     RECT  78.015 37.399 78.894 37.429 ;
     RECT  79.632 37.165 82.314 37.429 ;
     RECT  38.772 37.391 38.79 37.463 ;
     RECT  5.328 37.427 5.886 37.499 ;
     RECT  7.815 37.319 8.658 37.499 ;
     RECT  46.62 37.427 46.638 37.499 ;
     RECT  10.8 37.363 10.818 37.589 ;
     RECT  78.015 37.429 82.314 37.589 ;
     RECT  5.436 37.499 5.886 37.661 ;
     RECT  42.192 37.355 42.714 37.661 ;
     RECT  78.015 37.589 79.722 37.709 ;
     RECT  2.304 36.923 2.934 37.741 ;
     RECT  3.672 37.319 4.59 37.741 ;
     RECT  7.815 37.499 8.406 37.859 ;
     RECT  43.596 37.355 43.938 37.859 ;
     RECT  7.815 37.859 8.226 37.895 ;
     RECT  74.664 36.787 74.754 37.939 ;
     RECT  46.656 37.867 46.674 37.975 ;
     RECT  46.656 37.975 46.746 38.039 ;
     RECT  78.015 37.709 79.65 38.129 ;
     RECT  83.232 36.941 85.482 38.129 ;
     RECT  76.932 37.355 77.058 38.2 ;
     RECT  43.704 37.859 43.938 38.209 ;
     RECT  76.932 38.2 77.166 38.237 ;
     RECT  5.508 37.661 5.886 38.245 ;
     RECT  6.624 37.427 7.074 38.245 ;
     RECT  46.728 38.039 46.746 38.245 ;
     RECT  74.124 37.939 74.754 38.245 ;
     RECT  77.148 38.237 77.166 38.245 ;
     RECT  80.568 37.589 82.314 38.245 ;
     RECT  83.232 38.129 84.402 38.245 ;
     RECT  85.428 38.129 85.482 38.347 ;
     RECT  0.144 38.203 0.162 38.381 ;
     RECT  43.704 38.209 44.262 38.399 ;
     RECT  7.815 37.895 8.154 38.435 ;
     RECT  5.508 38.245 7.074 38.443 ;
     RECT  40.215 37.427 40.497 38.443 ;
     RECT  5.436 38.443 7.074 38.471 ;
     RECT  80.568 38.245 84.402 38.477 ;
     RECT  6.372 38.471 7.074 38.479 ;
     RECT  7.815 38.435 8.097 38.479 ;
     RECT  46.728 38.245 46.818 38.507 ;
     RECT  77.148 38.245 77.238 38.515 ;
     RECT  77.148 38.515 77.274 38.551 ;
     RECT  78.015 38.129 79.542 38.551 ;
     RECT  80.568 38.477 84.366 38.551 ;
     RECT  74.124 38.245 74.826 38.579 ;
     RECT  5.436 38.471 5.454 38.641 ;
     RECT  2.304 37.741 4.59 38.669 ;
     RECT  6.372 38.479 8.097 38.669 ;
     RECT  43.704 38.399 43.83 38.669 ;
     RECT  74.736 38.579 74.826 38.669 ;
     RECT  41.436 38.245 41.454 38.677 ;
     RECT  2.304 38.669 2.697 38.705 ;
     RECT  3.996 38.669 4.59 38.705 ;
     RECT  6.624 38.669 7.074 38.705 ;
     RECT  6.66 38.705 7.074 38.717 ;
     RECT  85.428 38.347 85.518 38.731 ;
     RECT  46.728 38.507 46.746 38.741 ;
     RECT  2.34 38.705 2.697 38.752 ;
     RECT  5.364 38.641 5.454 38.813 ;
     RECT  80.388 38.551 84.366 38.813 ;
     RECT  41.436 38.677 41.634 38.821 ;
     RECT  42.372 37.661 42.714 38.821 ;
     RECT  77.148 38.551 79.542 38.911 ;
     RECT  4.032 38.705 4.59 38.939 ;
     RECT  41.436 38.821 42.966 38.939 ;
     RECT  80.784 38.813 84.366 38.939 ;
     RECT  85.428 38.731 86.166 39.047 ;
     RECT  77.148 38.911 79.866 39.083 ;
     RECT  42.228 38.939 42.246 39.119 ;
     RECT  74.736 38.669 74.754 39.119 ;
     RECT  40.215 38.443 40.554 39.209 ;
     RECT  82.008 38.939 84.366 39.209 ;
     RECT  41.436 38.939 41.454 39.281 ;
     RECT  82.008 39.209 82.206 39.317 ;
     RECT  86.292 39.115 86.31 39.317 ;
     RECT  83.052 39.209 84.366 39.325 ;
     RECT  85.428 39.047 85.518 39.325 ;
     RECT  77.148 39.083 79.47 39.341 ;
     RECT  83.052 39.325 85.518 39.437 ;
     RECT  43.38 39.289 43.398 39.479 ;
     RECT  80.784 38.939 81.162 39.479 ;
     RECT  75.816 38.947 75.834 39.487 ;
     RECT  83.052 39.437 84.366 39.551 ;
     RECT  0.504 39.523 0.522 39.595 ;
     RECT  2.376 38.752 2.697 39.595 ;
     RECT  5.58 39.355 5.598 39.631 ;
     RECT  6.84 38.717 6.858 39.631 ;
     RECT  80.64 39.559 80.658 39.631 ;
     RECT  80.532 39.631 80.658 39.659 ;
     RECT  80.532 39.659 80.55 39.749 ;
     RECT  82.008 39.317 82.098 39.749 ;
     RECT  83.052 39.551 83.754 39.749 ;
     RECT  4.032 38.939 4.05 39.757 ;
     RECT  3.924 39.757 4.05 39.784 ;
     RECT  3.924 39.784 4.194 39.821 ;
     RECT  85.464 39.437 85.518 39.821 ;
     RECT  2.304 39.595 2.697 39.857 ;
     RECT  75.816 39.487 76.41 39.857 ;
     RECT  5.58 39.631 6.858 39.901 ;
     RECT  5.04 39.901 6.858 39.991 ;
     RECT  7.815 38.669 8.097 39.991 ;
     RECT  0.108 39.595 0.522 40.013 ;
     RECT  46.728 39.901 46.746 40.019 ;
     RECT  2.376 39.857 2.697 40.027 ;
     RECT  3.924 39.821 4.086 40.135 ;
     RECT  42.84 39.901 42.858 40.171 ;
     RECT  41.436 40.027 41.454 40.261 ;
     RECT  81.504 39.901 81.522 40.289 ;
     RECT  0.144 40.013 0.522 40.297 ;
     RECT  42.516 40.171 42.858 40.297 ;
     RECT  72.615 35.969 72.897 40.297 ;
     RECT  38.808 40.261 38.826 40.361 ;
     RECT  9.252 40.261 9.27 40.369 ;
     RECT  77.148 39.341 79.362 40.405 ;
     RECT  2.376 40.027 2.826 40.441 ;
     RECT  3.852 40.135 4.086 40.441 ;
     RECT  83.052 39.749 83.697 40.441 ;
     RECT  85.464 39.821 85.482 40.441 ;
     RECT  9.252 40.369 9.342 40.469 ;
     RECT  76.392 39.857 76.41 40.469 ;
     RECT  41.436 40.261 41.634 40.531 ;
     RECT  82.368 40.441 83.697 40.531 ;
     RECT  84.924 40.441 85.482 40.531 ;
     RECT  2.376 40.441 4.086 40.555 ;
     RECT  5.04 39.991 8.406 40.555 ;
     RECT  72.615 40.297 73.566 40.559 ;
     RECT  10.836 40.297 10.854 40.567 ;
     RECT  0.144 40.297 0.558 40.589 ;
     RECT  2.376 40.555 8.406 40.603 ;
     RECT  9.252 40.469 9.27 40.603 ;
     RECT  80.928 40.405 80.946 40.603 ;
     RECT  2.376 40.603 9.27 40.631 ;
     RECT  74.664 39.901 74.754 40.639 ;
     RECT  2.376 40.631 8.19 40.675 ;
     RECT  8.964 40.631 9.27 40.739 ;
     RECT  2.34 40.675 8.19 40.747 ;
     RECT  10.8 40.567 10.854 40.829 ;
     RECT  41.4 40.531 41.634 40.829 ;
     RECT  42.516 40.297 43.578 40.873 ;
     RECT  82.368 40.531 85.482 40.873 ;
     RECT  42.516 40.873 43.794 40.909 ;
     RECT  42.048 40.909 43.794 40.981 ;
     RECT  77.148 40.405 79.434 41.071 ;
     RECT  80.316 40.603 80.946 41.071 ;
     RECT  2.304 40.747 8.19 41.099 ;
     RECT  42.048 40.981 44.154 41.099 ;
     RECT  40.215 39.209 40.497 41.107 ;
     RECT  76.968 41.071 79.434 41.107 ;
     RECT  80.208 41.071 80.946 41.107 ;
     RECT  6.948 41.099 8.19 41.135 ;
     RECT  42.084 41.099 44.154 41.135 ;
     RECT  0.108 40.873 0.126 41.165 ;
     RECT  1.152 41.035 1.17 41.165 ;
     RECT  81.72 40.873 85.482 41.165 ;
     RECT  84.888 41.165 85.482 41.179 ;
     RECT  10.836 40.829 10.854 41.207 ;
     RECT  74.664 40.639 74.79 41.215 ;
     RECT  9.216 40.739 9.27 41.369 ;
     RECT  42.084 41.135 43.614 41.369 ;
     RECT  76.968 41.107 80.946 41.369 ;
     RECT  74.664 41.215 74.826 41.513 ;
     RECT  9.252 41.369 9.27 41.549 ;
     RECT  77.076 41.369 80.946 41.563 ;
     RECT  2.304 41.099 3.618 41.611 ;
     RECT  4.356 41.099 5.778 41.639 ;
     RECT  77.076 41.563 80.982 41.639 ;
     RECT  86.292 40.369 86.31 41.645 ;
     RECT  2.268 41.611 3.618 41.675 ;
     RECT  4.356 41.639 4.482 41.741 ;
     RECT  84.888 41.179 85.518 41.837 ;
     RECT  2.304 41.675 3.618 41.881 ;
     RECT  4.356 41.741 4.374 41.881 ;
     RECT  6.948 41.135 8.097 41.881 ;
     RECT  40.215 41.107 41.13 41.917 ;
     RECT  42.084 41.369 43.362 41.917 ;
     RECT  74.664 41.513 74.754 41.917 ;
     RECT  6.948 41.881 8.37 41.947 ;
     RECT  84.888 41.837 85.482 42.089 ;
     RECT  1.152 41.947 1.17 42.125 ;
     RECT  40.215 41.917 43.362 42.139 ;
     RECT  5.472 41.639 5.778 42.151 ;
     RECT  38.772 42.025 38.79 42.179 ;
     RECT  40.215 42.139 43.434 42.179 ;
     RECT  74.124 41.917 74.754 42.179 ;
     RECT  81.72 41.165 83.898 42.179 ;
     RECT  77.076 41.639 79.578 42.223 ;
     RECT  80.424 41.639 80.982 42.223 ;
     RECT  81.72 42.179 82.35 42.223 ;
     RECT  40.215 42.179 41.67 42.529 ;
     RECT  39.924 42.529 41.67 42.557 ;
     RECT  5.472 42.151 5.922 42.565 ;
     RECT  46.656 42.457 46.674 42.565 ;
     RECT  74.124 42.179 74.682 42.593 ;
     RECT  2.304 41.881 4.374 42.601 ;
     RECT  5.472 42.565 5.994 42.601 ;
     RECT  76.968 42.223 79.578 42.601 ;
     RECT  80.424 42.223 82.35 42.601 ;
     RECT  83.34 42.179 83.898 42.605 ;
     RECT  74.124 42.593 74.142 42.629 ;
     RECT  6.84 41.947 8.37 42.691 ;
     RECT  83.34 42.605 83.718 42.719 ;
     RECT  2.304 42.601 4.482 42.755 ;
     RECT  0.54 42.727 0.558 42.797 ;
     RECT  5.4 42.601 5.994 42.835 ;
     RECT  39.924 42.557 40.497 42.863 ;
     RECT  6.84 42.691 8.406 42.871 ;
     RECT  9.18 42.223 9.198 42.871 ;
     RECT  84.924 42.089 85.482 42.871 ;
     RECT  10.8 42.799 10.818 42.961 ;
     RECT  2.304 42.755 3.438 42.989 ;
     RECT  5.364 42.835 5.994 42.989 ;
     RECT  6.768 42.871 9.198 42.989 ;
     RECT  46.656 42.565 46.746 43.025 ;
     RECT  4.248 42.755 4.482 43.033 ;
     RECT  72.615 40.559 72.897 43.033 ;
     RECT  42.408 42.179 43.146 43.051 ;
     RECT  10.8 42.961 10.998 43.069 ;
     RECT  84.924 42.871 85.518 43.069 ;
     RECT  84.888 43.069 85.518 43.085 ;
     RECT  41.616 42.557 41.67 43.105 ;
     RECT  42.408 43.051 43.218 43.105 ;
     RECT  76.968 42.601 82.35 43.105 ;
     RECT  9.072 42.989 9.198 43.133 ;
     RECT  10.764 43.069 10.998 43.169 ;
     RECT  41.616 43.105 43.218 43.231 ;
     RECT  56.415 2.413 56.697 43.231 ;
     RECT  67.215 2.413 67.497 43.231 ;
     RECT  56.304 43.231 56.697 43.277 ;
     RECT  67.104 43.231 67.497 43.277 ;
     RECT  10.908 43.169 10.998 43.295 ;
     RECT  41.616 43.231 43.326 43.325 ;
     RECT  83.415 42.719 83.718 43.339 ;
     RECT  84.888 43.085 85.482 43.339 ;
     RECT  6.768 42.989 8.226 43.387 ;
     RECT  72.615 43.033 73.566 43.439 ;
     RECT  83.415 43.339 85.482 43.469 ;
     RECT  46.728 43.025 46.746 43.529 ;
     RECT  4.248 43.033 4.626 43.645 ;
     RECT  5.364 42.989 5.778 43.645 ;
     RECT  9.072 43.133 9.126 43.673 ;
     RECT  74.664 43.411 74.754 43.673 ;
     RECT  76.968 43.105 82.674 43.681 ;
     RECT  83.415 43.469 84.438 43.681 ;
     RECT  2.304 42.989 3.402 43.771 ;
     RECT  4.248 43.645 5.778 43.771 ;
     RECT  6.516 43.387 8.226 43.771 ;
     RECT  46.764 43.681 46.782 43.799 ;
     RECT  74.664 43.673 74.682 43.799 ;
     RECT  41.616 43.325 42.822 43.835 ;
     RECT  41.616 43.835 42.282 43.871 ;
     RECT  2.304 43.771 8.226 43.915 ;
     RECT  86.292 42.691 86.31 43.949 ;
     RECT  0.144 44.011 0.162 44.041 ;
     RECT  2.304 43.915 8.37 44.069 ;
     RECT  76.968 43.681 84.438 44.069 ;
     RECT  76.968 44.069 80.946 44.077 ;
     RECT  0.144 44.041 0.234 44.092 ;
     RECT  0.108 44.092 0.234 44.107 ;
     RECT  81.72 44.069 82.674 44.141 ;
     RECT  76.896 44.077 80.946 44.177 ;
     RECT  9.252 43.951 9.342 44.213 ;
     RECT  38.88 44.149 38.898 44.221 ;
     RECT  43.884 43.375 44.01 44.221 ;
     RECT  10.908 44.149 10.926 44.249 ;
     RECT  0.108 44.107 0.342 44.299 ;
     RECT  83.415 44.069 84.438 44.299 ;
     RECT  85.464 43.469 85.482 44.299 ;
     RECT  76.968 44.177 80.946 44.339 ;
     RECT  81.72 44.141 82.35 44.339 ;
     RECT  81.792 44.339 82.35 44.375 ;
     RECT  76.968 44.339 80.91 44.411 ;
     RECT  0.108 44.299 0.378 44.429 ;
     RECT  2.304 44.069 8.262 44.447 ;
     RECT  43.128 44.077 43.146 44.491 ;
     RECT  43.884 44.221 44.082 44.491 ;
     RECT  0.108 44.429 0.234 44.519 ;
     RECT  38.808 44.221 38.898 44.608 ;
     RECT  3.672 44.447 8.262 44.609 ;
     RECT  43.128 44.491 44.19 44.609 ;
     RECT  41.652 43.871 42.282 44.653 ;
     RECT  43.128 44.609 44.046 44.653 ;
     RECT  38.808 44.608 38.934 44.689 ;
     RECT  76.968 44.411 80.802 44.717 ;
     RECT  74.664 44.683 74.682 44.725 ;
     RECT  38.772 44.689 38.934 44.753 ;
     RECT  41.652 44.653 44.046 44.753 ;
     RECT  0.108 44.519 0.198 44.765 ;
     RECT  10.728 44.689 10.818 44.789 ;
     RECT  0.108 44.765 0.126 44.813 ;
     RECT  41.652 44.753 42.39 44.851 ;
     RECT  10.8 44.789 10.818 44.879 ;
     RECT  38.772 44.753 38.79 44.879 ;
     RECT  74.664 44.725 74.754 44.879 ;
     RECT  6.516 44.609 8.262 44.887 ;
     RECT  83.415 44.299 85.482 44.887 ;
     RECT  40.215 42.863 40.497 44.923 ;
     RECT  74.664 44.879 74.682 44.957 ;
     RECT  83.232 44.887 85.482 45.005 ;
     RECT  39.924 44.923 40.497 45.019 ;
     RECT  41.616 44.851 42.39 45.019 ;
     RECT  46.656 44.851 46.674 45.023 ;
     RECT  83.415 45.005 85.482 45.031 ;
     RECT  6.516 44.887 8.478 45.059 ;
     RECT  6.588 45.059 8.478 45.149 ;
     RECT  9.252 44.213 9.27 45.149 ;
     RECT  39.924 45.019 42.39 45.149 ;
     RECT  81.828 44.375 82.35 45.149 ;
     RECT  77.04 44.717 80.802 45.211 ;
     RECT  39.924 45.149 40.59 45.221 ;
     RECT  2.304 44.447 2.898 45.229 ;
     RECT  3.672 44.609 5.562 45.229 ;
     RECT  2.304 45.229 5.562 45.257 ;
     RECT  39.996 45.221 40.59 45.257 ;
     RECT  81.828 45.149 81.846 45.293 ;
     RECT  83.415 45.031 85.554 45.293 ;
     RECT  2.304 45.257 3.186 45.329 ;
     RECT  2.304 45.329 2.862 45.355 ;
     RECT  6.588 45.149 8.334 45.419 ;
     RECT  41.4 45.149 42.39 45.419 ;
     RECT  2.232 45.355 2.862 45.455 ;
     RECT  37.044 45.427 37.062 45.527 ;
     RECT  43.164 44.753 44.046 45.571 ;
     RECT  77.04 45.211 80.946 45.571 ;
     RECT  43.128 45.571 44.046 45.599 ;
     RECT  3.996 45.257 5.562 45.661 ;
     RECT  0.108 45.643 0.126 45.691 ;
     RECT  77.04 45.571 81.63 45.691 ;
     RECT  42.048 45.419 42.39 45.697 ;
     RECT  43.128 45.599 43.578 45.697 ;
     RECT  3.996 45.661 5.814 45.725 ;
     RECT  4.176 45.725 5.814 45.805 ;
     RECT  0.108 45.691 0.198 45.931 ;
     RECT  6.66 45.419 8.334 45.931 ;
     RECT  45.615 37.427 45.897 45.931 ;
     RECT  56.415 43.277 56.697 45.931 ;
     RECT  67.215 43.277 67.497 45.931 ;
     RECT  82.656 45.301 82.674 45.931 ;
     RECT  83.415 45.293 85.482 45.931 ;
     RECT  0.108 45.931 0.342 45.932 ;
     RECT  42.048 45.697 43.578 45.959 ;
     RECT  45.504 45.931 45.897 45.968 ;
     RECT  56.304 45.931 56.697 45.968 ;
     RECT  67.104 45.931 67.497 45.968 ;
     RECT  76.968 45.691 81.63 45.995 ;
     RECT  39.996 45.257 40.518 46.003 ;
     RECT  72.615 43.439 72.897 46.039 ;
     RECT  0.144 45.932 0.342 46.061 ;
     RECT  43.56 45.959 43.578 46.067 ;
     RECT  46.728 45.841 46.746 46.067 ;
     RECT  6.66 45.931 8.442 46.111 ;
     RECT  9.18 45.769 9.198 46.111 ;
     RECT  82.656 45.931 85.482 46.111 ;
     RECT  76.968 45.995 81.09 46.171 ;
     RECT  44.532 46.075 44.55 46.229 ;
     RECT  72.396 46.039 72.897 46.229 ;
     RECT  6.66 46.111 9.198 46.267 ;
     RECT  82.08 46.111 85.482 46.301 ;
     RECT  2.304 45.455 2.862 46.309 ;
     RECT  6.66 46.267 9.414 46.309 ;
     RECT  39.924 46.003 40.518 46.309 ;
     RECT  6.624 46.309 9.414 46.337 ;
     RECT  39.924 46.309 41.238 46.381 ;
     RECT  86.292 46.123 86.31 46.411 ;
     RECT  6.624 46.337 9.198 46.499 ;
     RECT  10.98 46.381 11.07 46.499 ;
     RECT  39.924 46.381 41.634 46.499 ;
     RECT  4.176 45.805 5.886 46.507 ;
     RECT  6.624 46.499 8.298 46.507 ;
     RECT  10.98 46.499 10.998 46.507 ;
     RECT  10.908 46.507 10.998 46.535 ;
     RECT  9.072 46.499 9.198 46.571 ;
     RECT  4.176 46.507 8.298 46.589 ;
     RECT  86.22 46.411 86.31 46.589 ;
     RECT  10.908 46.535 10.926 46.607 ;
     RECT  39.924 46.499 40.662 46.607 ;
     RECT  0.144 46.061 0.162 46.733 ;
     RECT  76.824 46.171 81.09 46.733 ;
     RECT  41.472 46.499 41.634 46.741 ;
     RECT  42.408 45.959 42.426 46.741 ;
     RECT  74.736 45.733 74.754 46.741 ;
     RECT  77.04 46.733 81.09 46.795 ;
     RECT  82.08 46.301 82.566 46.795 ;
     RECT  4.176 46.589 8.226 46.805 ;
     RECT  41.472 46.741 42.426 46.813 ;
     RECT  39.924 46.607 40.626 46.841 ;
     RECT  37.044 46.777 37.062 46.849 ;
     RECT  74.7 46.741 74.754 46.849 ;
     RECT  77.04 46.795 82.566 46.877 ;
     RECT  74.7 46.849 74.79 46.891 ;
     RECT  40.215 46.841 40.626 46.913 ;
     RECT  41.472 46.813 42.57 46.921 ;
     RECT  74.664 46.891 74.79 46.949 ;
     RECT  2.304 46.309 3.294 47.011 ;
     RECT  4.176 46.805 8.154 47.011 ;
     RECT  41.472 46.921 42.75 47.011 ;
     RECT  77.22 46.877 82.566 47.035 ;
     RECT  83.415 46.301 85.482 47.035 ;
     RECT  40.215 46.913 40.59 47.039 ;
     RECT  41.472 47.011 42.894 47.039 ;
     RECT  86.292 46.589 86.31 47.039 ;
     RECT  41.94 47.039 42.894 47.047 ;
     RECT  77.22 47.035 85.482 47.047 ;
     RECT  2.304 47.011 8.154 47.075 ;
     RECT  77.22 47.047 85.518 47.075 ;
     RECT  0.324 46.987 0.342 47.117 ;
     RECT  77.22 47.075 82.494 47.147 ;
     RECT  43.848 47.131 43.866 47.155 ;
     RECT  9.072 46.571 9.126 47.192 ;
     RECT  77.22 47.147 82.35 47.219 ;
     RECT  41.94 47.047 42.966 47.281 ;
     RECT  9.072 47.192 9.09 47.309 ;
     RECT  43.776 47.155 43.866 47.309 ;
     RECT  83.415 47.075 85.518 47.389 ;
     RECT  10.8 46.921 10.818 47.425 ;
     RECT  41.94 47.281 43.038 47.461 ;
     RECT  83.415 47.389 85.554 47.501 ;
     RECT  85.464 47.501 85.554 47.506 ;
     RECT  7.776 47.075 8.154 47.551 ;
     RECT  2.304 47.075 7.038 47.563 ;
     RECT  2.232 47.563 7.038 47.579 ;
     RECT  40.215 47.039 40.554 47.579 ;
     RECT  74.664 46.949 74.754 47.579 ;
     RECT  10.728 47.425 10.818 47.587 ;
     RECT  37.044 46.849 37.098 47.587 ;
     RECT  2.232 47.579 5.922 47.615 ;
     RECT  77.22 47.219 82.278 47.623 ;
     RECT  37.044 47.587 37.134 47.723 ;
     RECT  6.696 47.579 7.038 47.759 ;
     RECT  10.656 47.587 10.818 47.759 ;
     RECT  2.304 47.615 5.922 47.849 ;
     RECT  6.696 47.759 6.966 47.849 ;
     RECT  7.776 47.551 8.19 47.849 ;
     RECT  41.94 47.461 43.758 47.849 ;
     RECT  76.392 47.623 82.278 47.921 ;
     RECT  7.815 47.849 8.19 47.929 ;
     RECT  76.896 47.921 82.278 47.965 ;
     RECT  85.464 47.506 85.59 47.981 ;
     RECT  40.215 47.579 40.497 48.163 ;
     RECT  10.836 48.127 10.854 48.263 ;
     RECT  7.815 47.929 8.982 48.299 ;
     RECT  0.108 48.331 0.126 48.379 ;
     RECT  2.304 47.849 4.554 48.389 ;
     RECT  76.896 47.965 82.674 48.389 ;
     RECT  85.464 47.981 85.482 48.433 ;
     RECT  76.968 48.389 82.674 48.461 ;
     RECT  74.664 47.579 74.682 48.469 ;
     RECT  74.664 48.469 74.754 48.475 ;
     RECT  0.108 48.379 0.198 48.476 ;
     RECT  41.94 47.849 43.506 48.541 ;
     RECT  5.292 47.849 5.778 48.631 ;
     RECT  6.696 47.849 6.858 48.631 ;
     RECT  0.144 48.476 0.198 48.653 ;
     RECT  41.22 48.541 43.506 48.659 ;
     RECT  37.044 47.723 37.062 48.667 ;
     RECT  8.928 48.299 8.982 48.703 ;
     RECT  41.328 48.659 43.506 48.749 ;
     RECT  74.664 48.475 74.79 48.749 ;
     RECT  76.968 48.461 82.278 48.749 ;
     RECT  83.415 47.501 84.402 48.749 ;
     RECT  37.044 48.667 37.134 48.767 ;
     RECT  5.292 48.631 6.858 48.775 ;
     RECT  7.815 48.299 8.154 48.775 ;
     RECT  4.248 48.389 4.554 48.803 ;
     RECT  41.868 48.749 43.506 48.811 ;
     RECT  44.532 48.703 44.55 48.811 ;
     RECT  4.392 48.803 4.554 48.901 ;
     RECT  5.292 48.775 8.154 48.901 ;
     RECT  85.428 48.433 85.482 48.901 ;
     RECT  39.924 48.163 40.497 48.929 ;
     RECT  77.292 48.749 82.278 48.929 ;
     RECT  41.868 48.811 44.55 48.941 ;
     RECT  37.044 48.767 37.062 49.001 ;
     RECT  4.392 48.901 8.154 49.045 ;
     RECT  8.928 48.703 9.126 49.045 ;
     RECT  83.415 48.749 83.862 49.045 ;
     RECT  0.18 48.653 0.198 49.051 ;
     RECT  0.18 49.051 0.27 49.109 ;
     RECT  4.392 49.045 9.126 49.109 ;
     RECT  1.116 49.003 1.134 49.181 ;
     RECT  42.156 48.941 44.55 49.199 ;
     RECT  10.8 49.081 10.818 49.207 ;
     RECT  10.8 49.207 10.854 49.243 ;
     RECT  10.728 49.243 10.854 49.379 ;
     RECT  0.18 49.109 0.198 49.387 ;
     RECT  77.544 48.929 82.278 49.441 ;
     RECT  83.232 49.045 83.862 49.441 ;
     RECT  44.244 49.199 44.262 49.505 ;
     RECT  40.215 48.929 40.497 49.513 ;
     RECT  0.144 49.387 0.198 49.585 ;
     RECT  74.664 48.749 74.682 49.585 ;
     RECT  6.156 49.109 9.126 49.621 ;
     RECT  77.544 49.441 83.862 49.621 ;
     RECT  84.852 48.901 85.482 49.621 ;
     RECT  42.156 49.199 43.434 49.711 ;
     RECT  77.544 49.621 85.482 49.711 ;
     RECT  6.156 49.621 9.162 49.739 ;
     RECT  0.108 49.585 0.198 49.805 ;
     RECT  74.664 49.585 74.826 49.811 ;
     RECT  2.304 48.389 3.474 49.819 ;
     RECT  4.392 49.109 5.238 49.819 ;
     RECT  72.615 46.229 72.897 49.819 ;
     RECT  0.18 49.805 0.198 49.853 ;
     RECT  2.304 49.819 5.238 49.891 ;
     RECT  6.156 49.739 8.19 49.891 ;
     RECT  38.196 49.207 38.214 49.919 ;
     RECT  41.904 49.711 43.434 49.981 ;
     RECT  10.8 49.379 10.854 50.009 ;
     RECT  40.215 49.513 41.058 50.053 ;
     RECT  41.904 49.981 43.47 50.053 ;
     RECT  40.215 50.053 43.47 50.081 ;
     RECT  38.772 50.017 38.862 50.153 ;
     RECT  2.304 49.891 8.19 50.189 ;
     RECT  72.615 49.819 73.566 50.189 ;
     RECT  56.415 45.968 56.697 50.251 ;
     RECT  67.215 45.968 67.497 50.251 ;
     RECT  56.304 50.251 56.697 50.288 ;
     RECT  67.104 50.251 67.497 50.288 ;
     RECT  2.304 50.189 3.15 50.333 ;
     RECT  46.62 50.251 46.638 50.347 ;
     RECT  46.62 50.347 46.746 50.381 ;
     RECT  74.664 49.811 74.79 50.381 ;
     RECT  77.544 49.711 85.518 50.459 ;
     RECT  3.996 50.189 8.19 50.521 ;
     RECT  9 49.739 9.018 50.521 ;
     RECT  77.544 50.459 82.17 50.539 ;
     RECT  19.944 50.395 20.502 50.549 ;
     RECT  19.944 50.549 20.178 50.573 ;
     RECT  46.728 50.381 46.746 50.621 ;
     RECT  3.996 50.521 9.018 50.629 ;
     RECT  77.436 50.539 82.17 50.692 ;
     RECT  3.996 50.629 9.414 50.693 ;
     RECT  10.908 50.521 10.998 50.693 ;
     RECT  74.664 50.381 74.754 50.717 ;
     RECT  77.4 50.692 82.17 50.899 ;
     RECT  40.215 50.081 43.29 50.935 ;
     RECT  3.996 50.693 8.406 50.971 ;
     RECT  40.215 50.935 44.01 51.089 ;
     RECT  38.772 50.153 38.79 51.097 ;
     RECT  86.292 50.923 86.31 51.115 ;
     RECT  76.968 50.899 82.17 51.197 ;
     RECT  86.256 51.115 86.31 51.197 ;
     RECT  2.304 50.333 2.79 51.211 ;
     RECT  3.564 50.971 8.406 51.211 ;
     RECT  83.415 50.459 85.482 51.233 ;
     RECT  9.396 50.693 9.414 51.269 ;
     RECT  41.832 51.089 44.01 51.269 ;
     RECT  81.828 51.197 82.17 51.331 ;
     RECT  40.215 51.089 41.094 51.359 ;
     RECT  81.828 51.331 82.566 51.403 ;
     RECT  83.415 51.233 83.934 51.403 ;
     RECT  2.304 51.211 8.406 51.431 ;
     RECT  40.215 51.359 41.058 51.431 ;
     RECT  76.968 51.197 81.09 51.431 ;
     RECT  72.615 50.189 72.897 51.475 ;
     RECT  74.664 50.717 74.718 51.485 ;
     RECT  76.968 51.431 79.866 51.511 ;
     RECT  5.004 51.431 8.406 51.629 ;
     RECT  46.728 51.367 46.746 51.629 ;
     RECT  74.7 51.485 74.718 51.629 ;
     RECT  43.668 51.269 44.01 51.673 ;
     RECT  76.464 51.511 79.866 51.673 ;
     RECT  43.668 51.673 44.118 51.709 ;
     RECT  38.772 51.097 38.862 51.737 ;
     RECT  0.144 51.307 0.162 51.739 ;
     RECT  43.668 51.709 44.154 51.745 ;
     RECT  41.832 51.269 42.75 51.773 ;
     RECT  0.144 51.739 0.198 51.787 ;
     RECT  42.192 51.773 42.75 51.809 ;
     RECT  80.784 51.431 81.09 51.899 ;
     RECT  43.668 51.745 44.226 51.907 ;
     RECT  86.292 51.197 86.31 51.935 ;
     RECT  6.768 51.629 8.406 51.943 ;
     RECT  0.108 51.787 0.198 52.007 ;
     RECT  6.768 51.943 9.198 52.015 ;
     RECT  43.668 51.907 44.298 52.051 ;
     RECT  81.828 51.403 83.934 52.051 ;
     RECT  84.888 51.233 85.482 52.051 ;
     RECT  72.615 51.475 73.566 52.079 ;
     RECT  81.828 52.051 85.482 52.109 ;
     RECT  40.215 51.431 41.022 52.177 ;
     RECT  6.768 52.015 9.306 52.205 ;
     RECT  80.928 51.899 81.09 52.219 ;
     RECT  81.828 52.109 83.934 52.219 ;
     RECT  76.392 51.673 79.866 52.285 ;
     RECT  42.264 51.809 42.75 52.321 ;
     RECT  43.488 52.051 44.298 52.321 ;
     RECT  2.304 51.431 4.23 52.363 ;
     RECT  5.004 51.629 5.778 52.411 ;
     RECT  56.415 50.288 56.697 52.411 ;
     RECT  67.215 50.288 67.497 52.411 ;
     RECT  40.215 52.177 41.202 52.439 ;
     RECT  42.264 52.321 44.298 52.439 ;
     RECT  76.392 52.285 80.082 52.439 ;
     RECT  46.764 52.267 46.782 52.445 ;
     RECT  75.24 52.321 75.258 52.447 ;
     RECT  76.392 52.439 80.01 52.448 ;
     RECT  2.268 52.363 4.23 52.483 ;
     RECT  5.004 52.411 5.814 52.483 ;
     RECT  74.736 52.447 75.258 52.511 ;
     RECT  2.268 52.483 5.814 52.547 ;
     RECT  68.58 52.681 68.598 52.733 ;
     RECT  2.304 52.547 5.778 52.745 ;
     RECT  2.304 52.745 3.654 52.817 ;
     RECT  10.908 52.753 10.926 52.825 ;
     RECT  80.928 52.219 83.934 52.843 ;
     RECT  84.924 52.109 85.482 52.843 ;
     RECT  10.764 52.825 10.926 52.853 ;
     RECT  76.392 52.448 79.902 52.853 ;
     RECT  40.215 52.439 41.058 52.861 ;
     RECT  61.815 2.413 62.097 52.861 ;
     RECT  67.104 52.411 67.497 52.861 ;
     RECT  80.928 52.843 85.482 52.861 ;
     RECT  46.656 52.447 46.746 52.877 ;
     RECT  3.636 52.817 3.654 52.889 ;
     RECT  54.72 52.789 54.738 52.889 ;
     RECT  56.304 52.411 56.697 52.889 ;
     RECT  67.104 52.861 67.554 52.889 ;
     RECT  0.576 52.939 0.594 52.951 ;
     RECT  80.928 52.861 85.518 52.973 ;
     RECT  0.576 52.951 0.666 52.978 ;
     RECT  6.984 52.205 9.306 52.979 ;
     RECT  46.656 52.877 46.674 52.979 ;
     RECT  61.815 52.861 62.766 52.979 ;
     RECT  67.215 52.889 67.554 52.979 ;
     RECT  10.764 52.853 10.818 53.015 ;
     RECT  0.54 52.978 0.666 53.021 ;
     RECT  76.752 52.853 79.902 53.021 ;
     RECT  0.54 53.021 0.558 53.069 ;
     RECT  76.752 53.021 79.434 53.117 ;
     RECT  39.924 52.861 41.058 53.159 ;
     RECT  6.984 52.979 9.09 53.221 ;
     RECT  40.215 53.159 41.058 53.249 ;
     RECT  42.264 52.439 43.83 53.249 ;
     RECT  42.264 53.249 43.506 53.257 ;
     RECT  6.84 53.221 9.09 53.329 ;
     RECT  77.112 53.117 79.434 53.357 ;
     RECT  74.736 52.511 74.754 53.365 ;
     RECT  74.664 53.365 74.754 53.393 ;
     RECT  4.5 52.745 5.778 53.401 ;
     RECT  41.616 53.257 43.506 53.519 ;
     RECT  74.664 53.393 74.682 53.519 ;
     RECT  80.928 52.973 85.482 53.519 ;
     RECT  4.5 53.401 5.886 53.555 ;
     RECT  80.928 53.519 80.946 53.555 ;
     RECT  38.772 53.329 38.79 53.591 ;
     RECT  77.256 53.357 78.462 53.645 ;
     RECT  2.304 52.817 2.697 53.659 ;
     RECT  3.492 53.563 3.51 53.659 ;
     RECT  2.304 53.659 3.51 53.671 ;
     RECT  6.66 53.329 9.09 53.789 ;
     RECT  79.2 53.357 79.434 53.797 ;
     RECT  2.304 53.671 3.654 53.825 ;
     RECT  75.816 52.861 75.834 53.825 ;
     RECT  79.2 53.797 79.47 53.869 ;
     RECT  80.388 53.563 80.766 53.869 ;
     RECT  6.66 53.789 8.946 53.897 ;
     RECT  6.66 53.897 8.802 53.905 ;
     RECT  4.5 53.555 5.742 53.933 ;
     RECT  2.304 53.825 2.934 53.941 ;
     RECT  10.8 53.015 10.818 53.941 ;
     RECT  10.728 53.941 10.818 54.059 ;
     RECT  4.5 53.933 5.562 54.103 ;
     RECT  81.72 53.519 85.482 54.125 ;
     RECT  10.728 54.059 10.746 54.131 ;
     RECT  77.364 53.645 78.462 54.139 ;
     RECT  79.2 53.869 80.766 54.139 ;
     RECT  43.056 53.519 43.506 54.175 ;
     RECT  77.364 54.139 80.766 54.203 ;
     RECT  41.616 53.519 42.21 54.301 ;
     RECT  43.056 54.175 43.902 54.301 ;
     RECT  40.215 53.249 40.554 54.337 ;
     RECT  80.352 54.203 80.766 54.379 ;
     RECT  81.72 54.125 82.278 54.379 ;
     RECT  80.352 54.379 82.278 54.401 ;
     RECT  41.616 54.301 43.902 54.413 ;
     RECT  77.364 54.203 79.614 54.445 ;
     RECT  6.552 53.905 8.802 54.473 ;
     RECT  42.732 54.413 43.902 54.481 ;
     RECT  46.728 53.941 46.746 54.599 ;
     RECT  6.552 54.473 8.097 54.607 ;
     RECT  77.184 54.445 79.614 54.653 ;
     RECT  3.996 54.103 5.562 54.701 ;
     RECT  38.772 54.607 38.79 54.707 ;
     RECT  42.732 54.481 43.974 54.707 ;
     RECT  2.268 53.941 2.934 54.751 ;
     RECT  5.4 54.701 5.562 54.751 ;
     RECT  6.48 54.607 8.097 54.751 ;
     RECT  39.924 54.337 40.554 54.751 ;
     RECT  80.424 54.401 82.278 54.779 ;
     RECT  2.268 54.751 3.222 54.859 ;
     RECT  80.676 54.779 82.278 54.877 ;
     RECT  83.124 54.125 85.482 54.877 ;
     RECT  2.232 54.859 3.222 54.905 ;
     RECT  5.4 54.751 8.097 54.905 ;
     RECT  39.924 54.751 40.806 54.913 ;
     RECT  41.616 54.413 41.634 54.913 ;
     RECT  2.304 54.905 3.222 54.985 ;
     RECT  9.288 54.715 9.378 55.013 ;
     RECT  5.508 54.905 8.097 55.139 ;
     RECT  39.924 54.913 41.634 55.139 ;
     RECT  76.392 54.643 76.41 55.139 ;
     RECT  5.58 55.139 8.097 55.175 ;
     RECT  42.732 54.707 43.506 55.183 ;
     RECT  2.304 54.985 3.258 55.247 ;
     RECT  40.215 55.139 41.634 55.255 ;
     RECT  5.652 55.175 8.097 55.277 ;
     RECT  9.288 55.013 9.306 55.291 ;
     RECT  77.184 54.653 78.786 55.291 ;
     RECT  9.18 55.291 9.306 55.292 ;
     RECT  80.676 54.877 85.482 55.319 ;
     RECT  81.9 55.319 85.482 55.373 ;
     RECT  6.732 55.277 8.097 55.381 ;
     RECT  9.18 55.292 9.27 55.381 ;
     RECT  76.824 55.291 78.786 55.387 ;
     RECT  79.632 55.021 79.65 55.387 ;
     RECT  42.624 55.183 43.506 55.409 ;
     RECT  44.244 55.021 44.262 55.409 ;
     RECT  81.9 55.373 83.826 55.445 ;
     RECT  72.615 52.079 72.897 55.453 ;
     RECT  84.816 55.373 85.482 55.489 ;
     RECT  40.215 55.255 41.778 55.517 ;
     RECT  6.732 55.381 9.27 55.553 ;
     RECT  2.34 55.247 3.258 55.561 ;
     RECT  3.996 54.701 4.59 55.561 ;
     RECT  9.108 55.553 9.27 55.589 ;
     RECT  0.108 55.627 0.126 55.675 ;
     RECT  6.732 55.553 8.154 55.679 ;
     RECT  41.76 55.517 41.778 55.679 ;
     RECT  42.66 55.409 42.858 55.679 ;
     RECT  81.9 55.445 83.754 55.679 ;
     RECT  76.824 55.387 79.65 55.723 ;
     RECT  80.676 55.319 81.126 55.723 ;
     RECT  2.34 55.561 4.59 55.823 ;
     RECT  40.215 55.517 40.914 55.823 ;
     RECT  76.824 55.723 81.126 55.823 ;
     RECT  86.292 54.955 86.31 55.859 ;
     RECT  0.108 55.675 0.198 55.916 ;
     RECT  4.032 55.823 4.59 55.921 ;
     RECT  39.348 55.651 39.366 55.949 ;
     RECT  44.352 55.561 44.37 55.949 ;
     RECT  10.8 55.921 10.818 56.021 ;
     RECT  6.732 55.679 6.93 56.029 ;
     RECT  0.144 55.916 0.162 56.093 ;
     RECT  4.032 55.921 4.878 56.093 ;
     RECT  2.34 55.823 3.294 56.107 ;
     RECT  9.36 56.029 9.45 56.129 ;
     RECT  2.304 56.107 3.294 56.203 ;
     RECT  72.615 55.453 73.566 56.219 ;
     RECT  5.652 55.277 5.85 56.227 ;
     RECT  76.896 55.823 81.126 56.227 ;
     RECT  81.9 55.679 83.697 56.227 ;
     RECT  9.36 56.129 9.378 56.255 ;
     RECT  5.652 56.227 5.922 56.299 ;
     RECT  6.696 56.029 6.93 56.299 ;
     RECT  7.704 55.679 8.154 56.335 ;
     RECT  42.84 55.679 42.858 56.371 ;
     RECT  76.896 56.227 83.697 56.429 ;
     RECT  2.268 56.203 3.294 56.488 ;
     RECT  5.652 56.299 6.93 56.489 ;
     RECT  4.104 56.093 4.878 56.497 ;
     RECT  5.652 56.489 5.778 56.497 ;
     RECT  40.215 55.823 40.59 56.497 ;
     RECT  2.16 56.488 3.294 56.525 ;
     RECT  6.588 56.489 6.93 56.569 ;
     RECT  7.704 56.335 8.37 56.569 ;
     RECT  42.84 56.371 43.182 56.569 ;
     RECT  4.104 56.497 5.778 56.573 ;
     RECT  41.904 56.227 41.922 56.587 ;
     RECT  42.84 56.569 43.794 56.587 ;
     RECT  77.004 56.429 83.697 56.597 ;
     RECT  2.268 56.525 3.294 56.641 ;
     RECT  41.904 56.587 43.794 56.641 ;
     RECT  37.044 56.263 37.062 56.669 ;
     RECT  18.615 2.413 18.897 56.731 ;
     RECT  39.924 56.497 40.59 56.731 ;
     RECT  41.832 56.641 43.794 56.731 ;
     RECT  74.664 55.687 74.754 56.731 ;
     RECT  39.924 56.731 43.938 56.759 ;
     RECT  42.336 56.759 43.938 56.767 ;
     RECT  39.924 56.759 41.274 56.768 ;
     RECT  2.268 56.641 3.366 56.795 ;
     RECT  54.72 56.731 54.738 56.861 ;
     RECT  60.984 56.731 61.002 56.861 ;
     RECT  74.664 56.731 74.862 56.861 ;
     RECT  39.924 56.768 40.554 56.867 ;
     RECT  42.336 56.767 44.01 56.867 ;
     RECT  84.816 55.489 85.518 56.867 ;
     RECT  6.588 56.569 8.37 56.903 ;
     RECT  74.664 56.861 74.79 56.909 ;
     RECT  74.664 56.909 74.754 56.939 ;
     RECT  77.148 56.597 83.697 56.971 ;
     RECT  84.816 56.867 85.482 56.971 ;
     RECT  77.148 56.971 85.482 57.029 ;
     RECT  10.836 57.001 10.854 57.101 ;
     RECT  9.108 56.569 9.126 57.109 ;
     RECT  39.924 56.867 40.497 57.109 ;
     RECT  4.104 56.573 5.67 57.115 ;
     RECT  9.108 57.109 9.342 57.209 ;
     RECT  38.772 56.569 38.79 57.271 ;
     RECT  3.996 57.115 5.67 57.307 ;
     RECT  7.668 56.903 8.37 57.307 ;
     RECT  9.108 57.209 9.126 57.307 ;
     RECT  86.292 57.259 86.31 57.307 ;
     RECT  2.268 56.795 3.114 57.335 ;
     RECT  0.144 57.115 0.162 57.403 ;
     RECT  38.772 57.271 38.826 57.403 ;
     RECT  86.22 57.307 86.31 57.407 ;
     RECT  65.232 57.019 65.25 57.437 ;
     RECT  74.736 56.939 74.754 57.443 ;
     RECT  13.215 2.413 13.497 57.547 ;
     RECT  24.015 2.413 24.297 57.547 ;
     RECT  29.415 2.413 29.697 57.547 ;
     RECT  34.815 2.413 35.097 57.547 ;
     RECT  38.772 57.403 38.898 57.569 ;
     RECT  3.996 57.307 5.742 57.577 ;
     RECT  0.144 57.403 0.234 57.581 ;
     RECT  14.832 57.451 14.85 57.581 ;
     RECT  18.615 56.731 19.314 57.581 ;
     RECT  22.788 57.451 22.806 57.581 ;
     RECT  38.88 57.569 38.898 57.581 ;
     RECT  2.304 57.335 3.114 57.595 ;
     RECT  3.924 57.577 5.742 57.595 ;
     RECT  18.615 57.581 18.99 57.605 ;
     RECT  2.304 57.595 5.742 57.629 ;
     RECT  13.215 57.547 13.59 57.641 ;
     RECT  24.015 57.547 24.39 57.641 ;
     RECT  29.415 57.547 29.79 57.641 ;
     RECT  34.815 57.547 35.19 57.641 ;
     RECT  6.588 56.903 6.858 57.685 ;
     RECT  7.668 57.307 9.126 57.685 ;
     RECT  42.336 56.867 43.686 57.685 ;
     RECT  4.176 57.629 5.742 57.713 ;
     RECT  42.336 57.685 43.866 57.721 ;
     RECT  6.588 57.685 9.126 57.811 ;
     RECT  2.304 57.629 3.258 57.839 ;
     RECT  41.976 57.721 43.866 57.839 ;
     RECT  76.968 57.379 76.986 57.839 ;
     RECT  77.76 57.029 85.482 57.839 ;
     RECT  39.888 57.109 40.497 57.847 ;
     RECT  46.656 57.001 46.674 57.883 ;
     RECT  6.156 57.811 9.126 57.911 ;
     RECT  46.656 57.883 46.746 57.911 ;
     RECT  0.144 57.581 0.162 57.917 ;
     RECT  77.94 57.839 85.482 57.931 ;
     RECT  86.22 57.407 86.238 57.931 ;
     RECT  39.888 57.847 41.058 57.947 ;
     RECT  2.304 57.839 2.79 57.983 ;
     RECT  46.728 57.911 46.746 57.983 ;
     RECT  2.415 57.983 2.79 58.013 ;
     RECT  4.176 57.713 5.382 58.109 ;
     RECT  6.156 57.911 8.478 58.109 ;
     RECT  74.664 57.883 74.682 58.109 ;
     RECT  6.228 58.109 8.478 58.145 ;
     RECT  4.176 58.109 4.194 58.253 ;
     RECT  77.94 57.931 86.238 58.253 ;
     RECT  40.215 57.947 41.058 58.261 ;
     RECT  41.976 57.839 42.534 58.261 ;
     RECT  6.804 58.145 8.478 58.379 ;
     RECT  9.252 58.261 9.27 58.379 ;
     RECT  40.215 58.261 42.534 58.379 ;
     RECT  44.64 58.225 44.658 58.379 ;
     RECT  80.568 58.253 86.238 58.379 ;
     RECT  84.78 58.379 86.238 58.493 ;
     RECT  10.8 58.387 10.818 58.559 ;
     RECT  40.215 58.379 41.634 58.559 ;
     RECT  80.568 58.379 83.826 58.559 ;
     RECT  84.816 58.493 86.238 58.603 ;
     RECT  77.94 58.253 79.794 58.621 ;
     RECT  7.308 58.379 8.298 58.649 ;
     RECT  41.436 58.559 41.634 58.649 ;
     RECT  77.688 58.621 79.794 58.649 ;
     RECT  77.688 58.649 78.786 58.657 ;
     RECT  7.308 58.649 8.097 58.691 ;
     RECT  42.948 58.621 42.966 58.721 ;
     RECT  79.56 58.649 79.794 58.919 ;
     RECT  80.676 58.559 83.826 58.991 ;
     RECT  84.816 58.603 86.31 59.027 ;
     RECT  77.58 58.657 78.786 59.071 ;
     RECT  80.712 58.991 83.826 59.099 ;
     RECT  77.544 59.071 78.786 59.189 ;
     RECT  79.56 58.919 79.578 59.189 ;
     RECT  82.548 59.099 83.826 59.189 ;
     RECT  84.816 59.027 86.202 59.189 ;
     RECT  77.544 59.189 78.714 59.213 ;
     RECT  80.712 59.099 81.666 59.225 ;
     RECT  81.36 59.225 81.666 59.261 ;
     RECT  82.692 59.189 83.79 59.261 ;
     RECT  81.648 59.261 81.666 59.369 ;
     RECT  78.015 59.213 78.714 59.459 ;
     RECT  82.692 59.261 83.754 59.495 ;
     RECT  86.184 59.189 86.202 59.567 ;
     RECT  84.816 59.189 84.87 59.881 ;
     RECT  84.528 59.881 84.87 59.971 ;
     RECT  82.692 59.495 83.697 60.007 ;
     RECT  80.82 60.007 80.838 60.079 ;
     RECT  81.648 60.115 81.666 60.151 ;
     RECT  82.656 60.007 83.697 60.151 ;
     RECT  78.015 59.459 78.297 60.241 ;
     RECT  80.244 60.079 80.838 60.241 ;
     RECT  81.648 60.151 83.697 60.241 ;
     RECT  2.415 58.013 2.697 60.331 ;
     RECT  0.504 60.313 0.522 60.385 ;
     RECT  80.244 60.241 83.697 60.385 ;
     RECT  2.304 60.331 2.697 60.421 ;
     RECT  7.815 58.691 8.097 60.421 ;
     RECT  0.504 60.385 0.558 60.461 ;
     RECT  2.304 60.421 2.934 60.511 ;
     RECT  78.015 60.241 78.678 60.511 ;
     RECT  41.724 60.421 41.742 60.539 ;
     RECT  80.136 60.385 83.718 60.539 ;
     RECT  6.228 60.313 6.246 60.547 ;
     RECT  7.344 60.421 8.097 60.547 ;
     RECT  80.136 60.539 83.697 60.547 ;
     RECT  4.248 60.547 4.266 60.604 ;
     RECT  6.228 60.547 8.097 60.619 ;
     RECT  79.776 60.547 83.697 60.655 ;
     RECT  2.304 60.511 3.006 60.691 ;
     RECT  6.084 60.619 8.097 60.691 ;
     RECT  74.736 60.583 74.754 60.691 ;
     RECT  78.015 60.511 78.714 60.691 ;
     RECT  79.452 60.655 83.697 60.691 ;
     RECT  5.148 60.385 5.166 60.809 ;
     RECT  4.212 60.604 4.266 60.811 ;
     RECT  2.304 60.691 3.258 60.925 ;
     RECT  4.212 60.811 5.022 60.925 ;
     RECT  0.504 60.461 0.522 60.941 ;
     RECT  84.528 59.971 85.662 60.961 ;
     RECT  6.012 60.691 8.097 60.989 ;
     RECT  6.012 60.989 6.246 61.003 ;
     RECT  7.056 60.989 8.097 61.051 ;
     RECT  42.84 60.889 42.858 61.079 ;
     RECT  2.304 60.925 5.022 61.087 ;
     RECT  76.68 61.051 76.698 61.087 ;
     RECT  78.015 60.691 83.697 61.099 ;
     RECT  7.056 61.051 8.154 61.123 ;
     RECT  8.928 60.511 8.946 61.123 ;
     RECT  2.196 61.087 5.022 61.133 ;
     RECT  7.056 61.123 9.234 61.159 ;
     RECT  76.392 61.087 76.698 61.159 ;
     RECT  75.96 61.159 76.698 61.195 ;
     RECT  38.772 61.087 38.79 61.223 ;
     RECT  43.92 61.087 43.938 61.223 ;
     RECT  84.528 60.961 86.31 61.229 ;
     RECT  16.956 61.087 16.974 61.231 ;
     RECT  7.056 61.159 9.414 61.259 ;
     RECT  16.272 61.231 16.974 61.259 ;
     RECT  74.664 60.691 74.754 61.259 ;
     RECT  0.144 61.147 0.162 61.325 ;
     RECT  10.728 61.321 10.746 61.357 ;
     RECT  77.724 61.099 83.697 61.357 ;
     RECT  5.76 61.003 6.246 61.373 ;
     RECT  7.056 61.259 9.234 61.421 ;
     RECT  10.728 61.357 10.818 61.457 ;
     RECT  2.268 61.133 5.022 61.493 ;
     RECT  16.272 61.259 16.29 61.493 ;
     RECT  10.8 61.457 10.818 61.529 ;
     RECT  42.948 61.231 42.966 61.529 ;
     RECT  74.736 61.259 74.754 61.529 ;
     RECT  75.96 61.195 76.878 61.627 ;
     RECT  6.192 61.373 6.246 61.655 ;
     RECT  4.752 61.493 5.022 61.675 ;
     RECT  7.056 61.421 9.198 61.691 ;
     RECT  75.924 61.627 76.914 61.735 ;
     RECT  2.268 61.493 3.87 61.763 ;
     RECT  7.056 61.691 7.074 61.771 ;
     RECT  86.292 61.229 86.31 61.805 ;
     RECT  18.615 57.605 18.897 61.861 ;
     RECT  75.924 61.735 76.95 61.861 ;
     RECT  77.688 61.357 83.697 61.861 ;
     RECT  84.528 61.229 85.482 61.861 ;
     RECT  6.84 61.771 7.074 61.901 ;
     RECT  18.615 61.861 19.242 61.901 ;
     RECT  18.615 61.901 18.897 61.915 ;
     RECT  2.304 61.763 3.87 61.925 ;
     RECT  4.752 61.675 5.166 61.925 ;
     RECT  18.54 61.915 18.897 61.961 ;
     RECT  4.752 61.925 5.13 61.997 ;
     RECT  3.852 61.925 3.87 62.033 ;
     RECT  6.84 61.901 6.858 62.033 ;
     RECT  4.752 61.997 5.022 62.069 ;
     RECT  7.815 61.691 9.198 62.069 ;
     RECT  7.815 62.069 8.154 62.195 ;
     RECT  75.924 61.861 85.482 62.381 ;
     RECT  84.888 62.381 85.482 62.401 ;
     RECT  9.108 62.069 9.126 62.465 ;
     RECT  84.888 62.401 85.518 62.669 ;
     RECT  75.924 62.381 83.754 62.977 ;
     RECT  75.888 62.977 83.754 63.053 ;
     RECT  65.268 62.731 65.286 63.067 ;
     RECT  75.888 63.053 82.674 63.113 ;
     RECT  5.004 62.069 5.022 63.115 ;
     RECT  4.824 63.115 5.022 63.121 ;
     RECT  86.22 63.085 86.238 63.149 ;
     RECT  4.824 63.121 5.166 63.239 ;
     RECT  74.664 63.067 74.682 63.245 ;
     RECT  4.824 63.239 4.842 63.248 ;
     RECT  83.415 63.053 83.754 63.391 ;
     RECT  84.888 62.669 85.482 63.391 ;
     RECT  65.268 63.067 65.538 63.419 ;
     RECT  75.888 63.113 79.542 63.499 ;
     RECT  75.852 63.499 79.542 63.589 ;
     RECT  75.816 63.589 79.542 63.661 ;
     RECT  65.268 63.419 65.286 63.725 ;
     RECT  83.415 63.391 85.482 63.725 ;
     RECT  75.672 63.661 79.542 63.815 ;
     RECT  80.568 63.113 82.35 63.851 ;
     RECT  83.415 63.725 83.826 64.121 ;
     RECT  83.415 64.121 83.754 64.165 ;
     RECT  80.568 63.851 82.278 64.327 ;
     RECT  75.816 63.815 79.542 64.459 ;
     RECT  80.46 64.327 82.278 64.459 ;
     RECT  83.268 64.165 83.754 64.705 ;
     RECT  75.816 64.459 82.278 64.891 ;
     RECT  83.196 64.705 83.754 64.891 ;
     RECT  75.816 64.891 83.754 64.895 ;
     RECT  84.888 63.725 85.482 65.131 ;
     RECT  75.816 64.895 83.697 65.245 ;
     RECT  75.636 65.245 83.697 65.399 ;
     RECT  75.744 65.399 83.697 65.435 ;
     RECT  75.816 65.435 83.697 65.501 ;
     RECT  86.292 63.247 86.31 65.803 ;
     RECT  75.816 65.501 80.946 65.939 ;
     RECT  75.96 65.939 80.946 66.011 ;
     RECT  84.852 65.131 85.482 66.283 ;
     RECT  75.996 66.011 80.946 66.325 ;
     RECT  81.792 65.501 83.697 66.325 ;
     RECT  75.996 66.325 83.697 66.749 ;
     RECT  76.248 66.749 78.498 66.821 ;
     RECT  79.452 66.749 83.697 66.845 ;
     RECT  80.928 66.845 83.697 66.929 ;
     RECT  84.816 66.283 85.482 66.991 ;
     RECT  86.22 65.803 86.31 66.991 ;
     RECT  84.816 66.991 86.31 67.019 ;
     RECT  79.452 66.845 79.902 67.091 ;
     RECT  85.5 67.019 86.274 67.091 ;
     RECT  79.452 67.091 79.47 67.127 ;
     RECT  85.5 67.091 86.238 67.127 ;
     RECT  81.036 66.929 83.697 67.133 ;
     RECT  81.504 67.133 83.697 67.199 ;
     RECT  86.22 67.127 86.238 67.199 ;
     RECT  76.752 66.821 78.498 67.945 ;
     RECT  76.644 67.945 78.498 68.135 ;
     RECT  76.752 68.135 78.498 68.207 ;
     RECT  76.788 68.207 76.986 68.243 ;
     RECT  2.415 61.925 2.697 68.647 ;
     RECT  4.392 68.779 4.41 68.791 ;
     RECT  2.412 68.647 2.697 68.917 ;
     RECT  3.528 68.791 3.546 68.917 ;
     RECT  4.32 68.791 4.41 68.945 ;
     RECT  2.412 68.917 3.546 68.971 ;
     RECT  6.012 68.881 6.03 69.025 ;
     RECT  40.215 58.559 40.497 69.025 ;
     RECT  2.304 68.971 3.546 69.061 ;
     RECT  7.815 62.195 8.097 69.061 ;
     RECT  2.304 69.061 3.762 69.067 ;
     RECT  2.268 69.067 3.762 69.163 ;
     RECT  76.824 68.243 76.986 69.179 ;
     RECT  4.5 69.025 4.842 69.215 ;
     RECT  7.38 69.061 8.097 69.223 ;
     RECT  2.232 69.163 3.762 69.287 ;
     RECT  2.268 69.287 3.762 69.323 ;
     RECT  75.996 69.259 76.014 69.323 ;
     RECT  41.328 69.295 41.346 69.331 ;
     RECT  42.084 68.791 42.102 69.331 ;
     RECT  2.268 69.323 3.618 69.359 ;
     RECT  6.912 69.223 8.097 69.359 ;
     RECT  74.664 69.187 74.682 69.359 ;
     RECT  4.68 69.215 4.842 69.449 ;
     RECT  5.616 69.025 6.03 69.449 ;
     RECT  2.34 69.359 3.618 69.485 ;
     RECT  4.68 69.449 4.698 69.485 ;
     RECT  41.328 69.331 42.102 69.493 ;
     RECT  2.415 69.485 3.618 69.533 ;
     RECT  7.2 69.359 8.097 69.533 ;
     RECT  2.415 69.533 2.934 69.557 ;
     RECT  5.76 69.449 6.03 69.601 ;
     RECT  39.924 69.025 40.497 69.719 ;
     RECT  5.76 69.601 6.282 69.899 ;
     RECT  38.772 69.187 38.79 69.989 ;
     RECT  41.328 69.493 42.534 70.069 ;
     RECT  5.76 69.899 5.778 70.109 ;
     RECT  80.532 70.123 80.55 70.685 ;
     RECT  0.108 72.523 0.126 72.995 ;
     RECT  47.304 72.931 47.322 73.237 ;
     RECT  76.824 69.179 76.842 73.265 ;
     RECT  45.615 45.968 45.897 73.651 ;
     RECT  44.712 73.651 44.73 73.768 ;
     RECT  45.615 73.651 46.458 73.771 ;
     RECT  44.136 73.768 44.73 73.777 ;
     RECT  45.615 73.771 46.494 73.777 ;
     RECT  47.304 73.237 47.79 73.777 ;
     RECT  44.136 73.777 46.494 73.805 ;
     RECT  47.232 73.777 47.79 73.805 ;
     RECT  44.712 73.805 46.494 73.813 ;
     RECT  47.232 73.805 47.466 73.813 ;
     RECT  44.712 73.813 47.466 74.039 ;
     RECT  41.328 70.069 42.606 74.047 ;
     RECT  44.892 74.039 47.466 74.075 ;
     RECT  41.328 74.047 43.182 74.093 ;
     RECT  45.36 74.075 46.71 74.309 ;
     RECT  45.36 74.309 46.638 74.849 ;
     RECT  77.868 68.207 78.498 75.235 ;
     RECT  41.328 74.093 42.606 75.263 ;
     RECT  77.868 75.235 78.822 75.271 ;
     RECT  81.9 67.199 81.918 75.271 ;
     RECT  41.364 75.263 42.606 75.497 ;
     RECT  80.748 75.499 80.766 75.539 ;
     RECT  79.848 75.499 79.866 75.541 ;
     RECT  81.9 75.271 82.17 75.541 ;
     RECT  41.364 75.497 41.706 75.569 ;
     RECT  45.615 74.849 46.314 75.631 ;
     RECT  47.448 74.075 47.466 75.631 ;
     RECT  77.868 75.271 78.894 75.659 ;
     RECT  79.848 75.541 80.01 75.659 ;
     RECT  79.848 75.659 79.866 75.667 ;
     RECT  81.9 75.541 82.458 75.667 ;
     RECT  84.888 75.499 84.906 75.691 ;
     RECT  45.615 75.631 47.466 75.695 ;
     RECT  79.776 75.667 79.866 75.695 ;
     RECT  81 75.541 81.09 75.695 ;
     RECT  77.868 75.659 78.57 75.811 ;
     RECT  42.516 75.497 42.606 75.839 ;
     RECT  81.9 75.667 82.602 75.839 ;
     RECT  81 75.695 81.018 75.929 ;
     RECT  81.9 75.839 82.062 75.929 ;
     RECT  84.888 75.691 85.482 75.929 ;
     RECT  86.292 75.595 86.31 75.979 ;
     RECT  42.588 75.839 42.606 76.037 ;
     RECT  77.724 75.811 78.57 76.045 ;
     RECT  86.256 75.979 86.31 76.073 ;
     RECT  74.664 75.469 74.682 76.081 ;
     RECT  41.688 75.569 41.706 76.109 ;
     RECT  86.292 76.073 86.31 76.109 ;
     RECT  79.776 75.695 79.794 76.171 ;
     RECT  46.764 75.695 47.466 76.199 ;
     RECT  74.664 76.081 74.718 76.199 ;
     RECT  77.58 76.045 78.57 76.199 ;
     RECT  79.488 76.171 79.794 76.199 ;
     RECT  84.888 75.929 84.906 76.199 ;
     RECT  77.58 76.199 78.498 76.253 ;
     RECT  79.488 76.199 79.506 76.253 ;
     RECT  48.852 73.237 48.87 76.279 ;
     RECT  47.448 76.199 47.466 76.351 ;
     RECT  74.7 76.199 74.718 76.379 ;
     RECT  47.448 76.351 47.61 76.469 ;
     RECT  47.448 76.469 47.466 76.505 ;
     RECT  48.852 76.279 49.518 76.621 ;
     RECT  5.76 76.699 5.778 76.711 ;
     RECT  5.76 76.711 6.066 77.009 ;
     RECT  48.528 76.621 49.518 77.045 ;
     RECT  48.564 77.045 49.518 77.395 ;
     RECT  2.415 69.557 2.697 77.515 ;
     RECT  24.015 57.641 24.297 77.521 ;
     RECT  48.564 77.395 49.59 77.521 ;
     RECT  48.564 77.521 49.986 77.549 ;
     RECT  7.815 69.533 8.097 77.557 ;
     RECT  7.815 77.557 8.154 77.563 ;
     RECT  6.84 77.563 6.858 77.593 ;
     RECT  7.815 77.563 8.442 77.593 ;
     RECT  5.76 77.009 5.85 77.629 ;
     RECT  5.544 77.629 5.85 77.657 ;
     RECT  0.108 77.395 0.126 77.659 ;
     RECT  4.572 77.431 4.59 77.659 ;
     RECT  5.544 77.657 5.67 77.659 ;
     RECT  45.615 75.695 45.897 77.665 ;
     RECT  2.304 77.515 2.697 77.701 ;
     RECT  4.572 77.659 5.67 77.701 ;
     RECT  45.615 77.665 46.386 77.701 ;
     RECT  49.392 77.549 49.986 77.701 ;
     RECT  51.015 2.413 51.297 77.701 ;
     RECT  0.108 77.659 0.198 77.729 ;
     RECT  0.108 77.729 0.162 77.741 ;
     RECT  45.615 77.701 46.638 77.755 ;
     RECT  56.415 52.889 56.697 77.791 ;
     RECT  56.304 77.791 56.697 77.837 ;
     RECT  48.564 77.549 48.582 77.863 ;
     RECT  2.304 77.701 2.718 77.935 ;
     RECT  85.5 77.971 85.518 78.029 ;
     RECT  79.848 77.971 79.866 78.043 ;
     RECT  81.9 75.929 81.918 78.043 ;
     RECT  45.615 77.755 47.286 78.061 ;
     RECT  48.348 77.863 48.582 78.061 ;
     RECT  49.392 77.701 51.297 78.061 ;
     RECT  27.756 77.971 27.774 78.089 ;
     RECT  80.64 77.971 80.658 78.089 ;
     RECT  81.756 78.043 81.918 78.089 ;
     RECT  86.292 78.061 86.31 78.125 ;
     RECT  6.84 77.593 8.442 78.169 ;
     RECT  25.524 77.971 25.542 78.169 ;
     RECT  83.415 67.199 83.697 78.187 ;
     RECT  2.304 77.935 2.862 78.241 ;
     RECT  25.524 78.169 25.938 78.241 ;
     RECT  79.812 78.043 79.866 78.241 ;
     RECT  6.804 78.169 8.442 78.269 ;
     RECT  77.868 76.253 78.498 78.269 ;
     RECT  7.815 78.269 8.442 78.331 ;
     RECT  25.524 78.241 26.01 78.359 ;
     RECT  83.415 78.187 84.366 78.359 ;
     RECT  77.868 78.269 78.426 78.368 ;
     RECT  23.364 77.521 24.297 78.403 ;
     RECT  45.54 78.061 48.582 78.403 ;
     RECT  49.392 78.061 51.39 78.403 ;
     RECT  79.812 78.241 80.37 78.431 ;
     RECT  85.464 78.283 85.482 78.467 ;
     RECT  2.304 78.241 3.258 78.475 ;
     RECT  6.804 78.269 7.074 78.475 ;
     RECT  77.868 78.368 78.297 78.539 ;
     RECT  0.144 77.741 0.162 78.605 ;
     RECT  4.176 77.701 5.67 78.619 ;
     RECT  6.768 78.475 7.074 78.619 ;
     RECT  43.956 78.511 44.298 78.619 ;
     RECT  45.54 78.403 51.39 78.619 ;
     RECT  2.304 78.475 3.402 78.629 ;
     RECT  4.176 78.619 7.074 78.629 ;
     RECT  42.408 78.511 42.426 78.629 ;
     RECT  22.968 78.403 24.297 78.637 ;
     RECT  43.956 78.619 51.39 78.637 ;
     RECT  2.304 78.629 3.258 78.653 ;
     RECT  79.812 78.431 79.83 78.653 ;
     RECT  4.32 78.629 7.074 78.665 ;
     RECT  0.108 78.637 0.126 78.701 ;
     RECT  4.32 78.665 6.21 78.749 ;
     RECT  7.815 78.331 8.478 78.781 ;
     RECT  42.732 78.637 42.786 78.781 ;
     RECT  7.056 78.665 7.074 78.809 ;
     RECT  71.496 69.187 71.514 78.809 ;
     RECT  4.428 78.749 6.21 78.893 ;
     RECT  4.428 78.893 5.094 78.899 ;
     RECT  7.815 78.781 8.514 78.899 ;
     RECT  43.884 78.637 51.39 78.901 ;
     RECT  10.8 78.871 10.818 78.907 ;
     RECT  22.896 78.637 24.297 78.907 ;
     RECT  4.5 78.899 5.058 78.935 ;
     RECT  5.904 78.893 6.21 78.935 ;
     RECT  7.815 78.899 8.406 78.935 ;
     RECT  25.524 78.359 25.938 78.935 ;
     RECT  10.8 78.907 10.854 78.943 ;
     RECT  42.732 78.781 42.822 78.943 ;
     RECT  2.304 78.653 2.934 79.007 ;
     RECT  25.524 78.935 25.758 79.015 ;
     RECT  43.704 78.901 51.39 79.015 ;
     RECT  2.415 79.007 2.934 79.043 ;
     RECT  26.784 78.943 26.802 79.051 ;
     RECT  4.788 78.935 5.058 79.079 ;
     RECT  5.904 78.935 5.922 79.079 ;
     RECT  10.728 78.943 10.854 79.079 ;
     RECT  26.784 79.051 26.874 79.079 ;
     RECT  4.788 79.079 4.95 79.169 ;
     RECT  26.856 79.079 26.874 79.169 ;
     RECT  4.788 79.169 4.806 79.205 ;
     RECT  25.344 79.015 25.758 79.205 ;
     RECT  38.772 78.709 38.79 79.205 ;
     RECT  43.704 79.015 51.606 79.205 ;
     RECT  40.215 69.719 40.497 79.213 ;
     RECT  42.732 78.943 42.966 79.213 ;
     RECT  43.704 79.205 51.462 79.213 ;
     RECT  21.096 78.511 21.114 79.241 ;
     RECT  22.824 78.907 24.297 79.321 ;
     RECT  40.215 79.213 41.058 79.349 ;
     RECT  22.824 79.321 24.426 79.439 ;
     RECT  42.732 79.213 51.462 79.439 ;
     RECT  22.824 79.439 24.297 79.475 ;
     RECT  25.344 79.205 25.362 79.475 ;
     RECT  63.288 79.177 63.306 79.475 ;
     RECT  78.015 78.539 78.297 79.555 ;
     RECT  84.888 79.519 84.906 79.565 ;
     RECT  42.732 79.439 44.262 79.591 ;
     RECT  41.724 79.591 41.742 79.709 ;
     RECT  22.824 79.475 22.842 79.745 ;
     RECT  42.516 79.591 44.262 79.757 ;
     RECT  77.616 79.555 78.297 79.805 ;
     RECT  42.516 79.757 42.534 79.819 ;
     RECT  80.388 79.591 80.406 79.819 ;
     RECT  42.372 79.819 42.534 79.979 ;
     RECT  42.372 79.979 42.39 80.015 ;
     RECT  45.072 79.439 51.462 80.059 ;
     RECT  79.668 79.819 80.406 80.131 ;
     RECT  43.308 79.757 44.262 80.221 ;
     RECT  45.072 80.059 51.606 80.221 ;
     RECT  54.684 80.095 54.702 80.249 ;
     RECT  43.308 80.221 51.606 80.251 ;
     RECT  43.308 80.251 51.822 80.285 ;
     RECT  59.292 80.221 59.31 80.293 ;
     RECT  44.352 80.285 51.822 80.321 ;
     RECT  59.292 80.293 59.346 80.329 ;
     RECT  44.712 80.321 51.75 80.357 ;
     RECT  79.668 80.131 80.982 80.365 ;
     RECT  83.415 78.359 83.697 80.365 ;
     RECT  61.815 52.979 62.097 80.401 ;
     RECT  65.772 80.365 65.79 80.401 ;
     RECT  67.215 52.979 67.497 80.401 ;
     RECT  78.015 79.805 78.297 80.401 ;
     RECT  79.668 80.365 81.45 80.401 ;
     RECT  82.188 80.221 82.206 80.401 ;
     RECT  82.98 80.365 83.697 80.401 ;
     RECT  65.592 80.401 65.79 80.491 ;
     RECT  85.464 80.329 85.482 80.491 ;
     RECT  59.292 80.329 59.886 80.519 ;
     RECT  64.98 80.491 65.79 80.519 ;
     RECT  79.452 80.401 81.45 80.519 ;
     RECT  59.328 80.519 59.886 80.555 ;
     RECT  64.98 80.519 65.61 80.555 ;
     RECT  78.015 80.401 78.678 80.563 ;
     RECT  79.452 80.519 80.01 80.563 ;
     RECT  82.188 80.401 83.697 80.563 ;
     RECT  61.815 80.401 62.73 80.564 ;
     RECT  78.015 80.563 80.01 80.578 ;
     RECT  82.188 80.563 84.366 80.587 ;
     RECT  85.464 80.491 85.518 80.587 ;
     RECT  64.98 80.555 64.998 80.627 ;
     RECT  59.868 80.555 59.886 80.663 ;
     RECT  78.015 80.578 79.506 80.671 ;
     RECT  82.188 80.587 85.518 80.717 ;
     RECT  77.58 80.671 79.506 80.731 ;
     RECT  63.288 80.671 63.306 80.761 ;
     RECT  80.784 80.519 81.45 80.761 ;
     RECT  82.188 80.717 83.754 80.761 ;
     RECT  43.344 80.285 43.362 80.789 ;
     RECT  44.712 80.357 51.642 80.789 ;
     RECT  84.528 80.717 85.518 80.813 ;
     RECT  64.656 80.635 64.674 80.825 ;
     RECT  80.784 80.761 83.754 80.861 ;
     RECT  66.672 80.401 67.497 80.869 ;
     RECT  63.288 80.761 63.558 80.905 ;
     RECT  2.415 79.043 2.697 81.067 ;
     RECT  63.288 80.905 63.702 81.095 ;
     RECT  66.456 80.869 67.497 81.095 ;
     RECT  77.436 80.731 79.506 81.131 ;
     RECT  2.415 81.067 3.366 81.139 ;
     RECT  63.54 81.095 63.702 81.139 ;
     RECT  2.415 81.139 3.402 81.175 ;
     RECT  45.144 80.789 51.642 81.203 ;
     RECT  63.54 81.139 64.602 81.203 ;
     RECT  74.664 80.941 74.682 81.211 ;
     RECT  63.684 81.203 64.602 81.239 ;
     RECT  86.292 81.163 86.31 81.239 ;
     RECT  45.216 81.203 51.642 81.329 ;
     RECT  64.584 81.239 64.602 81.329 ;
     RECT  76.392 80.833 76.41 81.329 ;
     RECT  45.216 81.329 46.062 81.365 ;
     RECT  47.268 81.329 51.642 81.365 ;
     RECT  78.015 81.131 79.506 81.373 ;
     RECT  61.815 80.564 62.097 81.445 ;
     RECT  84.528 80.813 85.482 81.547 ;
     RECT  63.684 81.239 63.702 81.635 ;
     RECT  50.796 81.365 51.642 81.643 ;
     RECT  61.56 81.445 62.097 81.643 ;
     RECT  78.015 81.373 79.83 81.677 ;
     RECT  61.56 81.643 62.73 81.707 ;
     RECT  83.16 80.861 83.697 81.715 ;
     RECT  84.492 81.547 85.482 81.715 ;
     RECT  80.784 80.861 82.17 81.751 ;
     RECT  83.16 81.715 85.482 81.751 ;
     RECT  66.708 81.095 67.497 81.779 ;
     RECT  47.268 81.365 49.698 81.869 ;
     RECT  50.796 81.643 52.002 81.869 ;
     RECT  80.064 81.751 85.482 81.869 ;
     RECT  48.42 81.869 49.698 81.905 ;
     RECT  61.815 81.707 62.73 81.905 ;
     RECT  80.064 81.869 82.098 81.941 ;
     RECT  83.232 81.869 84.906 81.941 ;
     RECT  83.415 81.941 84.906 81.965 ;
     RECT  74.664 81.211 74.718 82.013 ;
     RECT  74.7 82.013 74.718 82.049 ;
     RECT  78.015 81.677 79.254 82.049 ;
     RECT  80.064 81.941 81.954 82.049 ;
     RECT  84.888 81.965 84.906 82.049 ;
     RECT  47.268 81.869 47.502 82.139 ;
     RECT  48.42 81.905 48.438 82.139 ;
     RECT  49.392 81.905 49.698 82.139 ;
     RECT  78.015 82.049 78.786 82.139 ;
     RECT  80.064 82.049 81.27 82.139 ;
     RECT  47.304 82.139 47.502 82.175 ;
     RECT  78.015 82.139 78.39 82.175 ;
     RECT  50.796 81.869 51.297 82.183 ;
     RECT  80.748 82.139 80.766 82.211 ;
     RECT  49.5 82.139 49.698 82.291 ;
     RECT  50.508 82.183 51.297 82.291 ;
     RECT  49.5 82.291 51.297 82.445 ;
     RECT  2.415 81.175 3.582 82.603 ;
     RECT  2.304 82.603 3.582 83.219 ;
     RECT  82.368 83.191 82.386 83.227 ;
     RECT  49.5 82.445 50.058 83.327 ;
     RECT  50.04 83.327 50.058 83.399 ;
     RECT  2.304 83.219 3.402 83.759 ;
     RECT  82.224 83.227 82.386 83.759 ;
     RECT  84.888 83.731 84.906 83.789 ;
     RECT  2.304 83.759 2.697 83.795 ;
     RECT  82.224 83.759 82.242 83.795 ;
     RECT  2.415 83.795 2.697 83.987 ;
     RECT  7.815 78.935 8.097 83.987 ;
     RECT  13.215 57.641 13.497 83.987 ;
     RECT  18.615 61.961 18.897 83.987 ;
     RECT  24.015 79.475 24.297 83.987 ;
     RECT  29.415 57.641 29.697 83.987 ;
     RECT  34.815 57.641 35.097 83.987 ;
     RECT  40.215 79.349 40.497 83.987 ;
     RECT  45.615 81.365 45.897 83.987 ;
     RECT  51.015 82.445 51.297 83.987 ;
     RECT  56.415 77.837 56.697 83.987 ;
     RECT  61.815 81.905 62.097 83.987 ;
     RECT  67.215 81.779 67.497 83.987 ;
     RECT  72.615 56.219 72.897 83.987 ;
     RECT  78.015 82.175 78.297 83.987 ;
     RECT  83.415 81.965 83.697 83.987 ;
     RECT  2.415 83.987 2.505 84.257 ;
     RECT  7.815 83.987 7.905 84.257 ;
     RECT  13.215 83.987 13.305 84.257 ;
     RECT  18.615 83.987 18.705 84.257 ;
     RECT  24.015 83.987 24.105 84.257 ;
     RECT  29.415 83.987 29.505 84.257 ;
     RECT  34.815 83.987 34.905 84.257 ;
     RECT  40.215 83.987 40.305 84.257 ;
     RECT  45.615 83.987 45.705 84.257 ;
     RECT  51.015 83.987 51.105 84.257 ;
     RECT  56.415 83.987 56.505 84.257 ;
     RECT  61.815 83.987 61.905 84.257 ;
     RECT  67.215 83.987 67.305 84.257 ;
     RECT  72.615 83.987 72.705 84.257 ;
     RECT  78.015 83.987 78.105 84.257 ;
     RECT  83.415 83.987 83.505 84.257 ;
    LAYER M4 ;
     RECT  0.084 32.688 0.371 32.712 ;
     RECT  0.06 32.712 0.371 32.784 ;
     RECT  0.084 32.784 0.371 32.808 ;
     RECT  0.06 32.808 0.371 32.88 ;
     RECT  0.084 32.88 0.371 32.904 ;
     RECT  0.06 32.904 0.371 32.976 ;
     RECT  0.084 32.976 0.371 33 ;
     RECT  0.06 33 0.371 33.072 ;
     RECT  0.084 33.072 0.371 33.096 ;
     RECT  0.06 33.096 0.371 33.168 ;
     RECT  0.084 33.168 0.371 33.192 ;
     RECT  0.06 33.192 0.371 33.264 ;
     RECT  0.084 33.264 0.371 33.288 ;
     RECT  0.06 33.288 0.371 33.36 ;
     RECT  0.084 33.36 0.371 33.384 ;
     RECT  0.06 33.384 0.371 33.456 ;
     RECT  0.084 33.456 0.371 33.48 ;
     RECT  0.06 33.48 0.371 33.552 ;
     RECT  0.084 33.552 0.371 33.576 ;
     RECT  0.06 33.576 0.371 33.648 ;
     RECT  0.084 33.648 0.371 33.672 ;
     RECT  0.06 33.672 0.371 33.744 ;
     RECT  0.084 33.744 0.371 33.768 ;
     RECT  0.06 33.768 0.371 33.84 ;
     RECT  0.084 33.84 0.371 33.864 ;
     RECT  0.06 33.864 0.371 33.936 ;
     RECT  0.084 33.936 0.371 33.96 ;
     RECT  0.06 33.96 0.371 34.032 ;
     RECT  0.084 34.032 0.371 34.056 ;
     RECT  0.06 34.056 0.371 34.128 ;
     RECT  0.084 34.128 0.371 34.152 ;
     RECT  0.06 34.152 0.371 34.224 ;
     RECT  0.084 34.224 0.371 34.248 ;
     RECT  0.06 34.248 0.371 34.32 ;
     RECT  0.084 34.32 0.371 34.344 ;
     RECT  0.06 34.344 0.371 34.416 ;
     RECT  0.084 34.416 0.371 34.44 ;
     RECT  0.06 34.44 0.371 34.512 ;
     RECT  0.084 34.512 0.371 34.536 ;
     RECT  0.06 34.536 0.371 34.608 ;
     RECT  0.084 34.608 0.371 34.632 ;
     RECT  0.06 34.632 0.371 34.704 ;
     RECT  0.084 34.704 0.371 34.728 ;
     RECT  0.06 34.728 0.371 34.8 ;
     RECT  0.084 34.8 0.371 34.824 ;
     RECT  0.06 34.824 0.371 34.896 ;
     RECT  0.084 34.896 0.371 34.92 ;
     RECT  0.06 34.92 0.371 34.992 ;
     RECT  0.084 34.992 0.371 35.016 ;
     RECT  0.06 35.016 0.371 35.088 ;
     RECT  0.084 35.088 0.371 35.112 ;
     RECT  0.06 35.112 0.371 35.184 ;
     RECT  0.084 35.184 0.371 35.208 ;
     RECT  0.06 35.208 0.371 35.28 ;
     RECT  0.084 35.28 0.371 35.304 ;
     RECT  0.06 35.304 0.371 35.376 ;
     RECT  0.084 35.376 0.371 35.4 ;
     RECT  0.06 35.4 0.371 35.472 ;
     RECT  0.084 35.472 0.371 35.496 ;
     RECT  0.06 35.496 0.371 35.568 ;
     RECT  0.084 35.568 0.371 35.592 ;
     RECT  0.06 35.592 0.371 35.664 ;
     RECT  0.084 35.664 0.371 35.688 ;
     RECT  0.06 35.688 0.371 35.76 ;
     RECT  0.084 35.76 0.371 35.784 ;
     RECT  0.06 35.784 0.371 35.856 ;
     RECT  0.084 35.856 0.371 35.88 ;
     RECT  0.06 35.88 0.371 35.952 ;
     RECT  0.084 35.952 0.371 35.976 ;
     RECT  0.06 35.976 0.371 36.048 ;
     RECT  0.084 36.048 0.371 36.072 ;
     RECT  0.06 36.072 0.371 36.144 ;
     RECT  0.084 36.144 0.371 36.168 ;
     RECT  0.06 36.168 0.371 36.24 ;
     RECT  0.084 36.24 0.371 36.264 ;
     RECT  0.06 36.264 0.371 36.336 ;
     RECT  0.084 36.336 0.371 36.36 ;
     RECT  0.06 36.36 0.371 36.432 ;
     RECT  0.084 36.432 0.371 36.456 ;
     RECT  0.06 36.456 0.371 36.528 ;
     RECT  0.084 36.528 0.371 36.552 ;
     RECT  0.06 36.552 0.371 36.624 ;
     RECT  0.084 36.624 0.371 36.648 ;
     RECT  0.06 36.648 0.371 36.72 ;
     RECT  0.084 36.72 0.371 36.744 ;
     RECT  0.06 36.744 0.371 36.816 ;
     RECT  0.084 36.816 0.371 36.84 ;
     RECT  0.06 36.84 0.371 36.912 ;
     RECT  0.084 36.912 0.371 36.936 ;
     RECT  0.06 36.936 0.371 37.008 ;
     RECT  0.084 37.008 0.371 37.032 ;
     RECT  0.06 37.032 0.371 37.104 ;
     RECT  0.084 37.104 0.371 37.128 ;
     RECT  0.06 37.128 0.371 37.2 ;
     RECT  0.084 37.2 0.371 37.224 ;
     RECT  0.06 37.224 0.371 37.296 ;
     RECT  0.084 37.296 0.371 37.32 ;
     RECT  0.06 37.32 0.371 37.392 ;
     RECT  0.084 37.392 0.371 37.416 ;
     RECT  0.06 37.416 0.371 37.488 ;
     RECT  0.084 37.488 0.371 37.512 ;
     RECT  0.06 37.512 0.371 37.584 ;
     RECT  0.084 37.584 0.371 37.608 ;
     RECT  0.06 37.608 0.371 37.68 ;
     RECT  0.084 37.68 0.371 37.704 ;
     RECT  0.06 37.704 0.371 37.776 ;
     RECT  0.084 37.776 0.371 37.8 ;
     RECT  0.06 37.8 0.371 37.872 ;
     RECT  0.084 37.872 0.371 37.896 ;
     RECT  0.06 37.896 0.371 37.968 ;
     RECT  0.084 37.968 0.371 37.992 ;
     RECT  0.06 37.992 0.371 38.064 ;
     RECT  0.084 38.064 0.371 38.088 ;
     RECT  0.06 38.088 0.371 38.16 ;
     RECT  0.084 38.16 0.371 38.184 ;
     RECT  0.06 38.184 0.371 38.256 ;
     RECT  0.084 38.256 0.371 38.28 ;
     RECT  0.06 38.28 0.371 38.352 ;
     RECT  0.084 38.352 0.371 38.376 ;
     RECT  0.06 38.376 0.371 38.448 ;
     RECT  0.084 38.448 0.371 38.472 ;
     RECT  0.06 38.472 0.371 38.544 ;
     RECT  0.084 38.544 0.371 38.568 ;
     RECT  0.06 38.568 0.371 38.64 ;
     RECT  0.084 38.64 0.371 38.664 ;
     RECT  0.06 38.664 0.371 38.736 ;
     RECT  0.084 38.736 0.371 38.76 ;
     RECT  0.06 38.76 0.371 39.6 ;
     RECT  0.084 39.6 0.371 39.624 ;
     RECT  0.06 39.624 0.371 39.696 ;
     RECT  0.084 39.696 0.371 39.72 ;
     RECT  0.06 39.72 0.371 39.792 ;
     RECT  0.084 39.792 0.371 39.816 ;
     RECT  0.06 39.816 0.371 39.888 ;
     RECT  0.084 39.888 0.371 39.912 ;
     RECT  0.06 39.912 0.371 39.984 ;
     RECT  0.084 39.984 0.371 40.008 ;
     RECT  0.06 40.008 0.371 40.08 ;
     RECT  0.084 40.08 0.371 40.104 ;
     RECT  0.06 40.104 0.371 40.176 ;
     RECT  0.084 40.176 0.371 40.2 ;
     RECT  0.06 40.2 0.371 40.272 ;
     RECT  0.084 40.272 0.371 40.296 ;
     RECT  0.06 40.296 0.371 40.368 ;
     RECT  0.084 40.368 0.371 40.392 ;
     RECT  0.06 40.392 0.371 40.464 ;
     RECT  0.084 40.464 0.371 40.488 ;
     RECT  0.06 40.488 0.371 40.56 ;
     RECT  0.084 40.56 0.371 40.584 ;
     RECT  0.06 40.584 0.371 40.656 ;
     RECT  0.084 40.656 0.371 40.68 ;
     RECT  0.06 40.68 0.371 40.752 ;
     RECT  0.084 40.752 0.371 40.776 ;
     RECT  0.06 40.776 0.371 40.848 ;
     RECT  0.084 40.848 0.371 40.872 ;
     RECT  0.06 40.872 0.371 40.944 ;
     RECT  0.084 40.944 0.371 40.968 ;
     RECT  0.06 40.968 0.371 41.04 ;
     RECT  0.084 41.04 0.371 41.064 ;
     RECT  0.06 41.064 0.371 41.136 ;
     RECT  0.084 41.136 0.371 41.16 ;
     RECT  0.06 41.16 0.371 41.232 ;
     RECT  0.084 41.232 0.371 41.256 ;
     RECT  0.06 41.256 0.371 41.328 ;
     RECT  0.084 41.328 0.371 41.352 ;
     RECT  0.06 41.352 0.371 41.424 ;
     RECT  0.084 41.424 0.371 41.448 ;
     RECT  0.06 41.448 0.371 41.52 ;
     RECT  0.084 41.52 0.371 41.544 ;
     RECT  0.06 41.544 0.371 41.616 ;
     RECT  0.084 41.616 0.371 41.64 ;
     RECT  0.06 41.64 0.371 41.712 ;
     RECT  0.084 41.712 0.371 41.736 ;
     RECT  0.06 41.736 0.371 41.808 ;
     RECT  0.084 41.808 0.371 41.832 ;
     RECT  0.06 41.832 0.371 41.904 ;
     RECT  0.084 41.904 0.371 41.928 ;
     RECT  0.06 41.928 0.371 42 ;
     RECT  0.084 42 0.371 42.024 ;
     RECT  0.06 42.024 0.371 42.096 ;
     RECT  0.084 42.096 0.371 42.12 ;
     RECT  0.06 42.12 0.371 42.192 ;
     RECT  0.084 42.192 0.371 42.216 ;
     RECT  0.06 42.216 0.371 42.288 ;
     RECT  0.084 42.288 0.371 42.312 ;
     RECT  0.06 42.312 0.371 42.384 ;
     RECT  0.084 42.384 0.371 42.408 ;
     RECT  0.06 42.408 0.371 42.48 ;
     RECT  0.084 42.48 0.371 42.504 ;
     RECT  0.06 42.504 0.371 42.576 ;
     RECT  0.084 42.576 0.371 42.6 ;
     RECT  0.06 42.6 0.371 42.672 ;
     RECT  0.084 42.672 0.371 42.696 ;
     RECT  0.06 42.696 0.371 42.768 ;
     RECT  0.084 42.768 0.371 42.792 ;
     RECT  0.06 42.792 0.371 42.864 ;
     RECT  0.084 42.864 0.371 42.888 ;
     RECT  0.06 42.888 0.371 42.96 ;
     RECT  0.084 42.96 0.371 42.984 ;
     RECT  0.06 42.984 0.371 43.056 ;
     RECT  0.084 43.056 0.371 43.08 ;
     RECT  0.06 43.08 0.371 43.152 ;
     RECT  0.084 43.152 0.371 43.176 ;
     RECT  0.06 43.176 0.371 43.248 ;
     RECT  0.084 43.248 0.371 43.272 ;
     RECT  0.06 43.272 0.371 43.344 ;
     RECT  0.084 43.344 0.371 43.368 ;
     RECT  0.06 43.368 0.371 43.44 ;
     RECT  0.084 43.44 0.371 43.464 ;
     RECT  0.06 43.464 0.371 43.536 ;
     RECT  0.084 43.536 0.371 43.56 ;
     RECT  0.06 43.56 0.371 43.632 ;
     RECT  0.084 43.632 0.371 43.656 ;
     RECT  0.06 43.656 0.371 43.728 ;
     RECT  0.084 43.728 0.371 43.752 ;
     RECT  0.06 43.752 0.371 43.824 ;
     RECT  0.084 43.824 0.371 43.848 ;
     RECT  0.06 43.848 0.371 43.92 ;
     RECT  0.084 43.92 0.371 43.944 ;
     RECT  0.06 43.944 0.371 44.016 ;
     RECT  0.084 44.016 0.371 44.04 ;
     RECT  0.06 44.04 0.371 44.112 ;
     RECT  0.084 44.112 0.371 44.136 ;
     RECT  0.06 44.136 0.371 44.208 ;
     RECT  0.084 44.208 0.371 44.232 ;
     RECT  0.06 44.232 0.371 44.304 ;
     RECT  0.084 44.304 0.371 44.328 ;
     RECT  0.06 44.328 0.371 44.4 ;
     RECT  0.084 44.4 0.371 44.424 ;
     RECT  0.06 44.424 0.371 44.496 ;
     RECT  0.084 44.496 0.371 44.52 ;
     RECT  0.06 44.52 0.371 44.592 ;
     RECT  0.084 44.592 0.371 44.616 ;
     RECT  0.06 44.616 0.371 44.688 ;
     RECT  0.084 44.688 0.371 44.712 ;
     RECT  0.06 44.712 0.371 44.784 ;
     RECT  0.084 44.784 0.371 44.808 ;
     RECT  0.06 44.808 0.371 44.88 ;
     RECT  0.084 44.88 0.371 44.904 ;
     RECT  0.06 44.904 0.371 44.976 ;
     RECT  0.084 44.976 0.371 45 ;
     RECT  0.06 45 0.371 45.072 ;
     RECT  0.084 45.072 0.371 45.096 ;
     RECT  0.06 45.096 0.371 45.168 ;
     RECT  0.084 45.168 0.371 45.192 ;
     RECT  0.06 45.192 0.371 45.264 ;
     RECT  0.084 45.264 0.371 45.288 ;
     RECT  0.06 45.288 0.371 45.36 ;
     RECT  0.084 45.36 0.371 45.384 ;
     RECT  0.06 45.384 0.371 45.456 ;
     RECT  0.084 45.456 0.371 45.48 ;
     RECT  0.06 45.48 0.371 45.552 ;
     RECT  0.084 45.552 0.371 45.576 ;
     RECT  0.06 45.576 0.371 45.648 ;
     RECT  0.084 45.648 0.371 45.672 ;
     RECT  0.06 45.672 0.371 45.744 ;
     RECT  0.084 45.744 0.371 45.768 ;
     RECT  0.06 45.768 0.371 45.84 ;
     RECT  0.084 45.84 0.371 45.864 ;
     RECT  0.06 45.864 0.371 45.936 ;
     RECT  0.084 45.936 0.371 45.96 ;
     RECT  0.06 45.96 0.371 46.032 ;
     RECT  0.084 46.032 0.371 46.056 ;
     RECT  0.06 46.056 0.371 46.128 ;
     RECT  0.084 46.128 0.371 46.152 ;
     RECT  0.06 46.152 0.371 46.224 ;
     RECT  0.084 46.224 0.371 46.248 ;
     RECT  0.06 46.248 0.371 46.32 ;
     RECT  0.084 46.32 0.371 46.344 ;
     RECT  0.06 46.344 0.371 46.416 ;
     RECT  0.084 46.416 0.371 46.44 ;
     RECT  0.06 46.44 0.371 46.512 ;
     RECT  0.084 46.512 0.371 46.536 ;
     RECT  0.06 46.536 0.371 46.608 ;
     RECT  0.084 46.608 0.371 46.632 ;
     RECT  0.06 46.632 0.371 46.704 ;
     RECT  0.084 46.704 0.371 46.728 ;
     RECT  0.06 46.728 0.371 46.8 ;
     RECT  0.084 46.8 0.371 46.824 ;
     RECT  0.06 46.824 0.371 46.896 ;
     RECT  0.084 46.896 0.371 46.92 ;
     RECT  0.06 46.92 0.371 46.992 ;
     RECT  0.084 46.992 0.371 47.016 ;
     RECT  0.06 47.016 0.371 47.088 ;
     RECT  0.084 47.088 0.371 47.112 ;
     RECT  0.06 47.112 0.371 47.184 ;
     RECT  0.084 47.184 0.371 47.208 ;
     RECT  0.06 47.208 0.371 47.28 ;
     RECT  0.084 47.28 0.371 47.304 ;
     RECT  0.06 47.304 0.371 47.376 ;
     RECT  0.084 47.376 0.371 47.4 ;
     RECT  0.06 47.4 0.371 47.472 ;
     RECT  0.084 47.472 0.371 47.496 ;
     RECT  0.06 47.496 0.371 47.568 ;
     RECT  0.084 47.568 0.371 47.592 ;
     RECT  0.06 47.592 0.371 47.664 ;
     RECT  0.084 47.664 0.371 47.688 ;
     RECT  0.06 47.688 0.371 47.76 ;
     RECT  0.084 47.76 0.371 47.784 ;
     RECT  0.06 47.784 0.371 47.856 ;
     RECT  0.084 47.856 0.371 47.88 ;
     RECT  0.06 47.88 0.371 47.952 ;
     RECT  0.084 47.952 0.371 47.976 ;
     RECT  0.06 47.976 0.371 48.048 ;
     RECT  0.084 48.048 0.371 48.072 ;
     RECT  0.06 48.072 0.371 48.144 ;
     RECT  0.084 48.144 0.371 48.168 ;
     RECT  0.06 48.168 0.371 48.24 ;
     RECT  0.084 48.24 0.371 48.264 ;
     RECT  0.06 48.264 0.371 48.336 ;
     RECT  0.084 48.336 0.371 48.36 ;
     RECT  0.06 48.36 0.371 48.432 ;
     RECT  0.084 48.432 0.371 48.456 ;
     RECT  0.06 48.456 0.371 48.528 ;
     RECT  0.084 48.528 0.371 48.552 ;
     RECT  0.06 48.552 0.371 48.624 ;
     RECT  0.084 48.624 0.371 48.648 ;
     RECT  0.06 48.648 0.371 48.72 ;
     RECT  0.084 48.72 0.371 48.744 ;
     RECT  0.06 48.744 0.371 48.816 ;
     RECT  0.084 48.816 0.371 48.84 ;
     RECT  0.06 48.84 0.371 48.912 ;
     RECT  0.084 48.912 0.371 48.936 ;
     RECT  0.06 48.936 0.371 49.008 ;
     RECT  0.084 49.008 0.371 49.032 ;
     RECT  0.06 49.032 0.371 49.104 ;
     RECT  0.084 49.104 0.371 49.128 ;
     RECT  0.06 49.128 0.371 49.2 ;
     RECT  0.084 49.2 0.371 49.224 ;
     RECT  0.06 49.224 0.371 49.296 ;
     RECT  0.084 49.296 0.371 49.32 ;
     RECT  0.06 49.32 0.371 49.392 ;
     RECT  0.084 49.392 0.371 49.416 ;
     RECT  0.06 49.416 0.371 49.488 ;
     RECT  0.084 49.488 0.371 49.512 ;
     RECT  0.06 49.512 0.371 49.584 ;
     RECT  0.084 49.584 0.371 49.608 ;
     RECT  0.06 49.608 0.371 49.68 ;
     RECT  0.084 49.68 0.371 49.704 ;
     RECT  0.06 49.704 0.371 49.776 ;
     RECT  0.084 49.776 0.371 49.8 ;
     RECT  0.06 49.8 0.371 49.872 ;
     RECT  0.084 49.872 0.371 49.896 ;
     RECT  0.06 49.896 0.371 49.968 ;
     RECT  0.084 49.968 0.371 49.992 ;
     RECT  0.06 49.992 0.371 50.064 ;
     RECT  0.084 50.064 0.371 50.088 ;
     RECT  0.06 50.088 0.371 50.16 ;
     RECT  0.084 50.16 0.371 50.184 ;
     RECT  0.06 50.184 0.371 50.256 ;
     RECT  0.084 50.256 0.371 50.28 ;
     RECT  0.06 50.28 0.371 50.352 ;
     RECT  0.084 50.352 0.371 50.376 ;
     RECT  0.06 50.376 0.371 50.448 ;
     RECT  0.084 50.448 0.371 50.472 ;
     RECT  0.06 50.472 0.371 50.544 ;
     RECT  0.084 50.544 0.371 50.568 ;
     RECT  0.06 50.568 0.371 50.64 ;
     RECT  0.084 50.64 0.371 50.664 ;
     RECT  0.06 50.664 0.371 50.736 ;
     RECT  0.084 50.736 0.371 50.76 ;
     RECT  0.06 50.76 0.371 50.832 ;
     RECT  0.084 50.832 0.371 50.856 ;
     RECT  0.06 50.856 0.371 50.928 ;
     RECT  0.084 50.928 0.371 50.952 ;
     RECT  0.06 50.952 0.371 51.024 ;
     RECT  0.084 51.024 0.371 51.048 ;
     RECT  0.06 51.048 0.371 51.12 ;
     RECT  0.084 51.12 0.371 51.144 ;
     RECT  0.06 51.144 0.371 51.216 ;
     RECT  0.084 51.216 0.371 51.24 ;
     RECT  0.06 51.24 0.371 51.312 ;
     RECT  0.084 51.312 0.371 51.336 ;
     RECT  0.06 51.336 0.371 51.408 ;
     RECT  0.084 51.408 0.371 51.432 ;
     RECT  0.06 51.432 0.371 51.504 ;
     RECT  0.084 51.504 0.371 51.528 ;
     RECT  0.06 51.528 0.371 51.6 ;
     RECT  0.084 51.6 0.371 51.624 ;
     RECT  0.06 51.624 0.371 51.696 ;
     RECT  0.084 51.696 0.371 51.72 ;
     RECT  0.06 51.72 0.371 51.792 ;
     RECT  0.084 51.792 0.371 51.816 ;
     RECT  0.06 51.816 0.371 51.888 ;
     RECT  0.084 51.888 0.371 51.912 ;
     RECT  0.06 51.912 0.371 51.984 ;
     RECT  0.084 51.984 0.371 52.008 ;
     RECT  0.06 52.008 0.371 52.08 ;
     RECT  0.084 52.08 0.371 52.104 ;
     RECT  0.06 52.104 0.371 52.176 ;
     RECT  0.084 52.176 0.371 52.2 ;
     RECT  0.06 52.2 0.371 52.272 ;
     RECT  0.084 52.272 0.371 52.296 ;
     RECT  0.06 52.296 0.371 52.368 ;
     RECT  0.084 52.368 0.371 52.392 ;
     RECT  0.06 52.392 0.371 52.464 ;
     RECT  0.084 52.464 0.371 52.488 ;
     RECT  0.06 52.488 0.371 52.56 ;
     RECT  0.084 52.56 0.371 52.584 ;
     RECT  0.06 52.584 0.371 52.656 ;
     RECT  0.084 52.656 0.371 52.68 ;
     RECT  0.06 52.68 0.371 52.752 ;
     RECT  0.084 52.752 0.371 52.776 ;
     RECT  0.06 52.776 0.371 52.848 ;
     RECT  0.084 52.848 0.371 52.872 ;
     RECT  0.06 52.872 0.371 52.944 ;
     RECT  0.084 52.944 0.371 52.968 ;
     RECT  0.06 52.968 0.371 53.04 ;
     RECT  0.084 53.04 0.371 53.064 ;
     RECT  0.06 53.064 0.371 53.136 ;
     RECT  0.084 53.136 0.371 53.16 ;
     RECT  0.06 53.16 0.371 53.232 ;
     RECT  0.084 53.232 0.371 53.256 ;
     RECT  0.06 53.256 0.371 53.328 ;
     RECT  0.084 53.328 0.371 53.352 ;
     RECT  0.06 53.352 0.371 53.424 ;
     RECT  0.084 53.424 0.371 53.448 ;
     RECT  0.06 53.448 0.371 53.52 ;
     RECT  0.084 53.52 0.371 53.544 ;
     RECT  0.06 53.544 0.371 53.616 ;
     RECT  0.084 53.616 0.371 53.64 ;
     RECT  0.06 53.64 0.371 53.712 ;
     RECT  0.084 53.712 0.371 53.736 ;
     RECT  0.06 53.736 0.371 53.808 ;
     RECT  0.084 53.808 0.371 53.832 ;
     RECT  0.06 53.832 0.371 53.904 ;
     RECT  0.084 53.904 0.371 53.928 ;
     RECT  0.06 53.928 0.371 54 ;
     RECT  0.084 54 0.371 54.024 ;
     RECT  0.06 54.024 0.371 54.096 ;
     RECT  0.084 54.096 0.371 54.12 ;
     RECT  0.06 54.12 0.371 54.192 ;
     RECT  0.084 54.192 0.371 54.216 ;
     RECT  0.06 54.216 0.371 54.288 ;
     RECT  0.084 54.288 0.371 54.312 ;
     RECT  0.06 54.312 0.371 54.384 ;
     RECT  0.084 54.384 0.371 54.408 ;
     RECT  0.06 54.408 0.371 54.48 ;
     RECT  0.084 54.48 0.371 54.504 ;
     RECT  0.06 54.504 0.371 54.576 ;
     RECT  0.084 54.576 0.371 54.6 ;
     RECT  0.06 54.6 0.371 54.672 ;
     RECT  0.084 54.672 0.371 54.696 ;
     RECT  0.06 54.696 0.371 54.768 ;
     RECT  0.084 54.768 0.371 54.792 ;
     RECT  0.06 54.792 0.371 54.864 ;
     RECT  0.084 54.864 0.371 54.888 ;
     RECT  0.06 54.888 0.371 54.96 ;
     RECT  0.084 54.96 0.371 54.984 ;
     RECT  0.06 54.984 0.371 55.056 ;
     RECT  0.084 55.056 0.371 55.08 ;
     RECT  0.06 55.08 0.371 55.152 ;
     RECT  0.084 55.152 0.371 55.176 ;
     RECT  0.06 55.176 0.371 55.248 ;
     RECT  0.084 55.248 0.371 55.272 ;
     RECT  0.06 55.272 0.371 55.344 ;
     RECT  0.084 55.344 0.371 55.368 ;
     RECT  0.06 55.368 0.371 55.44 ;
     RECT  0.084 55.44 0.371 55.464 ;
     RECT  0.06 55.464 0.371 55.536 ;
     RECT  0.084 55.536 0.371 55.56 ;
     RECT  0.06 55.56 0.371 55.632 ;
     RECT  0.084 55.632 0.371 55.656 ;
     RECT  0.06 55.656 0.371 55.728 ;
     RECT  0.084 55.728 0.371 55.752 ;
     RECT  0.06 55.752 0.371 55.824 ;
     RECT  0.084 55.824 0.371 55.848 ;
     RECT  0.06 55.848 0.371 55.92 ;
     RECT  0.084 55.92 0.371 55.944 ;
     RECT  0.06 55.944 0.371 56.016 ;
     RECT  0.084 56.016 0.371 56.04 ;
     RECT  0.06 56.04 0.371 56.112 ;
     RECT  0.084 56.112 0.371 56.136 ;
     RECT  0.06 56.136 0.371 56.208 ;
     RECT  0.084 56.208 0.371 56.232 ;
     RECT  0.06 56.232 0.371 56.304 ;
     RECT  0.084 56.304 0.371 56.328 ;
     RECT  0.06 56.328 0.371 56.4 ;
     RECT  0.084 56.4 0.371 56.424 ;
     RECT  0.06 56.424 0.371 56.496 ;
     RECT  0.084 56.496 0.371 56.52 ;
     RECT  0.06 56.52 0.371 56.592 ;
     RECT  0.084 56.592 0.371 56.616 ;
     RECT  0.06 56.616 0.371 56.688 ;
     RECT  0.084 56.688 0.371 56.712 ;
     RECT  0.06 56.712 0.371 56.784 ;
     RECT  0.084 56.784 0.371 56.808 ;
     RECT  0.06 56.808 0.371 56.88 ;
     RECT  0.084 56.88 0.371 56.904 ;
     RECT  0.06 56.904 0.371 56.976 ;
     RECT  0.084 56.976 0.371 57 ;
     RECT  0.06 57 0.371 57.072 ;
     RECT  0.084 57.072 0.371 57.096 ;
     RECT  0.06 57.096 0.371 57.168 ;
     RECT  0.084 57.168 0.371 57.192 ;
     RECT  0.06 57.192 0.371 57.264 ;
     RECT  0.084 57.264 0.371 57.288 ;
     RECT  0.06 57.288 0.371 57.36 ;
     RECT  0.084 57.36 0.371 57.384 ;
     RECT  0.06 57.384 0.371 57.456 ;
     RECT  0.084 57.456 0.371 57.48 ;
     RECT  0.06 57.48 0.371 57.552 ;
     RECT  0.084 57.552 0.371 57.576 ;
     RECT  0.06 57.576 0.371 57.648 ;
     RECT  0.084 57.648 0.371 57.672 ;
     RECT  0.06 57.672 0.371 57.744 ;
     RECT  0.084 57.744 0.371 57.768 ;
     RECT  0.06 57.768 0.371 57.84 ;
     RECT  0.084 57.84 0.371 57.864 ;
     RECT  0.06 57.864 0.371 57.936 ;
     RECT  0.084 57.936 0.371 57.96 ;
     RECT  0.06 57.96 0.371 58.512 ;
     RECT  0.084 58.512 0.371 58.536 ;
     RECT  0.371 32.688 2.408 57.96 ;
     RECT  0.084 60.336 2.408 60.36 ;
     RECT  0.06 60.36 2.408 60.432 ;
     RECT  0.084 60.432 2.408 60.456 ;
     RECT  0.06 60.456 2.408 60.528 ;
     RECT  0.084 60.528 2.408 60.552 ;
     RECT  0.06 60.552 2.408 60.624 ;
     RECT  0.084 60.624 2.408 60.648 ;
     RECT  0.06 60.648 2.408 60.72 ;
     RECT  0.084 60.72 2.408 60.744 ;
     RECT  0.06 60.744 2.408 60.816 ;
     RECT  0.084 60.816 2.408 60.84 ;
     RECT  0.06 60.84 2.408 60.912 ;
     RECT  0.084 60.912 2.408 60.936 ;
     RECT  0.06 60.936 2.408 61.008 ;
     RECT  0.084 61.008 2.408 61.032 ;
     RECT  0.06 61.032 2.408 61.104 ;
     RECT  0.084 61.104 2.408 61.128 ;
     RECT  0.06 61.128 2.408 61.2 ;
     RECT  0.084 61.2 2.408 61.224 ;
     RECT  0.06 61.224 2.408 61.296 ;
     RECT  0.084 61.296 2.408 61.32 ;
     RECT  0.06 61.32 2.408 61.392 ;
     RECT  0.084 61.392 2.408 61.416 ;
     RECT  0.06 61.416 2.408 61.488 ;
     RECT  0.084 61.488 2.408 61.512 ;
     RECT  0.06 61.512 2.408 61.584 ;
     RECT  0.084 61.584 2.408 61.608 ;
     RECT  0.06 61.608 2.408 61.68 ;
     RECT  0.084 61.68 2.408 61.704 ;
     RECT  0.06 61.704 2.408 61.776 ;
     RECT  0.084 61.776 2.408 61.8 ;
     RECT  0.084 68.688 2.408 68.712 ;
     RECT  0.06 68.712 2.408 68.784 ;
     RECT  0.084 68.784 2.408 68.808 ;
     RECT  0.06 68.808 2.408 68.88 ;
     RECT  0.084 68.88 2.408 68.904 ;
     RECT  0.06 68.904 2.408 68.976 ;
     RECT  0.084 68.976 2.408 69 ;
     RECT  0.06 69 2.408 69.072 ;
     RECT  0.084 69.072 2.408 69.096 ;
     RECT  0.06 69.096 2.408 69.168 ;
     RECT  0.084 69.168 2.408 69.192 ;
     RECT  0.06 69.192 2.408 69.264 ;
     RECT  0.084 69.264 2.408 69.288 ;
     RECT  0.084 77.424 2.408 77.448 ;
     RECT  0.06 77.448 2.408 77.52 ;
     RECT  0.084 77.52 2.408 77.544 ;
     RECT  0.06 77.544 2.408 77.616 ;
     RECT  0.084 77.616 2.408 77.64 ;
     RECT  0.06 77.64 2.408 77.712 ;
     RECT  0.084 77.712 2.408 77.736 ;
     RECT  0.06 77.736 2.408 77.808 ;
     RECT  0.084 77.808 2.408 77.832 ;
     RECT  0.06 77.832 2.408 77.904 ;
     RECT  0.084 77.904 2.408 77.928 ;
     RECT  0.06 77.928 2.408 78 ;
     RECT  0.084 78 2.408 78.024 ;
     RECT  0.06 78.024 2.408 78.096 ;
     RECT  0.084 78.096 2.408 78.12 ;
     RECT  0.06 78.12 2.408 78.192 ;
     RECT  0.084 78.192 2.408 78.216 ;
     RECT  0.06 78.216 2.408 78.288 ;
     RECT  0.084 78.288 2.408 78.312 ;
     RECT  0.06 78.312 2.408 78.384 ;
     RECT  0.084 78.384 2.408 78.408 ;
     RECT  0.06 78.408 2.408 78.48 ;
     RECT  0.084 78.48 2.408 78.504 ;
     RECT  0.06 78.504 2.408 78.576 ;
     RECT  0.084 78.576 2.408 78.6 ;
     RECT  0.06 78.6 2.408 78.672 ;
     RECT  0.084 78.672 2.408 78.696 ;
     RECT  0.06 78.696 2.408 78.768 ;
     RECT  0.084 78.768 2.408 78.792 ;
     RECT  0.06 78.792 2.408 78.864 ;
     RECT  0.084 78.864 2.408 78.888 ;
     RECT  0.084 82.512 2.408 82.536 ;
     RECT  0.06 82.536 2.408 82.608 ;
     RECT  0.084 82.608 2.408 82.632 ;
     RECT  0.06 82.632 2.408 82.704 ;
     RECT  0.084 82.704 2.408 82.728 ;
     RECT  0.06 82.728 2.408 82.8 ;
     RECT  0.084 82.8 2.408 82.824 ;
     RECT  2.408 2.148 2.512 84.252 ;
     RECT  2.512 2.418 2.704 83.982 ;
     RECT  2.704 60.528 2.798 61.704 ;
     RECT  2.704 82.512 2.801 82.728 ;
     RECT  2.801 82.512 2.873 82.536 ;
     RECT  2.704 32.88 4.061 38.76 ;
     RECT  2.704 39.792 4.205 58.008 ;
     RECT  2.798 60.576 4.277 61.704 ;
     RECT  2.704 68.784 4.421 69.528 ;
     RECT  4.277 60.816 4.493 61.704 ;
     RECT  4.061 32.88 4.529 38.232 ;
     RECT  4.421 69.168 4.709 69.528 ;
     RECT  4.213 63.216 4.796 63.24 ;
     RECT  4.205 40.128 4.837 58.008 ;
     RECT  2.704 77.664 4.837 78.792 ;
     RECT  4.796 63.12 4.853 63.24 ;
     RECT  4.837 40.128 4.883 58.68 ;
     RECT  4.853 63.12 4.883 63.144 ;
     RECT  4.837 76.944 5.065 78.792 ;
     RECT  4.493 61.008 5.177 61.704 ;
     RECT  4.883 56.352 5.285 58.68 ;
     RECT  4.883 40.128 5.564 55.272 ;
     RECT  5.564 39.888 5.569 55.272 ;
     RECT  5.569 39.36 5.573 55.272 ;
     RECT  5.285 56.352 5.645 57.576 ;
     RECT  4.529 32.976 5.677 38.232 ;
     RECT  5.573 39.36 5.699 53.016 ;
     RECT  5.065 76.944 5.708 78.888 ;
     RECT  5.677 32.976 5.717 38.28 ;
     RECT  5.699 40.272 5.717 53.016 ;
     RECT  4.709 69.504 5.749 69.528 ;
     RECT  5.717 52.416 5.753 53.016 ;
     RECT  5.717 33.36 5.789 38.28 ;
     RECT  5.753 52.416 5.789 52.728 ;
     RECT  5.708 76.704 5.789 78.888 ;
     RECT  5.789 76.704 5.795 76.728 ;
     RECT  5.789 77.808 5.795 78.648 ;
     RECT  5.789 52.416 5.825 52.584 ;
     RECT  5.749 69.504 5.833 70.104 ;
     RECT  5.177 61.008 5.861 61.368 ;
     RECT  5.573 54.096 6.473 55.272 ;
     RECT  5.717 40.272 6.545 51.432 ;
     RECT  5.645 56.352 6.62 56.568 ;
     RECT  5.645 57.552 6.62 57.576 ;
     RECT  5.789 37.968 6.649 38.28 ;
     RECT  6.62 56.352 6.661 57.576 ;
     RECT  5.285 58.656 6.661 58.68 ;
     RECT  6.545 40.272 6.721 43.416 ;
     RECT  6.473 54.096 6.725 54.936 ;
     RECT  6.661 55.968 6.761 58.68 ;
     RECT  6.649 37.968 6.829 38.712 ;
     RECT  6.721 40.032 6.829 43.416 ;
     RECT  5.789 33.36 6.853 36.84 ;
     RECT  5.861 61.296 6.901 61.368 ;
     RECT  6.545 44.448 7.009 51.432 ;
     RECT  5.825 52.56 7.009 52.584 ;
     RECT  6.725 54.096 7.369 54.504 ;
     RECT  6.853 33.072 7.405 36.84 ;
     RECT  6.829 37.968 7.405 43.416 ;
     RECT  6.901 61.296 7.669 61.896 ;
     RECT  7.405 33.072 7.808 43.416 ;
     RECT  7.009 44.448 7.808 52.584 ;
     RECT  7.369 53.808 7.808 54.504 ;
     RECT  6.761 56.544 7.808 58.68 ;
     RECT  7.669 60.576 7.808 61.896 ;
     RECT  5.833 69.504 7.808 69.528 ;
     RECT  2.704 74.064 7.808 74.088 ;
     RECT  2.704 75.504 7.808 75.528 ;
     RECT  6.829 77.568 7.808 77.592 ;
     RECT  5.795 78.624 7.808 78.648 ;
     RECT  7.808 2.148 7.912 84.252 ;
     RECT  7.912 2.418 8.104 83.982 ;
     RECT  8.104 34.128 8.165 35.352 ;
     RECT  8.104 43.104 8.165 43.368 ;
     RECT  8.104 57.408 8.201 58.68 ;
     RECT  8.165 43.104 8.237 43.128 ;
     RECT  8.104 46.272 8.237 46.632 ;
     RECT  8.104 52.944 8.237 53.832 ;
     RECT  8.104 61.392 8.237 61.944 ;
     RECT  8.237 46.272 8.309 46.584 ;
     RECT  8.201 57.552 8.309 58.68 ;
     RECT  8.237 52.944 8.453 53.016 ;
     RECT  8.104 77.568 8.453 77.592 ;
     RECT  8.165 34.896 8.525 35.352 ;
     RECT  8.104 37.152 8.561 37.176 ;
     RECT  8.525 35.136 8.597 35.352 ;
     RECT  8.453 52.944 8.597 52.968 ;
     RECT  8.597 35.136 8.813 35.16 ;
     RECT  8.309 46.272 9.425 46.296 ;
     RECT  8.104 50.544 13.208 50.568 ;
     RECT  8.309 57.552 13.208 57.576 ;
     RECT  8.309 58.656 13.208 58.68 ;
     RECT  8.237 61.92 13.208 61.944 ;
     RECT  8.104 74.064 13.208 74.088 ;
     RECT  8.104 75.504 13.208 75.528 ;
     RECT  13.208 2.148 13.312 84.252 ;
     RECT  13.312 2.418 13.504 83.982 ;
     RECT  13.504 57.552 14.821 57.576 ;
     RECT  14.821 57.456 14.861 57.576 ;
     RECT  13.504 50.544 18.608 50.568 ;
     RECT  14.861 57.456 18.608 57.48 ;
     RECT  13.504 58.656 18.608 58.68 ;
     RECT  13.504 61.92 18.608 61.944 ;
     RECT  13.504 74.064 18.608 74.088 ;
     RECT  13.504 75.504 18.608 75.528 ;
     RECT  18.608 2.148 18.712 84.252 ;
     RECT  18.712 2.418 18.904 83.982 ;
     RECT  18.904 58.656 19.043 58.68 ;
     RECT  18.904 57.36 19.325 57.576 ;
     RECT  18.904 50.544 20.195 50.568 ;
     RECT  19.325 57.36 22.777 57.48 ;
     RECT  22.777 57.36 24.008 57.576 ;
     RECT  18.904 61.872 24.008 61.896 ;
     RECT  18.904 74.064 24.008 74.088 ;
     RECT  18.904 75.504 24.008 75.528 ;
     RECT  24.008 2.148 24.112 84.252 ;
     RECT  24.112 2.418 24.304 83.982 ;
     RECT  24.304 57.36 29.408 57.576 ;
     RECT  24.304 61.872 29.408 61.896 ;
     RECT  24.304 74.064 29.408 74.088 ;
     RECT  24.304 75.504 29.408 75.528 ;
     RECT  29.408 2.148 29.512 84.252 ;
     RECT  29.512 2.418 29.704 83.982 ;
     RECT  29.704 57.36 34.808 57.576 ;
     RECT  29.704 61.872 34.808 61.896 ;
     RECT  29.704 74.064 34.808 74.088 ;
     RECT  29.704 75.504 34.808 75.528 ;
     RECT  34.808 2.148 34.912 84.252 ;
     RECT  34.912 2.418 35.104 83.982 ;
     RECT  35.104 57.36 38.773 57.576 ;
     RECT  38.773 57.12 38.909 57.576 ;
     RECT  38.909 57.12 40.208 57.432 ;
     RECT  35.104 61.872 40.208 61.896 ;
     RECT  35.104 74.064 40.208 74.088 ;
     RECT  35.104 75.504 40.208 75.528 ;
     RECT  40.208 2.148 40.312 84.252 ;
     RECT  40.312 2.418 40.504 83.982 ;
     RECT  40.504 49.776 41.569 49.8 ;
     RECT  40.504 45.024 41.641 45.96 ;
     RECT  41.641 45.024 41.749 46.824 ;
     RECT  40.504 48.72 41.857 48.744 ;
     RECT  41.569 49.776 41.857 50.568 ;
     RECT  41.749 44.448 42.253 46.824 ;
     RECT  40.504 56.736 42.433 57.432 ;
     RECT  42.361 79.824 42.577 79.848 ;
     RECT  41.893 51.744 42.613 51.768 ;
     RECT  42.109 54.384 42.649 54.408 ;
     RECT  42.577 79.728 42.709 79.848 ;
     RECT  42.709 78.912 42.755 79.848 ;
     RECT  42.289 42 42.757 42.024 ;
     RECT  41.857 48.72 42.757 50.568 ;
     RECT  42.757 42 42.761 42.168 ;
     RECT  42.325 53.328 42.829 53.352 ;
     RECT  42.761 42.144 42.973 42.168 ;
     RECT  40.504 74.064 43.193 74.088 ;
     RECT  42.973 42.144 43.297 43.128 ;
     RECT  43.297 42.144 43.445 43.32 ;
     RECT  42.829 52.752 43.477 53.352 ;
     RECT  42.649 54.336 43.477 54.408 ;
     RECT  42.613 51.696 43.585 51.768 ;
     RECT  43.477 52.752 43.585 54.408 ;
     RECT  43.585 51.696 43.621 54.408 ;
     RECT  42.757 48.72 43.693 50.616 ;
     RECT  43.621 51.696 43.693 54.456 ;
     RECT  44.233 35.712 44.417 35.736 ;
     RECT  42.755 78.912 44.809 79.752 ;
     RECT  44.125 73.776 45.349 73.8 ;
     RECT  40.504 75.504 45.349 75.528 ;
     RECT  44.809 78.624 45.445 79.752 ;
     RECT  45.445 78.624 45.457 80.472 ;
     RECT  43.445 43.008 45.608 43.32 ;
     RECT  42.253 44.448 45.608 47.208 ;
     RECT  43.693 48.72 45.608 54.456 ;
     RECT  42.433 56.592 45.608 57.432 ;
     RECT  40.504 61.872 45.608 61.896 ;
     RECT  45.349 73.776 45.608 75.528 ;
     RECT  45.457 78.624 45.608 80.616 ;
     RECT  45.608 2.148 45.712 84.252 ;
     RECT  45.712 2.418 45.904 83.982 ;
     RECT  45.904 75.504 46.289 75.528 ;
     RECT  45.904 78.096 46.397 79.32 ;
     RECT  46.397 79.248 46.897 79.32 ;
     RECT  45.904 80.592 46.897 80.616 ;
     RECT  46.397 78.096 46.933 78.12 ;
     RECT  46.897 79.248 46.937 80.616 ;
     RECT  46.933 77.808 47.257 78.12 ;
     RECT  47.257 77.76 47.477 78.12 ;
     RECT  47.42 76.464 47.507 76.488 ;
     RECT  45.904 73.776 47.801 73.8 ;
     RECT  47.477 77.76 48.553 77.832 ;
     RECT  48.553 77.76 48.593 78.072 ;
     RECT  46.937 79.248 49.34 80.136 ;
     RECT  49.34 79.248 49.427 80.712 ;
     RECT  49.427 79.248 50.437 80.136 ;
     RECT  50.437 79.2 50.965 80.136 ;
     RECT  45.904 43.008 51.008 43.32 ;
     RECT  45.904 44.448 51.008 47.208 ;
     RECT  45.904 48.72 51.008 54.456 ;
     RECT  45.904 56.592 51.008 57.432 ;
     RECT  45.904 61.872 51.008 61.896 ;
     RECT  48.593 77.808 51.008 78.072 ;
     RECT  50.965 79.2 51.008 80.28 ;
     RECT  49.381 81.984 51.008 82.008 ;
     RECT  51.008 2.148 51.112 84.252 ;
     RECT  51.112 2.418 51.304 83.982 ;
     RECT  51.304 80.256 51.833 80.28 ;
     RECT  51.304 43.008 56.408 43.32 ;
     RECT  51.304 44.448 56.408 47.208 ;
     RECT  51.304 48.72 56.408 54.456 ;
     RECT  51.304 56.592 56.408 57.432 ;
     RECT  51.304 61.872 56.408 61.896 ;
     RECT  51.304 77.808 56.408 77.832 ;
     RECT  56.408 2.148 56.512 84.252 ;
     RECT  56.512 2.418 56.704 83.982 ;
     RECT  56.704 43.008 61.808 43.32 ;
     RECT  56.704 44.448 61.808 47.208 ;
     RECT  56.704 48.72 61.808 54.456 ;
     RECT  56.704 56.592 61.808 57.432 ;
     RECT  56.704 61.872 61.808 61.896 ;
     RECT  56.704 77.808 61.808 77.832 ;
     RECT  61.808 2.148 61.912 84.252 ;
     RECT  61.912 2.418 62.104 83.982 ;
     RECT  62.104 61.872 65.257 61.896 ;
     RECT  65.228 63.696 65.257 63.72 ;
     RECT  62.104 56.592 65.315 57.432 ;
     RECT  65.257 61.872 65.315 63.72 ;
     RECT  62.104 77.808 65.315 77.832 ;
     RECT  65.315 61.872 65.341 63.096 ;
     RECT  62.104 43.008 67.208 43.32 ;
     RECT  62.104 44.448 67.208 47.208 ;
     RECT  62.104 48.72 67.208 54.456 ;
     RECT  65.315 56.592 67.208 56.856 ;
     RECT  65.341 61.872 67.208 61.896 ;
     RECT  65.341 63.072 67.208 63.096 ;
     RECT  67.208 2.148 67.312 84.252 ;
     RECT  67.312 2.418 67.504 83.982 ;
     RECT  67.504 43.008 72.608 43.32 ;
     RECT  67.504 44.448 72.608 47.208 ;
     RECT  67.504 48.72 72.608 54.456 ;
     RECT  67.504 56.592 72.608 56.76 ;
     RECT  67.504 61.872 72.608 61.896 ;
     RECT  67.504 63.216 72.608 63.24 ;
     RECT  72.608 2.148 72.712 84.252 ;
     RECT  72.712 2.418 72.904 83.982 ;
     RECT  72.904 56.592 74.653 56.76 ;
     RECT  72.904 63.216 74.653 63.24 ;
     RECT  74.653 63.072 74.693 63.24 ;
     RECT  72.904 48.72 74.761 54.456 ;
     RECT  74.653 56.496 74.801 56.904 ;
     RECT  74.693 63.072 75.836 63.096 ;
     RECT  72.904 61.872 75.877 61.896 ;
     RECT  75.836 63.072 75.877 63.528 ;
     RECT  75.877 61.872 75.923 63.528 ;
     RECT  75.923 61.872 76.019 63.096 ;
     RECT  76.019 62.064 76.06 63.096 ;
     RECT  74.801 56.496 76.813 56.856 ;
     RECT  74.761 48.48 76.885 54.456 ;
     RECT  76.813 55.728 76.957 56.856 ;
     RECT  72.904 43.008 77.029 43.32 ;
     RECT  72.904 44.448 77.029 47.208 ;
     RECT  77.029 43.008 77.101 47.208 ;
     RECT  76.885 48.24 77.101 54.456 ;
     RECT  77.101 35.472 77.137 35.496 ;
     RECT  76.813 36.624 77.137 36.648 ;
     RECT  76.957 55.488 77.137 56.856 ;
     RECT  77.137 35.472 77.173 36.648 ;
     RECT  77.101 43.008 77.173 54.456 ;
     RECT  77.137 55.488 77.173 57 ;
     RECT  77.173 35.424 77.317 36.648 ;
     RECT  76.06 63.072 77.317 63.096 ;
     RECT  77.173 43.008 77.353 57 ;
     RECT  77.425 80.736 77.509 80.904 ;
     RECT  76.06 62.064 77.713 62.088 ;
     RECT  77.353 42.72 77.821 57 ;
     RECT  75.877 64.944 77.857 64.968 ;
     RECT  77.857 64.944 77.965 65.256 ;
     RECT  77.317 34.656 78.008 36.648 ;
     RECT  77.137 38.208 78.008 38.232 ;
     RECT  77.821 42.72 78.008 57.384 ;
     RECT  77.533 59.184 78.008 59.208 ;
     RECT  77.713 61.104 78.008 62.088 ;
     RECT  77.317 63.072 78.008 63.288 ;
     RECT  77.965 64.896 78.008 65.256 ;
     RECT  77.209 66.768 78.008 66.792 ;
     RECT  75.985 69.264 78.008 69.288 ;
     RECT  77.569 76.224 78.008 76.248 ;
     RECT  77.509 79.776 78.008 80.904 ;
     RECT  78.008 2.148 78.112 84.252 ;
     RECT  78.112 2.418 78.304 83.982 ;
     RECT  78.304 66.768 78.401 66.792 ;
     RECT  78.304 80.88 78.401 81.672 ;
     RECT  78.304 60.576 78.419 61.704 ;
     RECT  78.304 41.04 78.617 59.208 ;
     RECT  78.617 41.04 78.725 58.584 ;
     RECT  78.304 35.328 78.761 36.648 ;
     RECT  78.725 41.04 78.995 57.48 ;
     RECT  78.304 64.848 79.265 64.92 ;
     RECT  78.304 37.632 79.333 38.328 ;
     RECT  79.265 64.848 79.333 64.872 ;
     RECT  79.333 64.752 79.369 64.872 ;
     RECT  78.304 34.128 79.405 34.152 ;
     RECT  78.304 63.072 79.405 63.288 ;
     RECT  79.369 64.416 79.405 64.872 ;
     RECT  78.304 69.264 79.429 69.288 ;
     RECT  79.405 33.888 79.445 34.152 ;
     RECT  78.995 41.04 79.445 55.416 ;
     RECT  78.419 61.104 79.477 61.704 ;
     RECT  78.401 81.648 79.477 81.672 ;
     RECT  79.445 41.136 79.481 55.416 ;
     RECT  78.304 75.504 79.517 76.248 ;
     RECT  79.477 81.552 79.517 81.672 ;
     RECT  78.725 58.56 79.523 58.584 ;
     RECT  79.405 63.072 79.523 64.872 ;
     RECT  78.761 35.328 79.589 36.312 ;
     RECT  79.481 41.136 79.589 54.456 ;
     RECT  79.657 79.824 79.693 79.848 ;
     RECT  79.693 79.824 79.741 79.944 ;
     RECT  78.995 56.496 79.801 57.48 ;
     RECT  78.304 78.336 79.801 78.36 ;
     RECT  79.801 78.048 79.885 78.648 ;
     RECT  79.477 60.912 79.913 61.752 ;
     RECT  79.477 66.144 79.949 66.168 ;
     RECT  79.741 79.92 79.981 79.944 ;
     RECT  79.981 79.92 80.021 80.568 ;
     RECT  79.801 56.496 80.053 57.912 ;
     RECT  79.913 61.68 80.449 61.752 ;
     RECT  79.589 44.448 80.489 54.456 ;
     RECT  79.429 69.264 80.521 70.152 ;
     RECT  79.523 64.416 80.525 64.872 ;
     RECT  80.053 56.448 80.557 57.912 ;
     RECT  80.521 69.264 80.561 70.68 ;
     RECT  80.561 69.264 80.579 69.288 ;
     RECT  79.589 41.136 80.597 43.32 ;
     RECT  80.561 70.656 80.605 70.68 ;
     RECT  79.333 37.44 80.629 38.328 ;
     RECT  80.449 61.68 80.701 62.568 ;
     RECT  80.525 64.752 80.701 64.872 ;
     RECT  80.489 48.48 80.737 54.456 ;
     RECT  80.413 66.768 80.741 66.84 ;
     RECT  79.441 39.312 80.813 39.336 ;
     RECT  79.589 35.328 80.881 35.688 ;
     RECT  80.629 36.816 80.881 38.328 ;
     RECT  80.021 80.544 80.917 80.568 ;
     RECT  79.517 81.552 80.917 81.576 ;
     RECT  80.489 44.448 80.957 47.448 ;
     RECT  80.701 61.68 80.957 63.288 ;
     RECT  80.557 56.16 80.989 57.912 ;
     RECT  80.741 66.816 81.025 66.84 ;
     RECT  80.737 48.48 81.029 54.696 ;
     RECT  80.917 80.544 81.101 81.576 ;
     RECT  80.881 35.328 81.203 38.328 ;
     RECT  80.989 55.776 81.245 57.912 ;
     RECT  80.701 64.752 81.277 64.92 ;
     RECT  79.445 33.888 81.457 33.912 ;
     RECT  81.203 35.328 81.457 37.176 ;
     RECT  81.203 38.304 81.533 38.328 ;
     RECT  81.457 33.888 81.605 37.176 ;
     RECT  80.957 44.448 81.641 47.16 ;
     RECT  81.605 34.512 81.677 37.176 ;
     RECT  81.029 48.48 81.749 54.456 ;
     RECT  81.677 34.512 81.785 35.784 ;
     RECT  79.885 78.048 81.785 78.072 ;
     RECT  81.641 44.448 81.857 45.288 ;
     RECT  81.245 55.776 81.889 57.192 ;
     RECT  81.785 34.656 81.893 35.784 ;
     RECT  81.893 34.656 81.929 34.68 ;
     RECT  81.893 35.664 81.965 35.784 ;
     RECT  80.597 41.52 81.965 43.32 ;
     RECT  80.957 63.12 81.997 63.288 ;
     RECT  81.277 64.752 81.997 65.496 ;
     RECT  81.677 36.816 82.037 37.176 ;
     RECT  81.101 81.552 82.037 81.576 ;
     RECT  79.517 75.504 82.073 75.528 ;
     RECT  80.957 61.68 82.109 61.704 ;
     RECT  81.997 63.12 82.109 65.496 ;
     RECT  81.641 46.56 82.145 47.16 ;
     RECT  81.857 44.448 82.181 45 ;
     RECT  81.749 48.48 82.181 54.36 ;
     RECT  82.109 64.752 82.217 65.496 ;
     RECT  82.181 44.448 82.253 44.808 ;
     RECT  82.181 48.48 82.253 50.664 ;
     RECT  81.781 83.232 82.253 83.256 ;
     RECT  82.181 51.696 82.289 54.36 ;
     RECT  82.037 37.152 82.325 37.176 ;
     RECT  81.889 55.536 82.325 57.192 ;
     RECT  81.965 41.52 82.361 43.032 ;
     RECT  82.289 51.696 82.361 54.12 ;
     RECT  81.313 58.512 82.397 58.536 ;
     RECT  82.325 56.016 82.537 57.192 ;
     RECT  82.109 63.12 82.609 63.288 ;
     RECT  82.217 64.896 82.609 65.496 ;
     RECT  81.025 66.816 82.609 67.128 ;
     RECT  82.253 44.448 82.645 44.472 ;
     RECT  82.645 44.112 83.221 44.472 ;
     RECT  82.645 48.432 83.221 48.456 ;
     RECT  82.253 49.536 83.221 50.664 ;
     RECT  82.645 61.968 83.221 61.992 ;
     RECT  82.609 63.024 83.221 63.288 ;
     RECT  81.965 35.76 83.408 35.784 ;
     RECT  83.221 37.68 83.408 37.704 ;
     RECT  82.645 38.976 83.408 39 ;
     RECT  82.361 41.52 83.408 41.544 ;
     RECT  83.221 44.112 83.408 45 ;
     RECT  82.145 46.56 83.408 47.064 ;
     RECT  83.221 48.432 83.408 50.664 ;
     RECT  82.361 51.696 83.408 53.064 ;
     RECT  82.361 54.096 83.408 54.12 ;
     RECT  82.537 56.016 83.408 58.152 ;
     RECT  83.221 61.968 83.408 63.288 ;
     RECT  82.609 64.896 83.408 67.128 ;
     RECT  83.408 2.148 83.512 84.252 ;
     RECT  83.512 2.418 83.704 83.982 ;
     RECT  83.704 61.488 84.733 63.72 ;
     RECT  83.704 43.632 84.769 58.152 ;
     RECT  83.704 64.752 84.805 65.976 ;
     RECT  83.704 34.032 84.841 38.952 ;
     RECT  84.841 33.744 84.877 38.952 ;
     RECT  83.704 40.56 84.877 42.6 ;
     RECT  84.769 43.632 84.877 58.488 ;
     RECT  84.733 61.392 84.877 63.72 ;
     RECT  84.805 64.752 84.877 66.312 ;
     RECT  83.704 80.688 84.877 81.96 ;
     RECT  84.877 40.56 84.913 58.488 ;
     RECT  84.877 61.392 84.913 66.312 ;
     RECT  84.913 40.464 85.381 58.488 ;
     RECT  84.913 60.528 85.381 66.312 ;
     RECT  84.877 33.648 85.453 39.432 ;
     RECT  85.381 40.464 85.453 58.536 ;
     RECT  83.704 78.192 85.453 78.216 ;
     RECT  84.877 79.536 85.453 79.56 ;
     RECT  84.877 80.592 85.453 81.96 ;
     RECT  85.453 78.192 85.489 78.312 ;
     RECT  85.453 33.552 86.173 58.536 ;
     RECT  85.381 60.528 86.209 66.408 ;
     RECT  86.173 33.552 86.316 33.576 ;
     RECT  86.173 33.576 86.364 33.648 ;
     RECT  86.173 33.648 86.316 33.672 ;
     RECT  86.173 33.672 86.364 33.744 ;
     RECT  86.173 33.744 86.316 33.768 ;
     RECT  86.173 33.768 86.364 33.84 ;
     RECT  86.173 33.84 86.316 33.864 ;
     RECT  86.173 33.864 86.364 33.936 ;
     RECT  86.173 33.936 86.316 33.96 ;
     RECT  86.173 33.96 86.364 34.032 ;
     RECT  86.173 34.032 86.316 34.056 ;
     RECT  86.173 34.056 86.364 34.128 ;
     RECT  86.173 34.128 86.316 34.152 ;
     RECT  86.173 34.152 86.364 34.224 ;
     RECT  86.173 34.224 86.316 34.248 ;
     RECT  86.173 34.248 86.364 34.32 ;
     RECT  86.173 34.32 86.316 34.344 ;
     RECT  86.173 34.344 86.364 34.416 ;
     RECT  86.173 34.416 86.316 34.44 ;
     RECT  86.173 34.44 86.364 34.512 ;
     RECT  86.173 34.512 86.316 34.536 ;
     RECT  86.173 34.536 86.364 34.608 ;
     RECT  86.173 34.608 86.316 34.632 ;
     RECT  86.173 34.632 86.364 34.704 ;
     RECT  86.173 34.704 86.316 34.728 ;
     RECT  86.173 34.728 86.364 34.8 ;
     RECT  86.173 34.8 86.316 34.824 ;
     RECT  86.173 34.824 86.364 34.896 ;
     RECT  86.173 34.896 86.316 34.92 ;
     RECT  86.173 34.92 86.364 34.992 ;
     RECT  86.173 34.992 86.316 35.016 ;
     RECT  86.173 35.016 86.364 35.088 ;
     RECT  86.173 35.088 86.316 35.112 ;
     RECT  86.173 35.112 86.364 35.184 ;
     RECT  86.173 35.184 86.316 35.208 ;
     RECT  86.173 35.208 86.364 35.28 ;
     RECT  86.173 35.28 86.316 35.304 ;
     RECT  86.173 35.304 86.364 35.376 ;
     RECT  86.173 35.376 86.316 35.4 ;
     RECT  86.173 35.4 86.364 35.472 ;
     RECT  86.173 35.472 86.316 35.496 ;
     RECT  86.173 35.496 86.364 35.568 ;
     RECT  86.173 35.568 86.316 35.592 ;
     RECT  86.173 35.592 86.364 35.664 ;
     RECT  86.173 35.664 86.316 35.688 ;
     RECT  86.173 35.688 86.364 35.76 ;
     RECT  86.173 35.76 86.316 35.784 ;
     RECT  86.173 35.784 86.364 35.856 ;
     RECT  86.173 35.856 86.316 35.88 ;
     RECT  86.173 35.88 86.364 35.952 ;
     RECT  86.173 35.952 86.316 35.976 ;
     RECT  86.173 35.976 86.364 36.048 ;
     RECT  86.173 36.048 86.316 36.072 ;
     RECT  86.173 36.072 86.364 36.144 ;
     RECT  86.173 36.144 86.316 36.168 ;
     RECT  86.173 36.168 86.364 36.24 ;
     RECT  86.173 36.24 86.316 36.264 ;
     RECT  86.173 36.264 86.364 36.336 ;
     RECT  86.173 36.336 86.316 36.36 ;
     RECT  86.173 36.36 86.364 36.432 ;
     RECT  86.173 36.432 86.316 36.456 ;
     RECT  86.173 36.456 86.364 36.528 ;
     RECT  86.173 36.528 86.316 36.552 ;
     RECT  86.173 36.552 86.364 36.624 ;
     RECT  86.173 36.624 86.316 36.648 ;
     RECT  86.173 36.648 86.364 36.72 ;
     RECT  86.173 36.72 86.316 36.744 ;
     RECT  86.173 36.744 86.364 36.816 ;
     RECT  86.173 36.816 86.316 36.84 ;
     RECT  86.173 36.84 86.364 36.912 ;
     RECT  86.173 36.912 86.316 36.936 ;
     RECT  86.173 36.936 86.364 37.008 ;
     RECT  86.173 37.008 86.316 37.032 ;
     RECT  86.173 37.032 86.364 37.104 ;
     RECT  86.173 37.104 86.316 37.128 ;
     RECT  86.173 37.128 86.364 37.2 ;
     RECT  86.173 37.2 86.316 37.224 ;
     RECT  86.173 37.224 86.364 37.296 ;
     RECT  86.173 37.296 86.316 37.32 ;
     RECT  86.173 37.32 86.364 37.392 ;
     RECT  86.173 37.392 86.316 37.416 ;
     RECT  86.173 37.416 86.364 37.488 ;
     RECT  86.173 37.488 86.316 37.512 ;
     RECT  86.173 37.512 86.364 37.584 ;
     RECT  86.173 37.584 86.316 37.608 ;
     RECT  86.173 37.608 86.364 37.68 ;
     RECT  86.173 37.68 86.316 37.704 ;
     RECT  86.173 37.704 86.364 37.776 ;
     RECT  86.173 37.776 86.316 37.8 ;
     RECT  86.173 37.8 86.364 37.872 ;
     RECT  86.173 37.872 86.316 37.896 ;
     RECT  86.173 37.896 86.364 37.968 ;
     RECT  86.173 37.968 86.316 37.992 ;
     RECT  86.173 37.992 86.364 38.064 ;
     RECT  86.173 38.064 86.316 38.088 ;
     RECT  86.173 38.088 86.364 38.16 ;
     RECT  86.173 38.16 86.316 38.184 ;
     RECT  86.173 38.184 86.364 38.256 ;
     RECT  86.173 38.256 86.316 38.28 ;
     RECT  86.173 38.28 86.364 38.352 ;
     RECT  86.173 38.352 86.316 38.376 ;
     RECT  86.173 38.376 86.364 38.448 ;
     RECT  86.173 38.448 86.316 38.472 ;
     RECT  86.173 38.472 86.364 38.544 ;
     RECT  86.173 38.544 86.316 38.568 ;
     RECT  86.173 38.568 86.364 38.64 ;
     RECT  86.173 38.64 86.316 38.664 ;
     RECT  86.173 38.664 86.364 38.736 ;
     RECT  86.173 38.736 86.316 38.76 ;
     RECT  86.173 38.76 86.364 38.832 ;
     RECT  86.173 38.832 86.316 38.856 ;
     RECT  86.173 38.856 86.364 38.928 ;
     RECT  86.173 38.928 86.316 38.952 ;
     RECT  86.173 38.952 86.364 39.024 ;
     RECT  86.173 39.024 86.316 39.048 ;
     RECT  86.173 39.048 86.364 39.12 ;
     RECT  86.173 39.12 86.316 39.144 ;
     RECT  86.173 39.144 86.364 39.216 ;
     RECT  86.173 39.216 86.316 39.24 ;
     RECT  86.173 39.24 86.364 39.312 ;
     RECT  86.173 39.312 86.316 39.336 ;
     RECT  86.173 39.336 86.364 39.408 ;
     RECT  86.173 39.408 86.316 39.432 ;
     RECT  86.173 39.432 86.364 39.504 ;
     RECT  86.173 39.504 86.316 39.528 ;
     RECT  86.173 39.528 86.364 39.6 ;
     RECT  86.173 39.6 86.316 39.624 ;
     RECT  86.173 39.624 86.364 40.464 ;
     RECT  86.173 40.464 86.316 40.488 ;
     RECT  86.173 40.488 86.364 40.56 ;
     RECT  86.173 40.56 86.316 40.584 ;
     RECT  86.173 40.584 86.364 40.656 ;
     RECT  86.173 40.656 86.316 40.68 ;
     RECT  86.173 40.68 86.364 40.752 ;
     RECT  86.173 40.752 86.316 40.776 ;
     RECT  86.173 40.776 86.364 40.848 ;
     RECT  86.173 40.848 86.316 40.872 ;
     RECT  86.173 40.872 86.364 40.944 ;
     RECT  86.173 40.944 86.316 40.968 ;
     RECT  86.173 40.968 86.364 41.04 ;
     RECT  86.173 41.04 86.316 41.064 ;
     RECT  86.173 41.064 86.364 41.136 ;
     RECT  86.173 41.136 86.316 41.16 ;
     RECT  86.173 41.16 86.364 41.232 ;
     RECT  86.173 41.232 86.316 41.256 ;
     RECT  86.173 41.256 86.364 41.328 ;
     RECT  86.173 41.328 86.316 41.352 ;
     RECT  86.173 41.352 86.364 41.424 ;
     RECT  86.173 41.424 86.316 41.448 ;
     RECT  86.173 41.448 86.364 41.52 ;
     RECT  86.173 41.52 86.316 41.544 ;
     RECT  86.173 41.544 86.364 41.616 ;
     RECT  86.173 41.616 86.316 41.64 ;
     RECT  86.173 41.64 86.364 41.712 ;
     RECT  86.173 41.712 86.316 41.736 ;
     RECT  86.173 41.736 86.364 41.808 ;
     RECT  86.173 41.808 86.316 41.832 ;
     RECT  86.173 41.832 86.364 41.904 ;
     RECT  86.173 41.904 86.316 41.928 ;
     RECT  86.173 41.928 86.364 42 ;
     RECT  86.173 42 86.316 42.024 ;
     RECT  86.173 42.024 86.364 42.096 ;
     RECT  86.173 42.096 86.316 42.12 ;
     RECT  86.173 42.12 86.364 42.192 ;
     RECT  86.173 42.192 86.316 42.216 ;
     RECT  86.173 42.216 86.364 42.288 ;
     RECT  86.173 42.288 86.316 42.312 ;
     RECT  86.173 42.312 86.364 42.384 ;
     RECT  86.173 42.384 86.316 42.408 ;
     RECT  86.173 42.408 86.364 42.48 ;
     RECT  86.173 42.48 86.316 42.504 ;
     RECT  86.173 42.504 86.364 42.576 ;
     RECT  86.173 42.576 86.316 42.6 ;
     RECT  86.173 42.6 86.364 42.672 ;
     RECT  86.173 42.672 86.316 42.696 ;
     RECT  86.173 42.696 86.364 42.768 ;
     RECT  86.173 42.768 86.316 42.792 ;
     RECT  86.173 42.792 86.364 42.864 ;
     RECT  86.173 42.864 86.316 42.888 ;
     RECT  86.173 42.888 86.364 42.96 ;
     RECT  86.173 42.96 86.316 42.984 ;
     RECT  86.173 42.984 86.364 43.056 ;
     RECT  86.173 43.056 86.316 43.08 ;
     RECT  86.173 43.08 86.364 43.152 ;
     RECT  86.173 43.152 86.316 43.176 ;
     RECT  86.173 43.176 86.364 43.248 ;
     RECT  86.173 43.248 86.316 43.272 ;
     RECT  86.173 43.272 86.364 43.344 ;
     RECT  86.173 43.344 86.316 43.368 ;
     RECT  86.173 43.368 86.364 43.44 ;
     RECT  86.173 43.44 86.316 43.464 ;
     RECT  86.173 43.464 86.364 43.536 ;
     RECT  86.173 43.536 86.316 43.56 ;
     RECT  86.173 43.56 86.364 43.632 ;
     RECT  86.173 43.632 86.316 43.656 ;
     RECT  86.173 43.656 86.364 43.728 ;
     RECT  86.173 43.728 86.316 43.752 ;
     RECT  86.173 43.752 86.364 43.824 ;
     RECT  86.173 43.824 86.316 43.848 ;
     RECT  86.173 43.848 86.364 43.92 ;
     RECT  86.173 43.92 86.316 43.944 ;
     RECT  86.173 43.944 86.364 44.016 ;
     RECT  86.173 44.016 86.316 44.04 ;
     RECT  86.173 44.04 86.364 44.112 ;
     RECT  86.173 44.112 86.316 44.136 ;
     RECT  86.173 44.136 86.364 44.208 ;
     RECT  86.173 44.208 86.316 44.232 ;
     RECT  86.173 44.232 86.364 44.304 ;
     RECT  86.173 44.304 86.316 44.328 ;
     RECT  86.173 44.328 86.364 44.4 ;
     RECT  86.173 44.4 86.316 44.424 ;
     RECT  86.173 44.424 86.364 44.496 ;
     RECT  86.173 44.496 86.316 44.52 ;
     RECT  86.173 44.52 86.364 44.592 ;
     RECT  86.173 44.592 86.316 44.616 ;
     RECT  86.173 44.616 86.364 44.688 ;
     RECT  86.173 44.688 86.316 44.712 ;
     RECT  86.173 44.712 86.364 44.784 ;
     RECT  86.173 44.784 86.316 44.808 ;
     RECT  86.173 44.808 86.364 44.88 ;
     RECT  86.173 44.88 86.316 44.904 ;
     RECT  86.173 44.904 86.364 44.976 ;
     RECT  86.173 44.976 86.316 45 ;
     RECT  86.173 45 86.364 45.072 ;
     RECT  86.173 45.072 86.316 45.096 ;
     RECT  86.173 45.096 86.364 45.168 ;
     RECT  86.173 45.168 86.316 45.192 ;
     RECT  86.173 45.192 86.364 45.264 ;
     RECT  86.173 45.264 86.316 45.288 ;
     RECT  86.173 45.288 86.364 45.36 ;
     RECT  86.173 45.36 86.316 45.384 ;
     RECT  86.173 45.384 86.364 45.456 ;
     RECT  86.173 45.456 86.316 45.48 ;
     RECT  86.173 45.48 86.364 45.552 ;
     RECT  86.173 45.552 86.316 45.576 ;
     RECT  86.173 45.576 86.364 45.648 ;
     RECT  86.173 45.648 86.316 45.672 ;
     RECT  86.173 45.672 86.364 45.744 ;
     RECT  86.173 45.744 86.316 45.768 ;
     RECT  86.173 45.768 86.364 45.84 ;
     RECT  86.173 45.84 86.316 45.864 ;
     RECT  86.173 45.864 86.364 45.936 ;
     RECT  86.173 45.936 86.316 45.96 ;
     RECT  86.173 45.96 86.364 46.032 ;
     RECT  86.173 46.032 86.316 46.056 ;
     RECT  86.173 46.056 86.364 46.128 ;
     RECT  86.173 46.128 86.316 46.152 ;
     RECT  86.173 46.152 86.364 46.224 ;
     RECT  86.173 46.224 86.316 46.248 ;
     RECT  86.173 46.248 86.364 46.32 ;
     RECT  86.173 46.32 86.316 46.344 ;
     RECT  86.173 46.344 86.364 46.416 ;
     RECT  86.173 46.416 86.316 46.44 ;
     RECT  86.173 46.44 86.364 46.512 ;
     RECT  86.173 46.512 86.316 46.536 ;
     RECT  86.173 46.536 86.364 46.608 ;
     RECT  86.173 46.608 86.316 46.632 ;
     RECT  86.173 46.632 86.364 46.704 ;
     RECT  86.173 46.704 86.316 46.728 ;
     RECT  86.173 46.728 86.364 46.8 ;
     RECT  86.173 46.8 86.316 46.824 ;
     RECT  86.173 46.824 86.364 46.896 ;
     RECT  86.173 46.896 86.316 46.92 ;
     RECT  86.173 46.92 86.364 46.992 ;
     RECT  86.173 46.992 86.316 47.016 ;
     RECT  86.173 47.016 86.364 47.088 ;
     RECT  86.173 47.088 86.316 47.112 ;
     RECT  86.173 47.112 86.364 47.184 ;
     RECT  86.173 47.184 86.316 47.208 ;
     RECT  86.173 47.208 86.364 47.28 ;
     RECT  86.173 47.28 86.316 47.304 ;
     RECT  86.173 47.304 86.364 47.376 ;
     RECT  86.173 47.376 86.316 47.4 ;
     RECT  86.173 47.4 86.364 47.472 ;
     RECT  86.173 47.472 86.316 47.496 ;
     RECT  86.173 47.496 86.364 47.568 ;
     RECT  86.173 47.568 86.316 47.592 ;
     RECT  86.173 47.592 86.364 47.664 ;
     RECT  86.173 47.664 86.316 47.688 ;
     RECT  86.173 47.688 86.364 47.76 ;
     RECT  86.173 47.76 86.316 47.784 ;
     RECT  86.173 47.784 86.364 47.856 ;
     RECT  86.173 47.856 86.316 47.88 ;
     RECT  86.173 47.88 86.364 47.952 ;
     RECT  86.173 47.952 86.316 47.976 ;
     RECT  86.173 47.976 86.364 48.048 ;
     RECT  86.173 48.048 86.316 48.072 ;
     RECT  86.173 48.072 86.364 48.144 ;
     RECT  86.173 48.144 86.316 48.168 ;
     RECT  86.173 48.168 86.364 48.24 ;
     RECT  86.173 48.24 86.316 48.264 ;
     RECT  86.173 48.264 86.364 48.336 ;
     RECT  86.173 48.336 86.316 48.36 ;
     RECT  86.173 48.36 86.364 48.432 ;
     RECT  86.173 48.432 86.316 48.456 ;
     RECT  86.173 48.456 86.364 48.528 ;
     RECT  86.173 48.528 86.316 48.552 ;
     RECT  86.173 48.552 86.364 48.624 ;
     RECT  86.173 48.624 86.316 48.648 ;
     RECT  86.173 48.648 86.364 48.72 ;
     RECT  86.173 48.72 86.316 48.744 ;
     RECT  86.173 48.744 86.364 48.816 ;
     RECT  86.173 48.816 86.316 48.84 ;
     RECT  86.173 48.84 86.364 48.912 ;
     RECT  86.173 48.912 86.316 48.936 ;
     RECT  86.173 48.936 86.364 49.008 ;
     RECT  86.173 49.008 86.316 49.032 ;
     RECT  86.173 49.032 86.364 49.104 ;
     RECT  86.173 49.104 86.316 49.128 ;
     RECT  86.173 49.128 86.364 49.2 ;
     RECT  86.173 49.2 86.316 49.224 ;
     RECT  86.173 49.224 86.364 49.296 ;
     RECT  86.173 49.296 86.316 49.32 ;
     RECT  86.173 49.32 86.364 49.392 ;
     RECT  86.173 49.392 86.316 49.416 ;
     RECT  86.173 49.416 86.364 49.488 ;
     RECT  86.173 49.488 86.316 49.512 ;
     RECT  86.173 49.512 86.364 49.584 ;
     RECT  86.173 49.584 86.316 49.608 ;
     RECT  86.173 49.608 86.364 49.68 ;
     RECT  86.173 49.68 86.316 49.704 ;
     RECT  86.173 49.704 86.364 49.776 ;
     RECT  86.173 49.776 86.316 49.8 ;
     RECT  86.173 49.8 86.364 49.872 ;
     RECT  86.173 49.872 86.316 49.896 ;
     RECT  86.173 49.896 86.364 49.968 ;
     RECT  86.173 49.968 86.316 49.992 ;
     RECT  86.173 49.992 86.364 50.064 ;
     RECT  86.173 50.064 86.316 50.088 ;
     RECT  86.173 50.088 86.364 50.16 ;
     RECT  86.173 50.16 86.316 50.184 ;
     RECT  86.173 50.184 86.364 50.256 ;
     RECT  86.173 50.256 86.316 50.28 ;
     RECT  86.173 50.28 86.364 50.352 ;
     RECT  86.173 50.352 86.316 50.376 ;
     RECT  86.173 50.376 86.364 50.448 ;
     RECT  86.173 50.448 86.316 50.472 ;
     RECT  86.173 50.472 86.364 50.544 ;
     RECT  86.173 50.544 86.316 50.568 ;
     RECT  86.173 50.568 86.364 50.64 ;
     RECT  86.173 50.64 86.316 50.664 ;
     RECT  86.173 50.664 86.364 50.736 ;
     RECT  86.173 50.736 86.316 50.76 ;
     RECT  86.173 50.76 86.364 50.832 ;
     RECT  86.173 50.832 86.316 50.856 ;
     RECT  86.173 50.856 86.364 50.928 ;
     RECT  86.173 50.928 86.316 50.952 ;
     RECT  86.173 50.952 86.364 51.024 ;
     RECT  86.173 51.024 86.316 51.048 ;
     RECT  86.173 51.048 86.364 51.12 ;
     RECT  86.173 51.12 86.316 51.144 ;
     RECT  86.173 51.144 86.364 51.216 ;
     RECT  86.173 51.216 86.316 51.24 ;
     RECT  86.173 51.24 86.364 51.312 ;
     RECT  86.173 51.312 86.316 51.336 ;
     RECT  86.173 51.336 86.364 51.408 ;
     RECT  86.173 51.408 86.316 51.432 ;
     RECT  86.173 51.432 86.364 51.504 ;
     RECT  86.173 51.504 86.316 51.528 ;
     RECT  86.173 51.528 86.364 51.6 ;
     RECT  86.173 51.6 86.316 51.624 ;
     RECT  86.173 51.624 86.364 51.696 ;
     RECT  86.173 51.696 86.316 51.72 ;
     RECT  86.173 51.72 86.364 51.792 ;
     RECT  86.173 51.792 86.316 51.816 ;
     RECT  86.173 51.816 86.364 51.888 ;
     RECT  86.173 51.888 86.316 51.912 ;
     RECT  86.173 51.912 86.364 51.984 ;
     RECT  86.173 51.984 86.316 52.008 ;
     RECT  86.173 52.008 86.364 52.08 ;
     RECT  86.173 52.08 86.316 52.104 ;
     RECT  86.173 52.104 86.364 52.176 ;
     RECT  86.173 52.176 86.316 52.2 ;
     RECT  86.173 52.2 86.364 52.272 ;
     RECT  86.173 52.272 86.316 52.296 ;
     RECT  86.173 52.296 86.364 52.368 ;
     RECT  86.173 52.368 86.316 52.392 ;
     RECT  86.173 52.392 86.364 52.464 ;
     RECT  86.173 52.464 86.316 52.488 ;
     RECT  86.173 52.488 86.364 52.56 ;
     RECT  86.173 52.56 86.316 52.584 ;
     RECT  86.173 52.584 86.364 52.656 ;
     RECT  86.173 52.656 86.316 52.68 ;
     RECT  86.173 52.68 86.364 52.752 ;
     RECT  86.173 52.752 86.316 52.776 ;
     RECT  86.173 52.776 86.364 52.848 ;
     RECT  86.173 52.848 86.316 52.872 ;
     RECT  86.173 52.872 86.364 52.944 ;
     RECT  86.173 52.944 86.316 52.968 ;
     RECT  86.173 52.968 86.364 53.04 ;
     RECT  86.173 53.04 86.316 53.064 ;
     RECT  86.173 53.064 86.364 53.136 ;
     RECT  86.173 53.136 86.316 53.16 ;
     RECT  86.173 53.16 86.364 53.232 ;
     RECT  86.173 53.232 86.316 53.256 ;
     RECT  86.173 53.256 86.364 53.328 ;
     RECT  86.173 53.328 86.316 53.352 ;
     RECT  86.173 53.352 86.364 53.424 ;
     RECT  86.173 53.424 86.316 53.448 ;
     RECT  86.173 53.448 86.364 53.52 ;
     RECT  86.173 53.52 86.316 53.544 ;
     RECT  86.173 53.544 86.364 53.616 ;
     RECT  86.173 53.616 86.316 53.64 ;
     RECT  86.173 53.64 86.364 53.712 ;
     RECT  86.173 53.712 86.316 53.736 ;
     RECT  86.173 53.736 86.364 53.808 ;
     RECT  86.173 53.808 86.316 53.832 ;
     RECT  86.173 53.832 86.364 53.904 ;
     RECT  86.173 53.904 86.316 53.928 ;
     RECT  86.173 53.928 86.364 54 ;
     RECT  86.173 54 86.316 54.024 ;
     RECT  86.173 54.024 86.364 54.096 ;
     RECT  86.173 54.096 86.316 54.12 ;
     RECT  86.173 54.12 86.364 54.192 ;
     RECT  86.173 54.192 86.316 54.216 ;
     RECT  86.173 54.216 86.364 54.288 ;
     RECT  86.173 54.288 86.316 54.312 ;
     RECT  86.173 54.312 86.364 54.384 ;
     RECT  86.173 54.384 86.316 54.408 ;
     RECT  86.173 54.408 86.364 54.48 ;
     RECT  86.173 54.48 86.316 54.504 ;
     RECT  86.173 54.504 86.364 54.576 ;
     RECT  86.173 54.576 86.316 54.6 ;
     RECT  86.173 54.6 86.364 54.672 ;
     RECT  86.173 54.672 86.316 54.696 ;
     RECT  86.173 54.696 86.364 54.768 ;
     RECT  86.173 54.768 86.316 54.792 ;
     RECT  86.173 54.792 86.364 54.864 ;
     RECT  86.173 54.864 86.316 54.888 ;
     RECT  86.173 54.888 86.364 54.96 ;
     RECT  86.173 54.96 86.316 54.984 ;
     RECT  86.173 54.984 86.364 55.056 ;
     RECT  86.173 55.056 86.316 55.08 ;
     RECT  86.173 55.08 86.364 55.152 ;
     RECT  86.173 55.152 86.316 55.176 ;
     RECT  86.173 55.176 86.364 55.248 ;
     RECT  86.173 55.248 86.316 55.272 ;
     RECT  86.173 55.272 86.364 55.344 ;
     RECT  86.173 55.344 86.316 55.368 ;
     RECT  86.173 55.368 86.364 55.44 ;
     RECT  86.173 55.44 86.316 55.464 ;
     RECT  86.173 55.464 86.364 55.536 ;
     RECT  86.173 55.536 86.316 55.56 ;
     RECT  86.173 55.56 86.364 55.632 ;
     RECT  86.173 55.632 86.316 55.656 ;
     RECT  86.173 55.656 86.364 55.728 ;
     RECT  86.173 55.728 86.316 55.752 ;
     RECT  86.173 55.752 86.364 55.824 ;
     RECT  86.173 55.824 86.316 55.848 ;
     RECT  86.173 55.848 86.364 55.92 ;
     RECT  86.173 55.92 86.316 55.944 ;
     RECT  86.173 55.944 86.364 56.016 ;
     RECT  86.173 56.016 86.316 56.04 ;
     RECT  86.173 56.04 86.364 56.112 ;
     RECT  86.173 56.112 86.316 56.136 ;
     RECT  86.173 56.136 86.364 56.208 ;
     RECT  86.173 56.208 86.316 56.232 ;
     RECT  86.173 56.232 86.364 56.304 ;
     RECT  86.173 56.304 86.316 56.328 ;
     RECT  86.173 56.328 86.364 56.4 ;
     RECT  86.173 56.4 86.316 56.424 ;
     RECT  86.173 56.424 86.364 56.496 ;
     RECT  86.173 56.496 86.316 56.52 ;
     RECT  86.173 56.52 86.364 56.592 ;
     RECT  86.173 56.592 86.316 56.616 ;
     RECT  86.173 56.616 86.364 56.688 ;
     RECT  86.173 56.688 86.316 56.712 ;
     RECT  86.173 56.712 86.364 56.784 ;
     RECT  86.173 56.784 86.316 56.808 ;
     RECT  86.173 56.808 86.364 56.88 ;
     RECT  86.173 56.88 86.316 56.904 ;
     RECT  86.173 56.904 86.364 56.976 ;
     RECT  86.173 56.976 86.316 57 ;
     RECT  86.173 57 86.364 57.072 ;
     RECT  86.173 57.072 86.316 57.096 ;
     RECT  86.173 57.096 86.364 57.168 ;
     RECT  86.173 57.168 86.316 57.192 ;
     RECT  86.173 57.192 86.364 57.264 ;
     RECT  86.173 57.264 86.316 57.288 ;
     RECT  86.173 57.288 86.364 57.36 ;
     RECT  86.173 57.36 86.316 57.384 ;
     RECT  86.173 57.384 86.364 57.456 ;
     RECT  86.173 57.456 86.316 57.48 ;
     RECT  86.173 57.48 86.364 57.552 ;
     RECT  86.173 57.552 86.316 57.576 ;
     RECT  86.173 57.576 86.364 57.648 ;
     RECT  86.173 57.648 86.316 57.672 ;
     RECT  86.173 57.672 86.364 57.744 ;
     RECT  86.173 57.744 86.316 57.768 ;
     RECT  86.173 57.768 86.364 57.84 ;
     RECT  86.173 57.84 86.316 57.864 ;
     RECT  86.173 57.864 86.364 57.936 ;
     RECT  86.173 57.936 86.316 57.96 ;
     RECT  86.173 57.96 86.364 58.032 ;
     RECT  86.173 58.032 86.316 58.056 ;
     RECT  86.173 58.056 86.364 58.128 ;
     RECT  86.173 58.128 86.316 58.152 ;
     RECT  86.173 58.152 86.364 58.224 ;
     RECT  86.173 58.224 86.316 58.248 ;
     RECT  86.173 58.248 86.364 58.32 ;
     RECT  86.173 58.32 86.316 58.344 ;
     RECT  86.173 58.344 86.364 58.416 ;
     RECT  86.173 58.416 86.316 58.44 ;
     RECT  86.173 58.44 86.364 58.512 ;
     RECT  86.173 58.512 86.316 58.536 ;
     RECT  86.173 58.536 86.364 58.608 ;
     RECT  86.173 58.608 86.316 58.632 ;
     RECT  86.173 58.632 86.364 58.704 ;
     RECT  86.173 58.704 86.316 58.728 ;
     RECT  86.173 58.728 86.364 58.8 ;
     RECT  86.173 58.8 86.316 58.824 ;
     RECT  86.209 60.528 86.316 60.552 ;
     RECT  86.209 60.552 86.364 60.624 ;
     RECT  86.209 60.624 86.316 60.648 ;
     RECT  86.209 60.648 86.364 60.72 ;
     RECT  86.209 60.72 86.316 60.744 ;
     RECT  86.209 60.744 86.364 60.816 ;
     RECT  86.209 60.816 86.316 60.84 ;
     RECT  86.209 60.84 86.364 60.912 ;
     RECT  86.209 60.912 86.316 60.936 ;
     RECT  86.209 60.936 86.364 61.008 ;
     RECT  86.209 61.008 86.316 61.032 ;
     RECT  86.209 61.032 86.364 61.104 ;
     RECT  86.209 61.104 86.316 61.128 ;
     RECT  86.209 61.128 86.364 61.2 ;
     RECT  86.209 61.2 86.316 61.224 ;
     RECT  86.209 61.224 86.364 61.296 ;
     RECT  86.209 61.296 86.316 61.32 ;
     RECT  86.209 61.32 86.364 61.392 ;
     RECT  86.209 61.392 86.316 61.416 ;
     RECT  86.209 61.416 86.364 61.488 ;
     RECT  86.209 61.488 86.316 61.512 ;
     RECT  86.209 61.512 86.364 61.584 ;
     RECT  86.209 61.584 86.316 61.608 ;
     RECT  86.209 61.608 86.364 61.68 ;
     RECT  86.209 61.68 86.316 61.704 ;
     RECT  86.209 61.704 86.364 61.776 ;
     RECT  86.209 61.776 86.316 61.8 ;
     RECT  86.209 61.8 86.364 61.872 ;
     RECT  86.209 61.872 86.316 61.896 ;
     RECT  86.209 61.896 86.364 61.968 ;
     RECT  86.209 61.968 86.316 61.992 ;
     RECT  86.209 61.992 86.364 62.064 ;
     RECT  86.209 62.064 86.316 62.088 ;
     RECT  86.209 62.088 86.364 62.16 ;
     RECT  86.209 62.16 86.316 62.184 ;
     RECT  86.209 62.184 86.364 62.256 ;
     RECT  86.209 62.256 86.316 62.28 ;
     RECT  86.209 62.28 86.364 62.352 ;
     RECT  86.209 62.352 86.316 62.376 ;
     RECT  86.209 62.376 86.364 62.448 ;
     RECT  86.209 62.448 86.316 62.472 ;
     RECT  86.209 62.472 86.364 62.544 ;
     RECT  86.209 62.544 86.316 62.568 ;
     RECT  86.209 62.568 86.364 62.64 ;
     RECT  86.209 62.64 86.316 62.664 ;
     RECT  86.209 62.664 86.364 62.736 ;
     RECT  86.209 62.736 86.316 62.76 ;
     RECT  86.209 62.76 86.364 62.832 ;
     RECT  86.209 62.832 86.316 62.856 ;
     RECT  86.209 62.856 86.364 62.928 ;
     RECT  86.209 62.928 86.316 62.952 ;
     RECT  86.209 62.952 86.364 63.024 ;
     RECT  86.209 63.024 86.316 63.048 ;
     RECT  86.209 63.048 86.364 63.12 ;
     RECT  86.209 63.12 86.316 63.144 ;
     RECT  86.209 63.144 86.364 63.216 ;
     RECT  86.209 63.216 86.316 63.24 ;
     RECT  86.209 63.24 86.364 63.312 ;
     RECT  86.209 63.312 86.316 63.336 ;
     RECT  86.209 63.336 86.364 63.408 ;
     RECT  86.209 63.408 86.316 63.432 ;
     RECT  86.209 63.432 86.364 63.504 ;
     RECT  86.209 63.504 86.316 63.528 ;
     RECT  86.209 63.528 86.364 63.6 ;
     RECT  86.209 63.6 86.316 63.624 ;
     RECT  86.209 63.624 86.364 63.696 ;
     RECT  86.209 63.696 86.316 63.72 ;
     RECT  86.209 63.72 86.364 63.792 ;
     RECT  86.209 63.792 86.316 63.816 ;
     RECT  86.209 63.816 86.364 63.888 ;
     RECT  86.209 63.888 86.316 63.912 ;
     RECT  86.209 63.912 86.364 63.984 ;
     RECT  86.209 63.984 86.316 64.008 ;
     RECT  86.209 64.008 86.364 64.08 ;
     RECT  86.209 64.08 86.316 64.104 ;
     RECT  86.209 64.104 86.364 64.176 ;
     RECT  86.209 64.176 86.316 64.2 ;
     RECT  86.209 64.2 86.364 64.272 ;
     RECT  86.209 64.272 86.316 64.296 ;
     RECT  86.209 64.296 86.364 64.368 ;
     RECT  86.209 64.368 86.316 64.392 ;
     RECT  86.209 64.392 86.364 64.464 ;
     RECT  86.209 64.464 86.316 64.488 ;
     RECT  86.209 64.488 86.364 64.56 ;
     RECT  86.209 64.56 86.316 64.584 ;
     RECT  86.209 64.584 86.364 64.656 ;
     RECT  86.209 64.656 86.316 64.68 ;
     RECT  86.209 64.68 86.364 64.752 ;
     RECT  86.209 64.752 86.316 64.776 ;
     RECT  86.209 64.776 86.364 64.848 ;
     RECT  86.209 64.848 86.316 64.872 ;
     RECT  86.209 64.872 86.364 64.944 ;
     RECT  86.209 64.944 86.316 64.968 ;
     RECT  86.209 64.968 86.364 65.04 ;
     RECT  86.209 65.04 86.316 65.064 ;
     RECT  86.209 65.064 86.364 65.136 ;
     RECT  86.209 65.136 86.316 65.16 ;
     RECT  86.209 65.16 86.364 65.232 ;
     RECT  86.209 65.232 86.316 65.256 ;
     RECT  86.209 65.256 86.364 65.328 ;
     RECT  86.209 65.328 86.316 65.352 ;
     RECT  86.209 65.352 86.364 65.424 ;
     RECT  86.209 65.424 86.316 65.448 ;
     RECT  86.209 65.448 86.364 65.52 ;
     RECT  86.209 65.52 86.316 65.544 ;
     RECT  86.209 65.544 86.364 65.616 ;
     RECT  86.209 65.616 86.316 65.64 ;
     RECT  86.209 65.64 86.364 65.712 ;
     RECT  86.209 65.712 86.316 65.736 ;
     RECT  86.209 65.736 86.364 65.808 ;
     RECT  86.209 65.808 86.316 65.832 ;
     RECT  86.209 65.832 86.364 65.904 ;
     RECT  86.209 65.904 86.316 65.928 ;
     RECT  86.209 65.928 86.364 66 ;
     RECT  86.209 66 86.316 66.024 ;
     RECT  86.209 66.024 86.364 66.096 ;
     RECT  86.209 66.096 86.316 66.12 ;
     RECT  86.209 66.12 86.364 66.192 ;
     RECT  86.209 66.192 86.316 66.216 ;
     RECT  86.209 66.216 86.364 66.288 ;
     RECT  86.209 66.288 86.316 66.312 ;
     RECT  86.209 66.312 86.364 66.384 ;
     RECT  86.209 66.384 86.316 66.408 ;
     RECT  86.209 66.408 86.364 66.48 ;
     RECT  86.209 66.48 86.316 66.504 ;
     RECT  86.209 66.504 86.364 66.576 ;
     RECT  86.209 66.576 86.316 66.6 ;
     RECT  84.877 75.504 86.316 75.528 ;
     RECT  84.877 75.528 86.364 75.6 ;
     RECT  84.877 75.6 86.316 75.624 ;
     RECT  84.877 75.624 86.364 75.696 ;
     RECT  84.877 75.696 86.316 75.72 ;
     RECT  84.877 75.72 86.364 75.792 ;
     RECT  84.877 75.792 86.316 75.816 ;
     RECT  84.877 75.816 86.364 75.888 ;
     RECT  84.877 75.888 86.316 75.912 ;
     RECT  84.877 75.912 86.364 75.984 ;
     RECT  84.877 75.984 86.316 76.008 ;
     RECT  84.877 76.008 86.364 76.08 ;
     RECT  84.877 76.08 86.316 76.104 ;
     RECT  85.489 78 86.316 78.024 ;
     RECT  85.489 78.024 86.364 78.096 ;
     RECT  85.489 78.096 86.316 78.12 ;
     RECT  85.489 78.12 86.364 78.192 ;
     RECT  85.489 78.192 86.316 78.216 ;
     RECT  85.489 78.216 86.364 78.288 ;
     RECT  85.489 78.288 86.316 78.312 ;
     RECT  85.453 79.536 86.316 79.56 ;
     RECT  85.453 79.56 86.364 80.496 ;
     RECT  85.453 80.496 86.316 80.52 ;
     RECT  85.453 80.52 86.364 80.592 ;
     RECT  85.453 80.592 86.316 80.616 ;
     RECT  85.453 80.616 86.364 80.688 ;
     RECT  85.453 80.688 86.316 80.712 ;
     RECT  85.453 80.712 86.364 80.784 ;
     RECT  85.453 80.784 86.316 80.808 ;
     RECT  85.453 80.808 86.364 80.88 ;
     RECT  85.453 80.88 86.316 80.904 ;
     RECT  85.453 80.904 86.364 80.976 ;
     RECT  85.453 80.976 86.316 81 ;
     RECT  85.453 81 86.364 81.072 ;
     RECT  85.453 81.072 86.316 81.096 ;
     RECT  85.453 81.096 86.364 81.168 ;
     RECT  85.453 81.168 86.316 81.192 ;
     RECT  85.453 81.192 86.364 81.264 ;
     RECT  85.453 81.264 86.316 81.288 ;
     RECT  85.453 81.288 86.364 81.36 ;
     RECT  85.453 81.36 86.316 81.384 ;
     RECT  85.453 81.384 86.364 81.456 ;
     RECT  85.453 81.456 86.316 81.48 ;
     RECT  85.453 81.48 86.364 81.552 ;
     RECT  85.453 81.552 86.316 81.576 ;
     RECT  85.453 81.576 86.364 81.648 ;
     RECT  85.453 81.648 86.316 81.672 ;
     RECT  85.453 81.672 86.364 81.744 ;
     RECT  85.453 81.744 86.316 81.768 ;
     RECT  85.453 81.768 86.364 81.84 ;
     RECT  85.453 81.84 86.316 81.864 ;
     RECT  85.453 81.864 86.364 81.936 ;
     RECT  85.453 81.936 86.316 81.96 ;
    LAYER M5 ;
     RECT  2.4 2.137 2.52 2.151 ;
     RECT  7.8 2.137 7.92 2.151 ;
     RECT  13.2 2.137 13.32 2.151 ;
     RECT  18.6 2.137 18.72 2.151 ;
     RECT  24 2.137 24.12 2.151 ;
     RECT  29.4 2.137 29.52 2.151 ;
     RECT  34.8 2.137 34.92 2.151 ;
     RECT  40.2 2.137 40.32 2.151 ;
     RECT  45.6 2.137 45.72 2.151 ;
     RECT  51 2.137 51.12 2.151 ;
     RECT  56.4 2.137 56.52 2.151 ;
     RECT  61.8 2.137 61.92 2.151 ;
     RECT  67.2 2.137 67.32 2.151 ;
     RECT  72.6 2.137 72.72 2.151 ;
     RECT  78 2.137 78.12 2.151 ;
     RECT  83.4 2.137 83.52 2.151 ;
     RECT  7.8 2.151 8.112 33.061 ;
     RECT  6.864 33.061 8.112 34.163 ;
     RECT  2.4 2.151 2.712 34.453 ;
     RECT  2.304 34.453 2.712 34.643 ;
     RECT  79.68 33.877 79.704 35.411 ;
     RECT  5.568 35.173 5.592 35.845 ;
     RECT  78 2.151 78.312 35.845 ;
     RECT  5.568 35.845 5.688 35.891 ;
     RECT  78 35.845 79.272 37.667 ;
     RECT  7.8 34.163 8.112 39.253 ;
     RECT  5.664 35.891 5.688 39.395 ;
     RECT  6.864 39.253 8.112 40.067 ;
     RECT  81.168 36.661 81.192 42.803 ;
     RECT  2.4 34.643 2.712 43.093 ;
     RECT  2.304 43.093 2.712 43.283 ;
     RECT  5.616 39.877 5.64 44.245 ;
     RECT  4.896 44.245 5.64 44.291 ;
     RECT  2.4 43.283 2.712 45.205 ;
     RECT  76.944 45.205 76.968 45.301 ;
     RECT  78 37.667 78.312 45.301 ;
     RECT  2.304 45.205 2.712 45.347 ;
     RECT  76.944 45.301 78.312 45.445 ;
     RECT  76.944 45.445 79.032 45.539 ;
     RECT  77.088 45.539 79.032 45.685 ;
     RECT  77.088 45.685 79.32 45.827 ;
     RECT  77.088 45.827 79.032 46.211 ;
     RECT  81.12 43.237 81.144 46.213 ;
     RECT  80.352 46.213 81.144 46.259 ;
     RECT  80.352 46.259 80.376 46.739 ;
     RECT  76.944 46.837 76.968 47.075 ;
     RECT  0.144 45.781 0.168 47.123 ;
     RECT  78 46.211 78.312 47.221 ;
     RECT  2.4 45.347 2.712 47.317 ;
     RECT  2.304 47.317 2.712 47.507 ;
     RECT  4.896 44.291 4.92 47.749 ;
     RECT  4.56 47.749 4.92 47.795 ;
     RECT  77.232 47.221 78.312 48.275 ;
     RECT  0.144 48.997 0.168 49.187 ;
     RECT  4.56 47.795 4.584 50.579 ;
     RECT  2.4 47.507 2.712 50.869 ;
     RECT  2.4 50.869 2.856 51.683 ;
     RECT  78 48.275 78.312 54.613 ;
     RECT  80.064 47.269 80.088 54.613 ;
     RECT  4.56 52.405 4.584 54.661 ;
     RECT  4.56 54.661 5.544 55.283 ;
     RECT  78 54.613 80.088 55.427 ;
     RECT  4.56 55.283 4.872 55.859 ;
     RECT  78 55.427 78.984 55.955 ;
     RECT  2.4 51.683 2.712 56.341 ;
     RECT  80.064 55.427 80.088 56.483 ;
     RECT  2.256 56.341 2.712 56.531 ;
     RECT  65.232 52.981 65.256 57.059 ;
     RECT  83.4 2.151 83.712 57.301 ;
     RECT  20.16 50.533 20.184 57.395 ;
     RECT  38.784 57.109 38.808 57.395 ;
     RECT  83.184 57.301 83.712 57.443 ;
     RECT  18.6 2.151 18.912 57.541 ;
     RECT  0.336 57.541 0.36 57.685 ;
     RECT  0.144 57.685 0.36 57.875 ;
     RECT  6.672 55.957 6.696 58.163 ;
     RECT  7.8 40.067 8.112 58.501 ;
     RECT  0.336 57.875 0.36 58.547 ;
     RECT  18.6 57.541 19.032 58.691 ;
     RECT  78 55.955 78.312 59.173 ;
     RECT  7.68 58.501 8.112 60.611 ;
     RECT  78 59.173 78.408 60.611 ;
     RECT  75.984 61.861 76.008 62.197 ;
     RECT  75.888 62.197 76.008 62.243 ;
     RECT  4.848 55.859 4.872 63.205 ;
     RECT  79.488 58.549 79.512 63.779 ;
     RECT  75.888 62.243 75.912 64.979 ;
     RECT  4.224 63.205 4.872 69.203 ;
     RECT  4.848 69.203 4.872 70.069 ;
     RECT  79.44 63.829 79.464 70.117 ;
     RECT  80.544 66.757 80.568 70.117 ;
     RECT  79.44 70.117 80.568 70.163 ;
     RECT  45.6 2.151 45.912 73.765 ;
     RECT  45.36 73.765 45.912 74.723 ;
     RECT  79.68 70.163 80.568 75.539 ;
     RECT  4.848 70.069 5.784 76.979 ;
     RECT  47.472 73.765 47.496 77.795 ;
     RECT  65.28 57.397 65.304 77.843 ;
     RECT  79.68 75.539 79.704 78.613 ;
     RECT  5.76 76.979 5.784 78.659 ;
     RECT  51 2.151 51.312 79.189 ;
     RECT  47.328 77.797 47.352 79.283 ;
     RECT  45.6 74.723 45.912 79.717 ;
     RECT  50.448 79.189 51.312 79.763 ;
     RECT  78 60.611 78.312 79.765 ;
     RECT  42.72 78.901 42.744 79.859 ;
     RECT  79.68 78.613 79.848 79.859 ;
     RECT  79.824 79.859 79.848 79.955 ;
     RECT  45.456 79.717 45.912 80.483 ;
     RECT  77.52 79.765 78.312 80.771 ;
     RECT  49.392 80.101 49.416 82.019 ;
     RECT  81.792 81.541 81.816 83.267 ;
     RECT  2.4 56.531 2.712 84.249 ;
     RECT  7.8 60.611 8.112 84.249 ;
     RECT  13.2 2.151 13.512 84.249 ;
     RECT  18.6 58.691 18.912 84.249 ;
     RECT  24 2.151 24.312 84.249 ;
     RECT  29.4 2.151 29.712 84.249 ;
     RECT  34.8 2.151 35.112 84.249 ;
     RECT  40.2 2.151 40.512 84.249 ;
     RECT  45.6 80.483 45.912 84.249 ;
     RECT  51 79.763 51.312 84.249 ;
     RECT  56.4 2.151 56.712 84.249 ;
     RECT  61.8 2.151 62.112 84.249 ;
     RECT  67.2 2.151 67.512 84.249 ;
     RECT  72.6 2.151 72.912 84.249 ;
     RECT  78 80.771 78.312 84.249 ;
     RECT  83.4 57.443 83.712 84.249 ;
     RECT  2.4 84.249 2.52 84.263 ;
     RECT  7.8 84.249 7.92 84.263 ;
     RECT  13.2 84.249 13.32 84.263 ;
     RECT  18.6 84.249 18.72 84.263 ;
     RECT  24 84.249 24.12 84.263 ;
     RECT  29.4 84.249 29.52 84.263 ;
     RECT  34.8 84.249 34.92 84.263 ;
     RECT  40.2 84.249 40.32 84.263 ;
     RECT  45.6 84.249 45.72 84.263 ;
     RECT  51 84.249 51.12 84.263 ;
     RECT  56.4 84.249 56.52 84.263 ;
     RECT  61.8 84.249 61.92 84.263 ;
     RECT  67.2 84.249 67.32 84.263 ;
     RECT  72.6 84.249 72.72 84.263 ;
     RECT  78 84.249 78.12 84.263 ;
     RECT  83.4 84.249 83.52 84.263 ;
     RECT  78.312 33.877 79.68 35.411 ;
     RECT  78.312 35.411 79.272 35.845 ;
     RECT  5.688 39.253 6.864 39.395 ;
     RECT  5.664 39.395 6.864 39.877 ;
     RECT  5.64 39.877 6.864 40.067 ;
     RECT  76.968 45.205 78 45.301 ;
     RECT  76.944 45.539 77.088 46.211 ;
     RECT  76.944 46.211 78 46.837 ;
     RECT  76.968 46.837 78 47.075 ;
     RECT  77.232 47.075 78 47.221 ;
     RECT  18.912 50.533 20.16 57.395 ;
     RECT  78.984 55.427 80.064 55.955 ;
     RECT  6.696 55.957 7.8 58.163 ;
     RECT  38.808 57.109 40.2 57.395 ;
     RECT  18.912 57.395 19.032 57.541 ;
     RECT  7.68 58.163 7.8 58.501 ;
     RECT  78.312 58.549 79.488 59.173 ;
     RECT  78.408 59.173 79.488 60.611 ;
     RECT  78.312 60.611 79.488 63.779 ;
     RECT  2.712 63.205 4.224 69.203 ;
     RECT  78.312 63.779 79.464 63.829 ;
     RECT  78.312 63.829 79.44 70.163 ;
     RECT  79.464 66.757 80.544 70.117 ;
     RECT  78.312 70.163 79.68 79.859 ;
     RECT  45.912 77.797 47.328 79.283 ;
     RECT  78.312 79.859 79.824 79.955 ;
  END
END ot_hbm_su_programme_root_h5
END LIBRARY
